VERSION 5.8 ;
BUSBITCHARS "[]" ;
DIVIDERCHAR "/" ;
UNITS
    DATABASE MICRONS 1000 ;
END UNITS

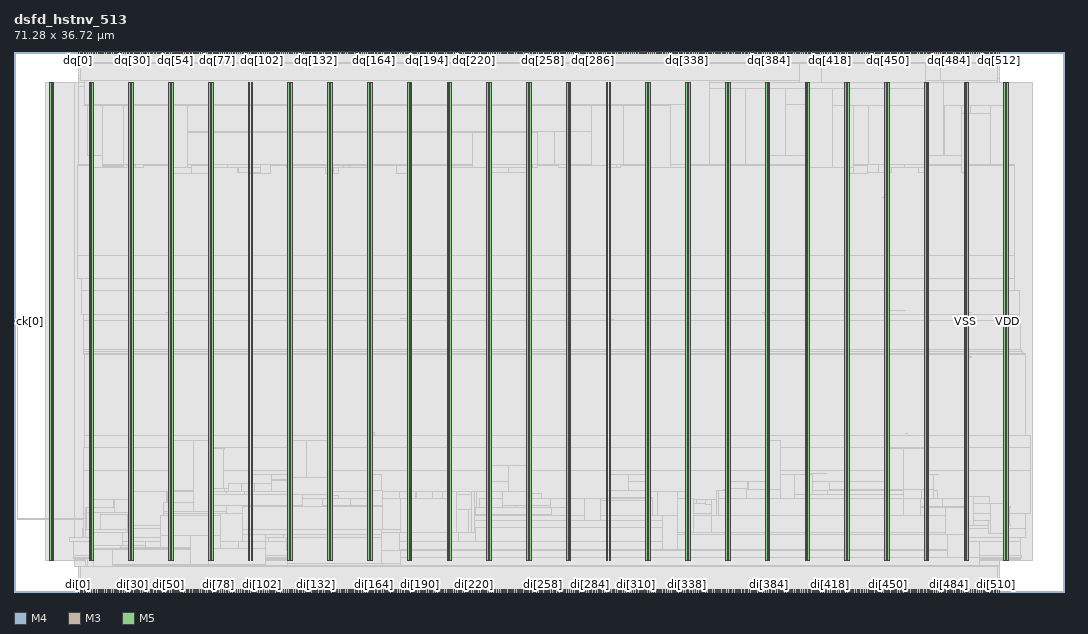
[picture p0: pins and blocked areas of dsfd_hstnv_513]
MACRO dsfd_hstnv_513
  FOREIGN dsfd_hstnv_513 0 0 ;
  CLASS BLOCK ;
  SIZE 71.28 BY 36.72 ;
  PIN ck[0]
    DIRECTION INPUT ;
    USE SIGNAL ;
    PORT
      LAYER M4 ;
        RECT  0 18.384 0.192 18.408 ;
    END
    PORT
      LAYER M4 ;
        RECT  0.156 18.384 0.275 18.408 ;
    END
  END ck[0]
  PIN di[0]
    DIRECTION INPUT ;
    USE SIGNAL ;
    PORT
      LAYER M3 ;
        RECT  4.356 0 4.374 0.144 ;
    END
  END di[0]
  PIN di[100]
    DIRECTION INPUT ;
    USE SIGNAL ;
    PORT
      LAYER M3 ;
        RECT  16.596 0 16.614 0.144 ;
    END
  END di[100]
  PIN di[101]
    DIRECTION INPUT ;
    USE SIGNAL ;
    PORT
      LAYER M5 ;
        RECT  16.704 0 16.728 0.192 ;
    END
  END di[101]
  PIN di[102]
    DIRECTION INPUT ;
    USE SIGNAL ;
    PORT
      LAYER M3 ;
        RECT  16.812 0 16.83 0.144 ;
    END
  END di[102]
  PIN di[103]
    DIRECTION INPUT ;
    USE SIGNAL ;
    PORT
      LAYER M5 ;
        RECT  16.944 0 16.968 0.192 ;
    END
  END di[103]
  PIN di[104]
    DIRECTION INPUT ;
    USE SIGNAL ;
    PORT
      LAYER M3 ;
        RECT  17.064 0 17.082 0.144 ;
    END
  END di[104]
  PIN di[105]
    DIRECTION INPUT ;
    USE SIGNAL ;
    PORT
      LAYER M5 ;
        RECT  17.184 0 17.208 0.192 ;
    END
  END di[105]
  PIN di[106]
    DIRECTION INPUT ;
    USE SIGNAL ;
    PORT
      LAYER M3 ;
        RECT  17.316 0 17.334 0.144 ;
    END
  END di[106]
  PIN di[107]
    DIRECTION INPUT ;
    USE SIGNAL ;
    PORT
      LAYER M5 ;
        RECT  17.424 0 17.448 0.192 ;
    END
  END di[107]
  PIN di[108]
    DIRECTION INPUT ;
    USE SIGNAL ;
    PORT
      LAYER M3 ;
        RECT  17.568 0 17.586 0.144 ;
    END
  END di[108]
  PIN di[109]
    DIRECTION INPUT ;
    USE SIGNAL ;
    PORT
      LAYER M5 ;
        RECT  17.664 0 17.688 0.192 ;
    END
  END di[109]
  PIN di[10]
    DIRECTION INPUT ;
    USE SIGNAL ;
    PORT
      LAYER M3 ;
        RECT  5.58 0 5.598 0.144 ;
    END
  END di[10]
  PIN di[110]
    DIRECTION INPUT ;
    USE SIGNAL ;
    PORT
      LAYER M3 ;
        RECT  17.82 0 17.838 0.144 ;
    END
  END di[110]
  PIN di[111]
    DIRECTION INPUT ;
    USE SIGNAL ;
    PORT
      LAYER M5 ;
        RECT  17.904 0 17.928 0.192 ;
    END
  END di[111]
  PIN di[112]
    DIRECTION INPUT ;
    USE SIGNAL ;
    PORT
      LAYER M3 ;
        RECT  18.036 0 18.054 0.144 ;
    END
  END di[112]
  PIN di[113]
    DIRECTION INPUT ;
    USE SIGNAL ;
    PORT
      LAYER M5 ;
        RECT  18.144 0 18.168 0.192 ;
    END
  END di[113]
  PIN di[114]
    DIRECTION INPUT ;
    USE SIGNAL ;
    PORT
      LAYER M3 ;
        RECT  18.288 0 18.306 0.144 ;
    END
  END di[114]
  PIN di[115]
    DIRECTION INPUT ;
    USE SIGNAL ;
    PORT
      LAYER M5 ;
        RECT  18.432 0 18.456 0.192 ;
    END
  END di[115]
  PIN di[116]
    DIRECTION INPUT ;
    USE SIGNAL ;
    PORT
      LAYER M3 ;
        RECT  18.54 0 18.558 0.144 ;
    END
  END di[116]
  PIN di[117]
    DIRECTION INPUT ;
    USE SIGNAL ;
    PORT
      LAYER M5 ;
        RECT  18.672 0 18.696 0.192 ;
    END
  END di[117]
  PIN di[118]
    DIRECTION INPUT ;
    USE SIGNAL ;
    PORT
      LAYER M3 ;
        RECT  18.792 0 18.81 0.144 ;
    END
  END di[118]
  PIN di[119]
    DIRECTION INPUT ;
    USE SIGNAL ;
    PORT
      LAYER M5 ;
        RECT  18.912 0 18.936 0.192 ;
    END
  END di[119]
  PIN di[11]
    DIRECTION INPUT ;
    USE SIGNAL ;
    PORT
      LAYER M5 ;
        RECT  5.712 0 5.736 0.192 ;
    END
  END di[11]
  PIN di[120]
    DIRECTION INPUT ;
    USE SIGNAL ;
    PORT
      LAYER M3 ;
        RECT  19.008 0 19.026 0.144 ;
    END
  END di[120]
  PIN di[121]
    DIRECTION INPUT ;
    USE SIGNAL ;
    PORT
      LAYER M5 ;
        RECT  19.152 0 19.176 0.192 ;
    END
  END di[121]
  PIN di[122]
    DIRECTION INPUT ;
    USE SIGNAL ;
    PORT
      LAYER M3 ;
        RECT  19.26 0 19.278 0.144 ;
    END
  END di[122]
  PIN di[123]
    DIRECTION INPUT ;
    USE SIGNAL ;
    PORT
      LAYER M5 ;
        RECT  19.392 0 19.416 0.192 ;
    END
  END di[123]
  PIN di[124]
    DIRECTION INPUT ;
    USE SIGNAL ;
    PORT
      LAYER M3 ;
        RECT  19.512 0 19.53 0.144 ;
    END
  END di[124]
  PIN di[125]
    DIRECTION INPUT ;
    USE SIGNAL ;
    PORT
      LAYER M5 ;
        RECT  19.632 0 19.656 0.192 ;
    END
  END di[125]
  PIN di[126]
    DIRECTION INPUT ;
    USE SIGNAL ;
    PORT
      LAYER M3 ;
        RECT  19.764 0 19.782 0.144 ;
    END
  END di[126]
  PIN di[127]
    DIRECTION INPUT ;
    USE SIGNAL ;
    PORT
      LAYER M5 ;
        RECT  19.872 0 19.896 0.192 ;
    END
  END di[127]
  PIN di[128]
    DIRECTION INPUT ;
    USE SIGNAL ;
    PORT
      LAYER M3 ;
        RECT  20.016 0 20.034 0.144 ;
    END
  END di[128]
  PIN di[129]
    DIRECTION INPUT ;
    USE SIGNAL ;
    PORT
      LAYER M5 ;
        RECT  20.112 0 20.136 0.192 ;
    END
  END di[129]
  PIN di[12]
    DIRECTION INPUT ;
    USE SIGNAL ;
    PORT
      LAYER M3 ;
        RECT  5.832 0 5.85 0.144 ;
    END
  END di[12]
  PIN di[130]
    DIRECTION INPUT ;
    USE SIGNAL ;
    PORT
      LAYER M3 ;
        RECT  20.232 0 20.25 0.144 ;
    END
  END di[130]
  PIN di[131]
    DIRECTION INPUT ;
    USE SIGNAL ;
    PORT
      LAYER M5 ;
        RECT  20.352 0 20.376 0.192 ;
    END
  END di[131]
  PIN di[132]
    DIRECTION INPUT ;
    USE SIGNAL ;
    PORT
      LAYER M3 ;
        RECT  20.484 0 20.502 0.144 ;
    END
  END di[132]
  PIN di[133]
    DIRECTION INPUT ;
    USE SIGNAL ;
    PORT
      LAYER M5 ;
        RECT  20.592 0 20.616 0.192 ;
    END
  END di[133]
  PIN di[134]
    DIRECTION INPUT ;
    USE SIGNAL ;
    PORT
      LAYER M3 ;
        RECT  20.736 0 20.754 0.144 ;
    END
  END di[134]
  PIN di[135]
    DIRECTION INPUT ;
    USE SIGNAL ;
    PORT
      LAYER M5 ;
        RECT  20.832 0 20.856 0.192 ;
    END
  END di[135]
  PIN di[136]
    DIRECTION INPUT ;
    USE SIGNAL ;
    PORT
      LAYER M3 ;
        RECT  20.988 0 21.006 0.144 ;
    END
  END di[136]
  PIN di[137]
    DIRECTION INPUT ;
    USE SIGNAL ;
    PORT
      LAYER M5 ;
        RECT  21.12 0 21.144 0.192 ;
    END
  END di[137]
  PIN di[138]
    DIRECTION INPUT ;
    USE SIGNAL ;
    PORT
      LAYER M3 ;
        RECT  21.24 0 21.258 0.144 ;
    END
  END di[138]
  PIN di[139]
    DIRECTION INPUT ;
    USE SIGNAL ;
    PORT
      LAYER M5 ;
        RECT  21.36 0 21.384 0.192 ;
    END
  END di[139]
  PIN di[13]
    DIRECTION INPUT ;
    USE SIGNAL ;
    PORT
      LAYER M5 ;
        RECT  5.952 0 5.976 0.192 ;
    END
  END di[13]
  PIN di[140]
    DIRECTION INPUT ;
    USE SIGNAL ;
    PORT
      LAYER M3 ;
        RECT  21.456 0 21.474 0.144 ;
    END
  END di[140]
  PIN di[141]
    DIRECTION INPUT ;
    USE SIGNAL ;
    PORT
      LAYER M5 ;
        RECT  21.6 0 21.624 0.192 ;
    END
  END di[141]
  PIN di[142]
    DIRECTION INPUT ;
    USE SIGNAL ;
    PORT
      LAYER M3 ;
        RECT  21.708 0 21.726 0.144 ;
    END
  END di[142]
  PIN di[143]
    DIRECTION INPUT ;
    USE SIGNAL ;
    PORT
      LAYER M5 ;
        RECT  21.84 0 21.864 0.192 ;
    END
  END di[143]
  PIN di[144]
    DIRECTION INPUT ;
    USE SIGNAL ;
    PORT
      LAYER M3 ;
        RECT  21.96 0 21.978 0.144 ;
    END
  END di[144]
  PIN di[145]
    DIRECTION INPUT ;
    USE SIGNAL ;
    PORT
      LAYER M5 ;
        RECT  22.08 0 22.104 0.192 ;
    END
  END di[145]
  PIN di[146]
    DIRECTION INPUT ;
    USE SIGNAL ;
    PORT
      LAYER M3 ;
        RECT  22.212 0 22.23 0.144 ;
    END
  END di[146]
  PIN di[147]
    DIRECTION INPUT ;
    USE SIGNAL ;
    PORT
      LAYER M5 ;
        RECT  22.32 0 22.344 0.192 ;
    END
  END di[147]
  PIN di[148]
    DIRECTION INPUT ;
    USE SIGNAL ;
    PORT
      LAYER M3 ;
        RECT  22.428 0 22.446 0.144 ;
    END
  END di[148]
  PIN di[149]
    DIRECTION INPUT ;
    USE SIGNAL ;
    PORT
      LAYER M5 ;
        RECT  22.56 0 22.584 0.192 ;
    END
  END di[149]
  PIN di[14]
    DIRECTION INPUT ;
    USE SIGNAL ;
    PORT
      LAYER M3 ;
        RECT  6.084 0 6.102 0.144 ;
    END
  END di[14]
  PIN di[150]
    DIRECTION INPUT ;
    USE SIGNAL ;
    PORT
      LAYER M3 ;
        RECT  22.68 0 22.698 0.144 ;
    END
  END di[150]
  PIN di[151]
    DIRECTION INPUT ;
    USE SIGNAL ;
    PORT
      LAYER M5 ;
        RECT  22.8 0 22.824 0.192 ;
    END
  END di[151]
  PIN di[152]
    DIRECTION INPUT ;
    USE SIGNAL ;
    PORT
      LAYER M3 ;
        RECT  22.932 0 22.95 0.144 ;
    END
  END di[152]
  PIN di[153]
    DIRECTION INPUT ;
    USE SIGNAL ;
    PORT
      LAYER M5 ;
        RECT  23.04 0 23.064 0.192 ;
    END
  END di[153]
  PIN di[154]
    DIRECTION INPUT ;
    USE SIGNAL ;
    PORT
      LAYER M3 ;
        RECT  23.184 0 23.202 0.144 ;
    END
  END di[154]
  PIN di[155]
    DIRECTION INPUT ;
    USE SIGNAL ;
    PORT
      LAYER M5 ;
        RECT  23.28 0 23.304 0.192 ;
    END
  END di[155]
  PIN di[156]
    DIRECTION INPUT ;
    USE SIGNAL ;
    PORT
      LAYER M3 ;
        RECT  23.436 0 23.454 0.144 ;
    END
  END di[156]
  PIN di[157]
    DIRECTION INPUT ;
    USE SIGNAL ;
    PORT
      LAYER M5 ;
        RECT  23.52 0 23.544 0.192 ;
    END
  END di[157]
  PIN di[158]
    DIRECTION INPUT ;
    USE SIGNAL ;
    PORT
      LAYER M3 ;
        RECT  23.652 0 23.67 0.144 ;
    END
  END di[158]
  PIN di[159]
    DIRECTION INPUT ;
    USE SIGNAL ;
    PORT
      LAYER M5 ;
        RECT  23.76 0 23.784 0.192 ;
    END
  END di[159]
  PIN di[15]
    DIRECTION INPUT ;
    USE SIGNAL ;
    PORT
      LAYER M5 ;
        RECT  6.192 0 6.216 0.192 ;
    END
  END di[15]
  PIN di[160]
    DIRECTION INPUT ;
    USE SIGNAL ;
    PORT
      LAYER M3 ;
        RECT  23.904 0 23.922 0.144 ;
    END
  END di[160]
  PIN di[161]
    DIRECTION INPUT ;
    USE SIGNAL ;
    PORT
      LAYER M5 ;
        RECT  24.048 0 24.072 0.192 ;
    END
  END di[161]
  PIN di[162]
    DIRECTION INPUT ;
    USE SIGNAL ;
    PORT
      LAYER M3 ;
        RECT  24.156 0 24.174 0.144 ;
    END
  END di[162]
  PIN di[163]
    DIRECTION INPUT ;
    USE SIGNAL ;
    PORT
      LAYER M5 ;
        RECT  24.288 0 24.312 0.192 ;
    END
  END di[163]
  PIN di[164]
    DIRECTION INPUT ;
    USE SIGNAL ;
    PORT
      LAYER M3 ;
        RECT  24.408 0 24.426 0.144 ;
    END
  END di[164]
  PIN di[165]
    DIRECTION INPUT ;
    USE SIGNAL ;
    PORT
      LAYER M5 ;
        RECT  24.528 0 24.552 0.192 ;
    END
  END di[165]
  PIN di[166]
    DIRECTION INPUT ;
    USE SIGNAL ;
    PORT
      LAYER M3 ;
        RECT  24.624 0 24.642 0.144 ;
    END
  END di[166]
  PIN di[167]
    DIRECTION INPUT ;
    USE SIGNAL ;
    PORT
      LAYER M5 ;
        RECT  24.768 0 24.792 0.192 ;
    END
  END di[167]
  PIN di[168]
    DIRECTION INPUT ;
    USE SIGNAL ;
    PORT
      LAYER M3 ;
        RECT  24.876 0 24.894 0.144 ;
    END
  END di[168]
  PIN di[169]
    DIRECTION INPUT ;
    USE SIGNAL ;
    PORT
      LAYER M5 ;
        RECT  25.008 0 25.032 0.192 ;
    END
  END di[169]
  PIN di[16]
    DIRECTION INPUT ;
    USE SIGNAL ;
    PORT
      LAYER M3 ;
        RECT  6.336 0 6.354 0.144 ;
    END
  END di[16]
  PIN di[170]
    DIRECTION INPUT ;
    USE SIGNAL ;
    PORT
      LAYER M3 ;
        RECT  25.128 0 25.146 0.144 ;
    END
  END di[170]
  PIN di[171]
    DIRECTION INPUT ;
    USE SIGNAL ;
    PORT
      LAYER M5 ;
        RECT  25.248 0 25.272 0.192 ;
    END
  END di[171]
  PIN di[172]
    DIRECTION INPUT ;
    USE SIGNAL ;
    PORT
      LAYER M3 ;
        RECT  25.38 0 25.398 0.144 ;
    END
  END di[172]
  PIN di[173]
    DIRECTION INPUT ;
    USE SIGNAL ;
    PORT
      LAYER M5 ;
        RECT  25.488 0 25.512 0.192 ;
    END
  END di[173]
  PIN di[174]
    DIRECTION INPUT ;
    USE SIGNAL ;
    PORT
      LAYER M3 ;
        RECT  25.632 0 25.65 0.144 ;
    END
  END di[174]
  PIN di[175]
    DIRECTION INPUT ;
    USE SIGNAL ;
    PORT
      LAYER M5 ;
        RECT  25.728 0 25.752 0.192 ;
    END
  END di[175]
  PIN di[176]
    DIRECTION INPUT ;
    USE SIGNAL ;
    PORT
      LAYER M3 ;
        RECT  25.848 0 25.866 0.144 ;
    END
  END di[176]
  PIN di[177]
    DIRECTION INPUT ;
    USE SIGNAL ;
    PORT
      LAYER M5 ;
        RECT  25.968 0 25.992 0.192 ;
    END
  END di[177]
  PIN di[178]
    DIRECTION INPUT ;
    USE SIGNAL ;
    PORT
      LAYER M3 ;
        RECT  26.1 0 26.118 0.144 ;
    END
  END di[178]
  PIN di[179]
    DIRECTION INPUT ;
    USE SIGNAL ;
    PORT
      LAYER M5 ;
        RECT  26.208 0 26.232 0.192 ;
    END
  END di[179]
  PIN di[17]
    DIRECTION INPUT ;
    USE SIGNAL ;
    PORT
      LAYER M5 ;
        RECT  6.432 0 6.456 0.192 ;
    END
  END di[17]
  PIN di[180]
    DIRECTION INPUT ;
    USE SIGNAL ;
    PORT
      LAYER M3 ;
        RECT  26.352 0 26.37 0.144 ;
    END
  END di[180]
  PIN di[181]
    DIRECTION INPUT ;
    USE SIGNAL ;
    PORT
      LAYER M5 ;
        RECT  26.448 0 26.472 0.192 ;
    END
  END di[181]
  PIN di[182]
    DIRECTION INPUT ;
    USE SIGNAL ;
    PORT
      LAYER M3 ;
        RECT  26.604 0 26.622 0.144 ;
    END
  END di[182]
  PIN di[183]
    DIRECTION INPUT ;
    USE SIGNAL ;
    PORT
      LAYER M5 ;
        RECT  26.736 0 26.76 0.192 ;
    END
  END di[183]
  PIN di[184]
    DIRECTION INPUT ;
    USE SIGNAL ;
    PORT
      LAYER M3 ;
        RECT  26.856 0 26.874 0.144 ;
    END
  END di[184]
  PIN di[185]
    DIRECTION INPUT ;
    USE SIGNAL ;
    PORT
      LAYER M5 ;
        RECT  26.976 0 27 0.192 ;
    END
  END di[185]
  PIN di[186]
    DIRECTION INPUT ;
    USE SIGNAL ;
    PORT
      LAYER M3 ;
        RECT  27.072 0 27.09 0.144 ;
    END
  END di[186]
  PIN di[187]
    DIRECTION INPUT ;
    USE SIGNAL ;
    PORT
      LAYER M5 ;
        RECT  27.216 0 27.24 0.192 ;
    END
  END di[187]
  PIN di[188]
    DIRECTION INPUT ;
    USE SIGNAL ;
    PORT
      LAYER M3 ;
        RECT  27.324 0 27.342 0.144 ;
    END
  END di[188]
  PIN di[189]
    DIRECTION INPUT ;
    USE SIGNAL ;
    PORT
      LAYER M5 ;
        RECT  27.456 0 27.48 0.192 ;
    END
  END di[189]
  PIN di[18]
    DIRECTION INPUT ;
    USE SIGNAL ;
    PORT
      LAYER M3 ;
        RECT  6.552 0 6.57 0.144 ;
    END
  END di[18]
  PIN di[190]
    DIRECTION INPUT ;
    USE SIGNAL ;
    PORT
      LAYER M3 ;
        RECT  27.576 0 27.594 0.144 ;
    END
  END di[190]
  PIN di[191]
    DIRECTION INPUT ;
    USE SIGNAL ;
    PORT
      LAYER M5 ;
        RECT  27.696 0 27.72 0.192 ;
    END
  END di[191]
  PIN di[192]
    DIRECTION INPUT ;
    USE SIGNAL ;
    PORT
      LAYER M3 ;
        RECT  27.828 0 27.846 0.144 ;
    END
  END di[192]
  PIN di[193]
    DIRECTION INPUT ;
    USE SIGNAL ;
    PORT
      LAYER M5 ;
        RECT  27.936 0 27.96 0.192 ;
    END
  END di[193]
  PIN di[194]
    DIRECTION INPUT ;
    USE SIGNAL ;
    PORT
      LAYER M3 ;
        RECT  28.044 0 28.062 0.144 ;
    END
  END di[194]
  PIN di[195]
    DIRECTION INPUT ;
    USE SIGNAL ;
    PORT
      LAYER M5 ;
        RECT  28.176 0 28.2 0.192 ;
    END
  END di[195]
  PIN di[196]
    DIRECTION INPUT ;
    USE SIGNAL ;
    PORT
      LAYER M3 ;
        RECT  28.296 0 28.314 0.144 ;
    END
  END di[196]
  PIN di[197]
    DIRECTION INPUT ;
    USE SIGNAL ;
    PORT
      LAYER M5 ;
        RECT  28.416 0 28.44 0.192 ;
    END
  END di[197]
  PIN di[198]
    DIRECTION INPUT ;
    USE SIGNAL ;
    PORT
      LAYER M3 ;
        RECT  28.548 0 28.566 0.144 ;
    END
  END di[198]
  PIN di[199]
    DIRECTION INPUT ;
    USE SIGNAL ;
    PORT
      LAYER M5 ;
        RECT  28.656 0 28.68 0.192 ;
    END
  END di[199]
  PIN di[19]
    DIRECTION INPUT ;
    USE SIGNAL ;
    PORT
      LAYER M5 ;
        RECT  6.672 0 6.696 0.192 ;
    END
  END di[19]
  PIN di[1]
    DIRECTION INPUT ;
    USE SIGNAL ;
    PORT
      LAYER M5 ;
        RECT  4.512 0 4.536 0.192 ;
    END
  END di[1]
  PIN di[200]
    DIRECTION INPUT ;
    USE SIGNAL ;
    PORT
      LAYER M3 ;
        RECT  28.8 0 28.818 0.144 ;
    END
  END di[200]
  PIN di[201]
    DIRECTION INPUT ;
    USE SIGNAL ;
    PORT
      LAYER M5 ;
        RECT  28.896 0 28.92 0.192 ;
    END
  END di[201]
  PIN di[202]
    DIRECTION INPUT ;
    USE SIGNAL ;
    PORT
      LAYER M3 ;
        RECT  29.052 0 29.07 0.144 ;
    END
  END di[202]
  PIN di[203]
    DIRECTION INPUT ;
    USE SIGNAL ;
    PORT
      LAYER M5 ;
        RECT  29.136 0 29.16 0.192 ;
    END
  END di[203]
  PIN di[204]
    DIRECTION INPUT ;
    USE SIGNAL ;
    PORT
      LAYER M3 ;
        RECT  29.268 0 29.286 0.144 ;
    END
  END di[204]
  PIN di[205]
    DIRECTION INPUT ;
    USE SIGNAL ;
    PORT
      LAYER M5 ;
        RECT  29.424 0 29.448 0.192 ;
    END
  END di[205]
  PIN di[206]
    DIRECTION INPUT ;
    USE SIGNAL ;
    PORT
      LAYER M3 ;
        RECT  29.52 0 29.538 0.144 ;
    END
  END di[206]
  PIN di[207]
    DIRECTION INPUT ;
    USE SIGNAL ;
    PORT
      LAYER M5 ;
        RECT  29.664 0 29.688 0.192 ;
    END
  END di[207]
  PIN di[208]
    DIRECTION INPUT ;
    USE SIGNAL ;
    PORT
      LAYER M3 ;
        RECT  29.772 0 29.79 0.144 ;
    END
  END di[208]
  PIN di[209]
    DIRECTION INPUT ;
    USE SIGNAL ;
    PORT
      LAYER M5 ;
        RECT  29.904 0 29.928 0.192 ;
    END
  END di[209]
  PIN di[20]
    DIRECTION INPUT ;
    USE SIGNAL ;
    PORT
      LAYER M3 ;
        RECT  6.804 0 6.822 0.144 ;
    END
  END di[20]
  PIN di[210]
    DIRECTION INPUT ;
    USE SIGNAL ;
    PORT
      LAYER M3 ;
        RECT  30.024 0 30.042 0.144 ;
    END
  END di[210]
  PIN di[211]
    DIRECTION INPUT ;
    USE SIGNAL ;
    PORT
      LAYER M5 ;
        RECT  30.144 0 30.168 0.192 ;
    END
  END di[211]
  PIN di[212]
    DIRECTION INPUT ;
    USE SIGNAL ;
    PORT
      LAYER M3 ;
        RECT  30.276 0 30.294 0.144 ;
    END
  END di[212]
  PIN di[213]
    DIRECTION INPUT ;
    USE SIGNAL ;
    PORT
      LAYER M5 ;
        RECT  30.384 0 30.408 0.192 ;
    END
  END di[213]
  PIN di[214]
    DIRECTION INPUT ;
    USE SIGNAL ;
    PORT
      LAYER M3 ;
        RECT  30.492 0 30.51 0.144 ;
    END
  END di[214]
  PIN di[215]
    DIRECTION INPUT ;
    USE SIGNAL ;
    PORT
      LAYER M5 ;
        RECT  30.624 0 30.648 0.192 ;
    END
  END di[215]
  PIN di[216]
    DIRECTION INPUT ;
    USE SIGNAL ;
    PORT
      LAYER M3 ;
        RECT  30.744 0 30.762 0.144 ;
    END
  END di[216]
  PIN di[217]
    DIRECTION INPUT ;
    USE SIGNAL ;
    PORT
      LAYER M5 ;
        RECT  30.864 0 30.888 0.192 ;
    END
  END di[217]
  PIN di[218]
    DIRECTION INPUT ;
    USE SIGNAL ;
    PORT
      LAYER M3 ;
        RECT  30.996 0 31.014 0.144 ;
    END
  END di[218]
  PIN di[219]
    DIRECTION INPUT ;
    USE SIGNAL ;
    PORT
      LAYER M5 ;
        RECT  31.104 0 31.128 0.192 ;
    END
  END di[219]
  PIN di[21]
    DIRECTION INPUT ;
    USE SIGNAL ;
    PORT
      LAYER M5 ;
        RECT  6.912 0 6.936 0.192 ;
    END
  END di[21]
  PIN di[220]
    DIRECTION INPUT ;
    USE SIGNAL ;
    PORT
      LAYER M3 ;
        RECT  31.248 0 31.266 0.144 ;
    END
  END di[220]
  PIN di[221]
    DIRECTION INPUT ;
    USE SIGNAL ;
    PORT
      LAYER M5 ;
        RECT  31.344 0 31.368 0.192 ;
    END
  END di[221]
  PIN di[222]
    DIRECTION INPUT ;
    USE SIGNAL ;
    PORT
      LAYER M3 ;
        RECT  31.464 0 31.482 0.144 ;
    END
  END di[222]
  PIN di[223]
    DIRECTION INPUT ;
    USE SIGNAL ;
    PORT
      LAYER M5 ;
        RECT  31.584 0 31.608 0.192 ;
    END
  END di[223]
  PIN di[224]
    DIRECTION INPUT ;
    USE SIGNAL ;
    PORT
      LAYER M3 ;
        RECT  31.716 0 31.734 0.144 ;
    END
  END di[224]
  PIN di[225]
    DIRECTION INPUT ;
    USE SIGNAL ;
    PORT
      LAYER M5 ;
        RECT  31.824 0 31.848 0.192 ;
    END
  END di[225]
  PIN di[226]
    DIRECTION INPUT ;
    USE SIGNAL ;
    PORT
      LAYER M3 ;
        RECT  31.968 0 31.986 0.144 ;
    END
  END di[226]
  PIN di[227]
    DIRECTION INPUT ;
    USE SIGNAL ;
    PORT
      LAYER M5 ;
        RECT  32.064 0 32.088 0.192 ;
    END
  END di[227]
  PIN di[228]
    DIRECTION INPUT ;
    USE SIGNAL ;
    PORT
      LAYER M3 ;
        RECT  32.22 0 32.238 0.144 ;
    END
  END di[228]
  PIN di[229]
    DIRECTION INPUT ;
    USE SIGNAL ;
    PORT
      LAYER M5 ;
        RECT  32.352 0 32.376 0.192 ;
    END
  END di[229]
  PIN di[22]
    DIRECTION INPUT ;
    USE SIGNAL ;
    PORT
      LAYER M3 ;
        RECT  7.056 0 7.074 0.144 ;
    END
  END di[22]
  PIN di[230]
    DIRECTION INPUT ;
    USE SIGNAL ;
    PORT
      LAYER M3 ;
        RECT  32.472 0 32.49 0.144 ;
    END
  END di[230]
  PIN di[231]
    DIRECTION INPUT ;
    USE SIGNAL ;
    PORT
      LAYER M5 ;
        RECT  32.592 0 32.616 0.192 ;
    END
  END di[231]
  PIN di[232]
    DIRECTION INPUT ;
    USE SIGNAL ;
    PORT
      LAYER M3 ;
        RECT  32.688 0 32.706 0.144 ;
    END
  END di[232]
  PIN di[233]
    DIRECTION INPUT ;
    USE SIGNAL ;
    PORT
      LAYER M5 ;
        RECT  32.832 0 32.856 0.192 ;
    END
  END di[233]
  PIN di[234]
    DIRECTION INPUT ;
    USE SIGNAL ;
    PORT
      LAYER M3 ;
        RECT  32.94 0 32.958 0.144 ;
    END
  END di[234]
  PIN di[235]
    DIRECTION INPUT ;
    USE SIGNAL ;
    PORT
      LAYER M5 ;
        RECT  33.072 0 33.096 0.192 ;
    END
  END di[235]
  PIN di[236]
    DIRECTION INPUT ;
    USE SIGNAL ;
    PORT
      LAYER M3 ;
        RECT  33.192 0 33.21 0.144 ;
    END
  END di[236]
  PIN di[237]
    DIRECTION INPUT ;
    USE SIGNAL ;
    PORT
      LAYER M5 ;
        RECT  33.312 0 33.336 0.192 ;
    END
  END di[237]
  PIN di[238]
    DIRECTION INPUT ;
    USE SIGNAL ;
    PORT
      LAYER M3 ;
        RECT  33.444 0 33.462 0.144 ;
    END
  END di[238]
  PIN di[239]
    DIRECTION INPUT ;
    USE SIGNAL ;
    PORT
      LAYER M5 ;
        RECT  33.552 0 33.576 0.192 ;
    END
  END di[239]
  PIN di[23]
    DIRECTION INPUT ;
    USE SIGNAL ;
    PORT
      LAYER M5 ;
        RECT  7.2 0 7.224 0.192 ;
    END
  END di[23]
  PIN di[240]
    DIRECTION INPUT ;
    USE SIGNAL ;
    PORT
      LAYER M3 ;
        RECT  33.66 0 33.678 0.144 ;
    END
  END di[240]
  PIN di[241]
    DIRECTION INPUT ;
    USE SIGNAL ;
    PORT
      LAYER M5 ;
        RECT  33.792 0 33.816 0.192 ;
    END
  END di[241]
  PIN di[242]
    DIRECTION INPUT ;
    USE SIGNAL ;
    PORT
      LAYER M3 ;
        RECT  33.912 0 33.93 0.144 ;
    END
  END di[242]
  PIN di[243]
    DIRECTION INPUT ;
    USE SIGNAL ;
    PORT
      LAYER M5 ;
        RECT  34.032 0 34.056 0.192 ;
    END
  END di[243]
  PIN di[244]
    DIRECTION INPUT ;
    USE SIGNAL ;
    PORT
      LAYER M3 ;
        RECT  34.164 0 34.182 0.144 ;
    END
  END di[244]
  PIN di[245]
    DIRECTION INPUT ;
    USE SIGNAL ;
    PORT
      LAYER M5 ;
        RECT  34.272 0 34.296 0.192 ;
    END
  END di[245]
  PIN di[246]
    DIRECTION INPUT ;
    USE SIGNAL ;
    PORT
      LAYER M3 ;
        RECT  34.416 0 34.434 0.144 ;
    END
  END di[246]
  PIN di[247]
    DIRECTION INPUT ;
    USE SIGNAL ;
    PORT
      LAYER M5 ;
        RECT  34.512 0 34.536 0.192 ;
    END
  END di[247]
  PIN di[248]
    DIRECTION INPUT ;
    USE SIGNAL ;
    PORT
      LAYER M3 ;
        RECT  34.668 0 34.686 0.144 ;
    END
  END di[248]
  PIN di[249]
    DIRECTION INPUT ;
    USE SIGNAL ;
    PORT
      LAYER M5 ;
        RECT  34.752 0 34.776 0.192 ;
    END
  END di[249]
  PIN di[24]
    DIRECTION INPUT ;
    USE SIGNAL ;
    PORT
      LAYER M3 ;
        RECT  7.308 0 7.326 0.144 ;
    END
  END di[24]
  PIN di[250]
    DIRECTION INPUT ;
    USE SIGNAL ;
    PORT
      LAYER M3 ;
        RECT  34.884 0 34.902 0.144 ;
    END
  END di[250]
  PIN di[251]
    DIRECTION INPUT ;
    USE SIGNAL ;
    PORT
      LAYER M5 ;
        RECT  35.04 0 35.064 0.192 ;
    END
  END di[251]
  PIN di[252]
    DIRECTION INPUT ;
    USE SIGNAL ;
    PORT
      LAYER M3 ;
        RECT  35.136 0 35.154 0.144 ;
    END
  END di[252]
  PIN di[253]
    DIRECTION INPUT ;
    USE SIGNAL ;
    PORT
      LAYER M5 ;
        RECT  35.28 0 35.304 0.192 ;
    END
  END di[253]
  PIN di[254]
    DIRECTION INPUT ;
    USE SIGNAL ;
    PORT
      LAYER M3 ;
        RECT  35.388 0 35.406 0.144 ;
    END
  END di[254]
  PIN di[255]
    DIRECTION INPUT ;
    USE SIGNAL ;
    PORT
      LAYER M5 ;
        RECT  35.52 0 35.544 0.192 ;
    END
  END di[255]
  PIN di[256]
    DIRECTION INPUT ;
    USE SIGNAL ;
    PORT
      LAYER M3 ;
        RECT  35.64 0 35.658 0.144 ;
    END
  END di[256]
  PIN di[257]
    DIRECTION INPUT ;
    USE SIGNAL ;
    PORT
      LAYER M5 ;
        RECT  35.76 0 35.784 0.192 ;
    END
  END di[257]
  PIN di[258]
    DIRECTION INPUT ;
    USE SIGNAL ;
    PORT
      LAYER M3 ;
        RECT  35.892 0 35.91 0.144 ;
    END
  END di[258]
  PIN di[259]
    DIRECTION INPUT ;
    USE SIGNAL ;
    PORT
      LAYER M5 ;
        RECT  36 0 36.024 0.192 ;
    END
  END di[259]
  PIN di[25]
    DIRECTION INPUT ;
    USE SIGNAL ;
    PORT
      LAYER M5 ;
        RECT  7.44 0 7.464 0.192 ;
    END
  END di[25]
  PIN di[260]
    DIRECTION INPUT ;
    USE SIGNAL ;
    PORT
      LAYER M3 ;
        RECT  36.108 0 36.126 0.144 ;
    END
  END di[260]
  PIN di[261]
    DIRECTION INPUT ;
    USE SIGNAL ;
    PORT
      LAYER M5 ;
        RECT  36.24 0 36.264 0.192 ;
    END
  END di[261]
  PIN di[262]
    DIRECTION INPUT ;
    USE SIGNAL ;
    PORT
      LAYER M3 ;
        RECT  36.36 0 36.378 0.144 ;
    END
  END di[262]
  PIN di[263]
    DIRECTION INPUT ;
    USE SIGNAL ;
    PORT
      LAYER M5 ;
        RECT  36.48 0 36.504 0.192 ;
    END
  END di[263]
  PIN di[264]
    DIRECTION INPUT ;
    USE SIGNAL ;
    PORT
      LAYER M3 ;
        RECT  36.612 0 36.63 0.144 ;
    END
  END di[264]
  PIN di[265]
    DIRECTION INPUT ;
    USE SIGNAL ;
    PORT
      LAYER M5 ;
        RECT  36.72 0 36.744 0.192 ;
    END
  END di[265]
  PIN di[266]
    DIRECTION INPUT ;
    USE SIGNAL ;
    PORT
      LAYER M3 ;
        RECT  36.864 0 36.882 0.144 ;
    END
  END di[266]
  PIN di[267]
    DIRECTION INPUT ;
    USE SIGNAL ;
    PORT
      LAYER M5 ;
        RECT  36.96 0 36.984 0.192 ;
    END
  END di[267]
  PIN di[268]
    DIRECTION INPUT ;
    USE SIGNAL ;
    PORT
      LAYER M3 ;
        RECT  37.08 0 37.098 0.144 ;
    END
  END di[268]
  PIN di[269]
    DIRECTION INPUT ;
    USE SIGNAL ;
    PORT
      LAYER M5 ;
        RECT  37.2 0 37.224 0.192 ;
    END
  END di[269]
  PIN di[26]
    DIRECTION INPUT ;
    USE SIGNAL ;
    PORT
      LAYER M3 ;
        RECT  7.56 0 7.578 0.144 ;
    END
  END di[26]
  PIN di[270]
    DIRECTION INPUT ;
    USE SIGNAL ;
    PORT
      LAYER M3 ;
        RECT  37.332 0 37.35 0.144 ;
    END
  END di[270]
  PIN di[271]
    DIRECTION INPUT ;
    USE SIGNAL ;
    PORT
      LAYER M5 ;
        RECT  37.44 0 37.464 0.192 ;
    END
  END di[271]
  PIN di[272]
    DIRECTION INPUT ;
    USE SIGNAL ;
    PORT
      LAYER M3 ;
        RECT  37.584 0 37.602 0.144 ;
    END
  END di[272]
  PIN di[273]
    DIRECTION INPUT ;
    USE SIGNAL ;
    PORT
      LAYER M5 ;
        RECT  37.68 0 37.704 0.192 ;
    END
  END di[273]
  PIN di[274]
    DIRECTION INPUT ;
    USE SIGNAL ;
    PORT
      LAYER M3 ;
        RECT  37.836 0 37.854 0.144 ;
    END
  END di[274]
  PIN di[275]
    DIRECTION INPUT ;
    USE SIGNAL ;
    PORT
      LAYER M5 ;
        RECT  37.968 0 37.992 0.192 ;
    END
  END di[275]
  PIN di[276]
    DIRECTION INPUT ;
    USE SIGNAL ;
    PORT
      LAYER M3 ;
        RECT  38.088 0 38.106 0.144 ;
    END
  END di[276]
  PIN di[277]
    DIRECTION INPUT ;
    USE SIGNAL ;
    PORT
      LAYER M5 ;
        RECT  38.208 0 38.232 0.192 ;
    END
  END di[277]
  PIN di[278]
    DIRECTION INPUT ;
    USE SIGNAL ;
    PORT
      LAYER M3 ;
        RECT  38.304 0 38.322 0.144 ;
    END
  END di[278]
  PIN di[279]
    DIRECTION INPUT ;
    USE SIGNAL ;
    PORT
      LAYER M5 ;
        RECT  38.448 0 38.472 0.192 ;
    END
  END di[279]
  PIN di[27]
    DIRECTION INPUT ;
    USE SIGNAL ;
    PORT
      LAYER M5 ;
        RECT  7.68 0 7.704 0.192 ;
    END
  END di[27]
  PIN di[280]
    DIRECTION INPUT ;
    USE SIGNAL ;
    PORT
      LAYER M3 ;
        RECT  38.556 0 38.574 0.144 ;
    END
  END di[280]
  PIN di[281]
    DIRECTION INPUT ;
    USE SIGNAL ;
    PORT
      LAYER M5 ;
        RECT  38.688 0 38.712 0.192 ;
    END
  END di[281]
  PIN di[282]
    DIRECTION INPUT ;
    USE SIGNAL ;
    PORT
      LAYER M3 ;
        RECT  38.808 0 38.826 0.144 ;
    END
  END di[282]
  PIN di[283]
    DIRECTION INPUT ;
    USE SIGNAL ;
    PORT
      LAYER M5 ;
        RECT  38.928 0 38.952 0.192 ;
    END
  END di[283]
  PIN di[284]
    DIRECTION INPUT ;
    USE SIGNAL ;
    PORT
      LAYER M3 ;
        RECT  39.06 0 39.078 0.144 ;
    END
  END di[284]
  PIN di[285]
    DIRECTION INPUT ;
    USE SIGNAL ;
    PORT
      LAYER M5 ;
        RECT  39.168 0 39.192 0.192 ;
    END
  END di[285]
  PIN di[286]
    DIRECTION INPUT ;
    USE SIGNAL ;
    PORT
      LAYER M3 ;
        RECT  39.312 0 39.33 0.144 ;
    END
  END di[286]
  PIN di[287]
    DIRECTION INPUT ;
    USE SIGNAL ;
    PORT
      LAYER M5 ;
        RECT  39.408 0 39.432 0.192 ;
    END
  END di[287]
  PIN di[288]
    DIRECTION INPUT ;
    USE SIGNAL ;
    PORT
      LAYER M3 ;
        RECT  39.528 0 39.546 0.144 ;
    END
  END di[288]
  PIN di[289]
    DIRECTION INPUT ;
    USE SIGNAL ;
    PORT
      LAYER M5 ;
        RECT  39.648 0 39.672 0.192 ;
    END
  END di[289]
  PIN di[28]
    DIRECTION INPUT ;
    USE SIGNAL ;
    PORT
      LAYER M3 ;
        RECT  7.776 0 7.794 0.144 ;
    END
  END di[28]
  PIN di[290]
    DIRECTION INPUT ;
    USE SIGNAL ;
    PORT
      LAYER M3 ;
        RECT  39.78 0 39.798 0.144 ;
    END
  END di[290]
  PIN di[291]
    DIRECTION INPUT ;
    USE SIGNAL ;
    PORT
      LAYER M5 ;
        RECT  39.888 0 39.912 0.192 ;
    END
  END di[291]
  PIN di[292]
    DIRECTION INPUT ;
    USE SIGNAL ;
    PORT
      LAYER M3 ;
        RECT  40.032 0 40.05 0.144 ;
    END
  END di[292]
  PIN di[293]
    DIRECTION INPUT ;
    USE SIGNAL ;
    PORT
      LAYER M5 ;
        RECT  40.128 0 40.152 0.192 ;
    END
  END di[293]
  PIN di[294]
    DIRECTION INPUT ;
    USE SIGNAL ;
    PORT
      LAYER M3 ;
        RECT  40.284 0 40.302 0.144 ;
    END
  END di[294]
  PIN di[295]
    DIRECTION INPUT ;
    USE SIGNAL ;
    PORT
      LAYER M5 ;
        RECT  40.368 0 40.392 0.192 ;
    END
  END di[295]
  PIN di[296]
    DIRECTION INPUT ;
    USE SIGNAL ;
    PORT
      LAYER M3 ;
        RECT  40.5 0 40.518 0.144 ;
    END
  END di[296]
  PIN di[297]
    DIRECTION INPUT ;
    USE SIGNAL ;
    PORT
      LAYER M5 ;
        RECT  40.656 0 40.68 0.192 ;
    END
  END di[297]
  PIN di[298]
    DIRECTION INPUT ;
    USE SIGNAL ;
    PORT
      LAYER M3 ;
        RECT  40.752 0 40.77 0.144 ;
    END
  END di[298]
  PIN di[299]
    DIRECTION INPUT ;
    USE SIGNAL ;
    PORT
      LAYER M5 ;
        RECT  40.896 0 40.92 0.192 ;
    END
  END di[299]
  PIN di[29]
    DIRECTION INPUT ;
    USE SIGNAL ;
    PORT
      LAYER M5 ;
        RECT  7.92 0 7.944 0.192 ;
    END
  END di[29]
  PIN di[2]
    DIRECTION INPUT ;
    USE SIGNAL ;
    PORT
      LAYER M3 ;
        RECT  4.608 0 4.626 0.144 ;
    END
  END di[2]
  PIN di[300]
    DIRECTION INPUT ;
    USE SIGNAL ;
    PORT
      LAYER M3 ;
        RECT  41.004 0 41.022 0.144 ;
    END
  END di[300]
  PIN di[301]
    DIRECTION INPUT ;
    USE SIGNAL ;
    PORT
      LAYER M5 ;
        RECT  41.136 0 41.16 0.192 ;
    END
  END di[301]
  PIN di[302]
    DIRECTION INPUT ;
    USE SIGNAL ;
    PORT
      LAYER M3 ;
        RECT  41.256 0 41.274 0.144 ;
    END
  END di[302]
  PIN di[303]
    DIRECTION INPUT ;
    USE SIGNAL ;
    PORT
      LAYER M5 ;
        RECT  41.376 0 41.4 0.192 ;
    END
  END di[303]
  PIN di[304]
    DIRECTION INPUT ;
    USE SIGNAL ;
    PORT
      LAYER M3 ;
        RECT  41.508 0 41.526 0.144 ;
    END
  END di[304]
  PIN di[305]
    DIRECTION INPUT ;
    USE SIGNAL ;
    PORT
      LAYER M5 ;
        RECT  41.616 0 41.64 0.192 ;
    END
  END di[305]
  PIN di[306]
    DIRECTION INPUT ;
    USE SIGNAL ;
    PORT
      LAYER M3 ;
        RECT  41.724 0 41.742 0.144 ;
    END
  END di[306]
  PIN di[307]
    DIRECTION INPUT ;
    USE SIGNAL ;
    PORT
      LAYER M5 ;
        RECT  41.856 0 41.88 0.192 ;
    END
  END di[307]
  PIN di[308]
    DIRECTION INPUT ;
    USE SIGNAL ;
    PORT
      LAYER M3 ;
        RECT  41.976 0 41.994 0.144 ;
    END
  END di[308]
  PIN di[309]
    DIRECTION INPUT ;
    USE SIGNAL ;
    PORT
      LAYER M5 ;
        RECT  42.096 0 42.12 0.192 ;
    END
  END di[309]
  PIN di[30]
    DIRECTION INPUT ;
    USE SIGNAL ;
    PORT
      LAYER M3 ;
        RECT  8.028 0 8.046 0.144 ;
    END
  END di[30]
  PIN di[310]
    DIRECTION INPUT ;
    USE SIGNAL ;
    PORT
      LAYER M3 ;
        RECT  42.228 0 42.246 0.144 ;
    END
  END di[310]
  PIN di[311]
    DIRECTION INPUT ;
    USE SIGNAL ;
    PORT
      LAYER M5 ;
        RECT  42.336 0 42.36 0.192 ;
    END
  END di[311]
  PIN di[312]
    DIRECTION INPUT ;
    USE SIGNAL ;
    PORT
      LAYER M3 ;
        RECT  42.48 0 42.498 0.144 ;
    END
  END di[312]
  PIN di[313]
    DIRECTION INPUT ;
    USE SIGNAL ;
    PORT
      LAYER M5 ;
        RECT  42.576 0 42.6 0.192 ;
    END
  END di[313]
  PIN di[314]
    DIRECTION INPUT ;
    USE SIGNAL ;
    PORT
      LAYER M3 ;
        RECT  42.696 0 42.714 0.144 ;
    END
  END di[314]
  PIN di[315]
    DIRECTION INPUT ;
    USE SIGNAL ;
    PORT
      LAYER M5 ;
        RECT  42.816 0 42.84 0.192 ;
    END
  END di[315]
  PIN di[316]
    DIRECTION INPUT ;
    USE SIGNAL ;
    PORT
      LAYER M3 ;
        RECT  42.948 0 42.966 0.144 ;
    END
  END di[316]
  PIN di[317]
    DIRECTION INPUT ;
    USE SIGNAL ;
    PORT
      LAYER M5 ;
        RECT  43.056 0 43.08 0.192 ;
    END
  END di[317]
  PIN di[318]
    DIRECTION INPUT ;
    USE SIGNAL ;
    PORT
      LAYER M3 ;
        RECT  43.2 0 43.218 0.144 ;
    END
  END di[318]
  PIN di[319]
    DIRECTION INPUT ;
    USE SIGNAL ;
    PORT
      LAYER M5 ;
        RECT  43.344 0 43.368 0.192 ;
    END
  END di[319]
  PIN di[31]
    DIRECTION INPUT ;
    USE SIGNAL ;
    PORT
      LAYER M5 ;
        RECT  8.16 0 8.184 0.192 ;
    END
  END di[31]
  PIN di[320]
    DIRECTION INPUT ;
    USE SIGNAL ;
    PORT
      LAYER M3 ;
        RECT  43.452 0 43.47 0.144 ;
    END
  END di[320]
  PIN di[321]
    DIRECTION INPUT ;
    USE SIGNAL ;
    PORT
      LAYER M5 ;
        RECT  43.584 0 43.608 0.192 ;
    END
  END di[321]
  PIN di[322]
    DIRECTION INPUT ;
    USE SIGNAL ;
    PORT
      LAYER M3 ;
        RECT  43.704 0 43.722 0.144 ;
    END
  END di[322]
  PIN di[323]
    DIRECTION INPUT ;
    USE SIGNAL ;
    PORT
      LAYER M5 ;
        RECT  43.824 0 43.848 0.192 ;
    END
  END di[323]
  PIN di[324]
    DIRECTION INPUT ;
    USE SIGNAL ;
    PORT
      LAYER M3 ;
        RECT  43.92 0 43.938 0.144 ;
    END
  END di[324]
  PIN di[325]
    DIRECTION INPUT ;
    USE SIGNAL ;
    PORT
      LAYER M5 ;
        RECT  44.064 0 44.088 0.192 ;
    END
  END di[325]
  PIN di[326]
    DIRECTION INPUT ;
    USE SIGNAL ;
    PORT
      LAYER M3 ;
        RECT  44.172 0 44.19 0.144 ;
    END
  END di[326]
  PIN di[327]
    DIRECTION INPUT ;
    USE SIGNAL ;
    PORT
      LAYER M5 ;
        RECT  44.304 0 44.328 0.192 ;
    END
  END di[327]
  PIN di[328]
    DIRECTION INPUT ;
    USE SIGNAL ;
    PORT
      LAYER M3 ;
        RECT  44.424 0 44.442 0.144 ;
    END
  END di[328]
  PIN di[329]
    DIRECTION INPUT ;
    USE SIGNAL ;
    PORT
      LAYER M5 ;
        RECT  44.544 0 44.568 0.192 ;
    END
  END di[329]
  PIN di[32]
    DIRECTION INPUT ;
    USE SIGNAL ;
    PORT
      LAYER M3 ;
        RECT  8.28 0 8.298 0.144 ;
    END
  END di[32]
  PIN di[330]
    DIRECTION INPUT ;
    USE SIGNAL ;
    PORT
      LAYER M3 ;
        RECT  44.676 0 44.694 0.144 ;
    END
  END di[330]
  PIN di[331]
    DIRECTION INPUT ;
    USE SIGNAL ;
    PORT
      LAYER M5 ;
        RECT  44.784 0 44.808 0.192 ;
    END
  END di[331]
  PIN di[332]
    DIRECTION INPUT ;
    USE SIGNAL ;
    PORT
      LAYER M3 ;
        RECT  44.928 0 44.946 0.144 ;
    END
  END di[332]
  PIN di[333]
    DIRECTION INPUT ;
    USE SIGNAL ;
    PORT
      LAYER M5 ;
        RECT  45.024 0 45.048 0.192 ;
    END
  END di[333]
  PIN di[334]
    DIRECTION INPUT ;
    USE SIGNAL ;
    PORT
      LAYER M3 ;
        RECT  45.144 0 45.162 0.144 ;
    END
  END di[334]
  PIN di[335]
    DIRECTION INPUT ;
    USE SIGNAL ;
    PORT
      LAYER M5 ;
        RECT  45.264 0 45.288 0.192 ;
    END
  END di[335]
  PIN di[336]
    DIRECTION INPUT ;
    USE SIGNAL ;
    PORT
      LAYER M3 ;
        RECT  45.396 0 45.414 0.144 ;
    END
  END di[336]
  PIN di[337]
    DIRECTION INPUT ;
    USE SIGNAL ;
    PORT
      LAYER M5 ;
        RECT  45.504 0 45.528 0.192 ;
    END
  END di[337]
  PIN di[338]
    DIRECTION INPUT ;
    USE SIGNAL ;
    PORT
      LAYER M3 ;
        RECT  45.648 0 45.666 0.144 ;
    END
  END di[338]
  PIN di[339]
    DIRECTION INPUT ;
    USE SIGNAL ;
    PORT
      LAYER M5 ;
        RECT  45.744 0 45.768 0.192 ;
    END
  END di[339]
  PIN di[33]
    DIRECTION INPUT ;
    USE SIGNAL ;
    PORT
      LAYER M5 ;
        RECT  8.4 0 8.424 0.192 ;
    END
  END di[33]
  PIN di[340]
    DIRECTION INPUT ;
    USE SIGNAL ;
    PORT
      LAYER M3 ;
        RECT  45.9 0 45.918 0.144 ;
    END
  END di[340]
  PIN di[341]
    DIRECTION INPUT ;
    USE SIGNAL ;
    PORT
      LAYER M5 ;
        RECT  45.984 0 46.008 0.192 ;
    END
  END di[341]
  PIN di[342]
    DIRECTION INPUT ;
    USE SIGNAL ;
    PORT
      LAYER M3 ;
        RECT  46.116 0 46.134 0.144 ;
    END
  END di[342]
  PIN di[343]
    DIRECTION INPUT ;
    USE SIGNAL ;
    PORT
      LAYER M5 ;
        RECT  46.272 0 46.296 0.192 ;
    END
  END di[343]
  PIN di[344]
    DIRECTION INPUT ;
    USE SIGNAL ;
    PORT
      LAYER M3 ;
        RECT  46.368 0 46.386 0.144 ;
    END
  END di[344]
  PIN di[345]
    DIRECTION INPUT ;
    USE SIGNAL ;
    PORT
      LAYER M5 ;
        RECT  46.512 0 46.536 0.192 ;
    END
  END di[345]
  PIN di[346]
    DIRECTION INPUT ;
    USE SIGNAL ;
    PORT
      LAYER M3 ;
        RECT  46.62 0 46.638 0.144 ;
    END
  END di[346]
  PIN di[347]
    DIRECTION INPUT ;
    USE SIGNAL ;
    PORT
      LAYER M5 ;
        RECT  46.752 0 46.776 0.192 ;
    END
  END di[347]
  PIN di[348]
    DIRECTION INPUT ;
    USE SIGNAL ;
    PORT
      LAYER M3 ;
        RECT  46.872 0 46.89 0.144 ;
    END
  END di[348]
  PIN di[349]
    DIRECTION INPUT ;
    USE SIGNAL ;
    PORT
      LAYER M5 ;
        RECT  46.992 0 47.016 0.192 ;
    END
  END di[349]
  PIN di[34]
    DIRECTION INPUT ;
    USE SIGNAL ;
    PORT
      LAYER M3 ;
        RECT  8.532 0 8.55 0.144 ;
    END
  END di[34]
  PIN di[350]
    DIRECTION INPUT ;
    USE SIGNAL ;
    PORT
      LAYER M3 ;
        RECT  47.124 0 47.142 0.144 ;
    END
  END di[350]
  PIN di[351]
    DIRECTION INPUT ;
    USE SIGNAL ;
    PORT
      LAYER M5 ;
        RECT  47.232 0 47.256 0.192 ;
    END
  END di[351]
  PIN di[352]
    DIRECTION INPUT ;
    USE SIGNAL ;
    PORT
      LAYER M3 ;
        RECT  47.34 0 47.358 0.144 ;
    END
  END di[352]
  PIN di[353]
    DIRECTION INPUT ;
    USE SIGNAL ;
    PORT
      LAYER M5 ;
        RECT  47.472 0 47.496 0.192 ;
    END
  END di[353]
  PIN di[354]
    DIRECTION INPUT ;
    USE SIGNAL ;
    PORT
      LAYER M3 ;
        RECT  47.592 0 47.61 0.144 ;
    END
  END di[354]
  PIN di[355]
    DIRECTION INPUT ;
    USE SIGNAL ;
    PORT
      LAYER M5 ;
        RECT  47.712 0 47.736 0.192 ;
    END
  END di[355]
  PIN di[356]
    DIRECTION INPUT ;
    USE SIGNAL ;
    PORT
      LAYER M3 ;
        RECT  47.844 0 47.862 0.144 ;
    END
  END di[356]
  PIN di[357]
    DIRECTION INPUT ;
    USE SIGNAL ;
    PORT
      LAYER M5 ;
        RECT  47.952 0 47.976 0.192 ;
    END
  END di[357]
  PIN di[358]
    DIRECTION INPUT ;
    USE SIGNAL ;
    PORT
      LAYER M3 ;
        RECT  48.096 0 48.114 0.144 ;
    END
  END di[358]
  PIN di[359]
    DIRECTION INPUT ;
    USE SIGNAL ;
    PORT
      LAYER M5 ;
        RECT  48.192 0 48.216 0.192 ;
    END
  END di[359]
  PIN di[35]
    DIRECTION INPUT ;
    USE SIGNAL ;
    PORT
      LAYER M5 ;
        RECT  8.64 0 8.664 0.192 ;
    END
  END di[35]
  PIN di[360]
    DIRECTION INPUT ;
    USE SIGNAL ;
    PORT
      LAYER M3 ;
        RECT  48.312 0 48.33 0.144 ;
    END
  END di[360]
  PIN di[361]
    DIRECTION INPUT ;
    USE SIGNAL ;
    PORT
      LAYER M5 ;
        RECT  48.432 0 48.456 0.192 ;
    END
  END di[361]
  PIN di[362]
    DIRECTION INPUT ;
    USE SIGNAL ;
    PORT
      LAYER M3 ;
        RECT  48.564 0 48.582 0.144 ;
    END
  END di[362]
  PIN di[363]
    DIRECTION INPUT ;
    USE SIGNAL ;
    PORT
      LAYER M5 ;
        RECT  48.672 0 48.696 0.192 ;
    END
  END di[363]
  PIN di[364]
    DIRECTION INPUT ;
    USE SIGNAL ;
    PORT
      LAYER M3 ;
        RECT  48.816 0 48.834 0.144 ;
    END
  END di[364]
  PIN di[365]
    DIRECTION INPUT ;
    USE SIGNAL ;
    PORT
      LAYER M5 ;
        RECT  48.96 0 48.984 0.192 ;
    END
  END di[365]
  PIN di[366]
    DIRECTION INPUT ;
    USE SIGNAL ;
    PORT
      LAYER M3 ;
        RECT  49.068 0 49.086 0.144 ;
    END
  END di[366]
  PIN di[367]
    DIRECTION INPUT ;
    USE SIGNAL ;
    PORT
      LAYER M5 ;
        RECT  49.2 0 49.224 0.192 ;
    END
  END di[367]
  PIN di[368]
    DIRECTION INPUT ;
    USE SIGNAL ;
    PORT
      LAYER M3 ;
        RECT  49.32 0 49.338 0.144 ;
    END
  END di[368]
  PIN di[369]
    DIRECTION INPUT ;
    USE SIGNAL ;
    PORT
      LAYER M5 ;
        RECT  49.44 0 49.464 0.192 ;
    END
  END di[369]
  PIN di[36]
    DIRECTION INPUT ;
    USE SIGNAL ;
    PORT
      LAYER M3 ;
        RECT  8.784 0 8.802 0.144 ;
    END
  END di[36]
  PIN di[370]
    DIRECTION INPUT ;
    USE SIGNAL ;
    PORT
      LAYER M3 ;
        RECT  49.536 0 49.554 0.144 ;
    END
  END di[370]
  PIN di[371]
    DIRECTION INPUT ;
    USE SIGNAL ;
    PORT
      LAYER M5 ;
        RECT  49.68 0 49.704 0.192 ;
    END
  END di[371]
  PIN di[372]
    DIRECTION INPUT ;
    USE SIGNAL ;
    PORT
      LAYER M3 ;
        RECT  49.788 0 49.806 0.144 ;
    END
  END di[372]
  PIN di[373]
    DIRECTION INPUT ;
    USE SIGNAL ;
    PORT
      LAYER M5 ;
        RECT  49.92 0 49.944 0.192 ;
    END
  END di[373]
  PIN di[374]
    DIRECTION INPUT ;
    USE SIGNAL ;
    PORT
      LAYER M3 ;
        RECT  50.04 0 50.058 0.144 ;
    END
  END di[374]
  PIN di[375]
    DIRECTION INPUT ;
    USE SIGNAL ;
    PORT
      LAYER M5 ;
        RECT  50.16 0 50.184 0.192 ;
    END
  END di[375]
  PIN di[376]
    DIRECTION INPUT ;
    USE SIGNAL ;
    PORT
      LAYER M3 ;
        RECT  50.292 0 50.31 0.144 ;
    END
  END di[376]
  PIN di[377]
    DIRECTION INPUT ;
    USE SIGNAL ;
    PORT
      LAYER M5 ;
        RECT  50.4 0 50.424 0.192 ;
    END
  END di[377]
  PIN di[378]
    DIRECTION INPUT ;
    USE SIGNAL ;
    PORT
      LAYER M3 ;
        RECT  50.544 0 50.562 0.144 ;
    END
  END di[378]
  PIN di[379]
    DIRECTION INPUT ;
    USE SIGNAL ;
    PORT
      LAYER M5 ;
        RECT  50.64 0 50.664 0.192 ;
    END
  END di[379]
  PIN di[37]
    DIRECTION INPUT ;
    USE SIGNAL ;
    PORT
      LAYER M5 ;
        RECT  8.88 0 8.904 0.192 ;
    END
  END di[37]
  PIN di[380]
    DIRECTION INPUT ;
    USE SIGNAL ;
    PORT
      LAYER M3 ;
        RECT  50.76 0 50.778 0.144 ;
    END
  END di[380]
  PIN di[381]
    DIRECTION INPUT ;
    USE SIGNAL ;
    PORT
      LAYER M5 ;
        RECT  50.88 0 50.904 0.192 ;
    END
  END di[381]
  PIN di[382]
    DIRECTION INPUT ;
    USE SIGNAL ;
    PORT
      LAYER M3 ;
        RECT  51.012 0 51.03 0.144 ;
    END
  END di[382]
  PIN di[383]
    DIRECTION INPUT ;
    USE SIGNAL ;
    PORT
      LAYER M5 ;
        RECT  51.12 0 51.144 0.192 ;
    END
  END di[383]
  PIN di[384]
    DIRECTION INPUT ;
    USE SIGNAL ;
    PORT
      LAYER M3 ;
        RECT  51.264 0 51.282 0.144 ;
    END
  END di[384]
  PIN di[385]
    DIRECTION INPUT ;
    USE SIGNAL ;
    PORT
      LAYER M5 ;
        RECT  51.36 0 51.384 0.192 ;
    END
  END di[385]
  PIN di[386]
    DIRECTION INPUT ;
    USE SIGNAL ;
    PORT
      LAYER M3 ;
        RECT  51.516 0 51.534 0.144 ;
    END
  END di[386]
  PIN di[387]
    DIRECTION INPUT ;
    USE SIGNAL ;
    PORT
      LAYER M5 ;
        RECT  51.6 0 51.624 0.192 ;
    END
  END di[387]
  PIN di[388]
    DIRECTION INPUT ;
    USE SIGNAL ;
    PORT
      LAYER M3 ;
        RECT  51.732 0 51.75 0.144 ;
    END
  END di[388]
  PIN di[389]
    DIRECTION INPUT ;
    USE SIGNAL ;
    PORT
      LAYER M5 ;
        RECT  51.888 0 51.912 0.192 ;
    END
  END di[389]
  PIN di[38]
    DIRECTION INPUT ;
    USE SIGNAL ;
    PORT
      LAYER M3 ;
        RECT  9 0 9.018 0.144 ;
    END
  END di[38]
  PIN di[390]
    DIRECTION INPUT ;
    USE SIGNAL ;
    PORT
      LAYER M3 ;
        RECT  51.984 0 52.002 0.144 ;
    END
  END di[390]
  PIN di[391]
    DIRECTION INPUT ;
    USE SIGNAL ;
    PORT
      LAYER M5 ;
        RECT  52.128 0 52.152 0.192 ;
    END
  END di[391]
  PIN di[392]
    DIRECTION INPUT ;
    USE SIGNAL ;
    PORT
      LAYER M3 ;
        RECT  52.236 0 52.254 0.144 ;
    END
  END di[392]
  PIN di[393]
    DIRECTION INPUT ;
    USE SIGNAL ;
    PORT
      LAYER M5 ;
        RECT  52.368 0 52.392 0.192 ;
    END
  END di[393]
  PIN di[394]
    DIRECTION INPUT ;
    USE SIGNAL ;
    PORT
      LAYER M3 ;
        RECT  52.488 0 52.506 0.144 ;
    END
  END di[394]
  PIN di[395]
    DIRECTION INPUT ;
    USE SIGNAL ;
    PORT
      LAYER M5 ;
        RECT  52.608 0 52.632 0.192 ;
    END
  END di[395]
  PIN di[396]
    DIRECTION INPUT ;
    USE SIGNAL ;
    PORT
      LAYER M3 ;
        RECT  52.74 0 52.758 0.144 ;
    END
  END di[396]
  PIN di[397]
    DIRECTION INPUT ;
    USE SIGNAL ;
    PORT
      LAYER M5 ;
        RECT  52.848 0 52.872 0.192 ;
    END
  END di[397]
  PIN di[398]
    DIRECTION INPUT ;
    USE SIGNAL ;
    PORT
      LAYER M3 ;
        RECT  52.956 0 52.974 0.144 ;
    END
  END di[398]
  PIN di[399]
    DIRECTION INPUT ;
    USE SIGNAL ;
    PORT
      LAYER M5 ;
        RECT  53.088 0 53.112 0.192 ;
    END
  END di[399]
  PIN di[39]
    DIRECTION INPUT ;
    USE SIGNAL ;
    PORT
      LAYER M5 ;
        RECT  9.12 0 9.144 0.192 ;
    END
  END di[39]
  PIN di[3]
    DIRECTION INPUT ;
    USE SIGNAL ;
    PORT
      LAYER M5 ;
        RECT  4.752 0 4.776 0.192 ;
    END
  END di[3]
  PIN di[400]
    DIRECTION INPUT ;
    USE SIGNAL ;
    PORT
      LAYER M3 ;
        RECT  53.208 0 53.226 0.144 ;
    END
  END di[400]
  PIN di[401]
    DIRECTION INPUT ;
    USE SIGNAL ;
    PORT
      LAYER M5 ;
        RECT  53.328 0 53.352 0.192 ;
    END
  END di[401]
  PIN di[402]
    DIRECTION INPUT ;
    USE SIGNAL ;
    PORT
      LAYER M3 ;
        RECT  53.46 0 53.478 0.144 ;
    END
  END di[402]
  PIN di[403]
    DIRECTION INPUT ;
    USE SIGNAL ;
    PORT
      LAYER M5 ;
        RECT  53.568 0 53.592 0.192 ;
    END
  END di[403]
  PIN di[404]
    DIRECTION INPUT ;
    USE SIGNAL ;
    PORT
      LAYER M3 ;
        RECT  53.712 0 53.73 0.144 ;
    END
  END di[404]
  PIN di[405]
    DIRECTION INPUT ;
    USE SIGNAL ;
    PORT
      LAYER M5 ;
        RECT  53.808 0 53.832 0.192 ;
    END
  END di[405]
  PIN di[406]
    DIRECTION INPUT ;
    USE SIGNAL ;
    PORT
      LAYER M3 ;
        RECT  53.964 0 53.982 0.144 ;
    END
  END di[406]
  PIN di[407]
    DIRECTION INPUT ;
    USE SIGNAL ;
    PORT
      LAYER M5 ;
        RECT  54.048 0 54.072 0.192 ;
    END
  END di[407]
  PIN di[408]
    DIRECTION INPUT ;
    USE SIGNAL ;
    PORT
      LAYER M3 ;
        RECT  54.18 0 54.198 0.144 ;
    END
  END di[408]
  PIN di[409]
    DIRECTION INPUT ;
    USE SIGNAL ;
    PORT
      LAYER M5 ;
        RECT  54.288 0 54.312 0.192 ;
    END
  END di[409]
  PIN di[40]
    DIRECTION INPUT ;
    USE SIGNAL ;
    PORT
      LAYER M3 ;
        RECT  9.252 0 9.27 0.144 ;
    END
  END di[40]
  PIN di[410]
    DIRECTION INPUT ;
    USE SIGNAL ;
    PORT
      LAYER M3 ;
        RECT  54.432 0 54.45 0.144 ;
    END
  END di[410]
  PIN di[411]
    DIRECTION INPUT ;
    USE SIGNAL ;
    PORT
      LAYER M5 ;
        RECT  54.576 0 54.6 0.192 ;
    END
  END di[411]
  PIN di[412]
    DIRECTION INPUT ;
    USE SIGNAL ;
    PORT
      LAYER M3 ;
        RECT  54.684 0 54.702 0.144 ;
    END
  END di[412]
  PIN di[413]
    DIRECTION INPUT ;
    USE SIGNAL ;
    PORT
      LAYER M5 ;
        RECT  54.816 0 54.84 0.192 ;
    END
  END di[413]
  PIN di[414]
    DIRECTION INPUT ;
    USE SIGNAL ;
    PORT
      LAYER M3 ;
        RECT  54.936 0 54.954 0.144 ;
    END
  END di[414]
  PIN di[415]
    DIRECTION INPUT ;
    USE SIGNAL ;
    PORT
      LAYER M5 ;
        RECT  55.056 0 55.08 0.192 ;
    END
  END di[415]
  PIN di[416]
    DIRECTION INPUT ;
    USE SIGNAL ;
    PORT
      LAYER M3 ;
        RECT  55.152 0 55.17 0.144 ;
    END
  END di[416]
  PIN di[417]
    DIRECTION INPUT ;
    USE SIGNAL ;
    PORT
      LAYER M5 ;
        RECT  55.296 0 55.32 0.192 ;
    END
  END di[417]
  PIN di[418]
    DIRECTION INPUT ;
    USE SIGNAL ;
    PORT
      LAYER M3 ;
        RECT  55.404 0 55.422 0.144 ;
    END
  END di[418]
  PIN di[419]
    DIRECTION INPUT ;
    USE SIGNAL ;
    PORT
      LAYER M5 ;
        RECT  55.536 0 55.56 0.192 ;
    END
  END di[419]
  PIN di[41]
    DIRECTION INPUT ;
    USE SIGNAL ;
    PORT
      LAYER M5 ;
        RECT  9.36 0 9.384 0.192 ;
    END
  END di[41]
  PIN di[420]
    DIRECTION INPUT ;
    USE SIGNAL ;
    PORT
      LAYER M3 ;
        RECT  55.656 0 55.674 0.144 ;
    END
  END di[420]
  PIN di[421]
    DIRECTION INPUT ;
    USE SIGNAL ;
    PORT
      LAYER M5 ;
        RECT  55.776 0 55.8 0.192 ;
    END
  END di[421]
  PIN di[422]
    DIRECTION INPUT ;
    USE SIGNAL ;
    PORT
      LAYER M3 ;
        RECT  55.908 0 55.926 0.144 ;
    END
  END di[422]
  PIN di[423]
    DIRECTION INPUT ;
    USE SIGNAL ;
    PORT
      LAYER M5 ;
        RECT  56.016 0 56.04 0.192 ;
    END
  END di[423]
  PIN di[424]
    DIRECTION INPUT ;
    USE SIGNAL ;
    PORT
      LAYER M3 ;
        RECT  56.16 0 56.178 0.144 ;
    END
  END di[424]
  PIN di[425]
    DIRECTION INPUT ;
    USE SIGNAL ;
    PORT
      LAYER M5 ;
        RECT  56.256 0 56.28 0.192 ;
    END
  END di[425]
  PIN di[426]
    DIRECTION INPUT ;
    USE SIGNAL ;
    PORT
      LAYER M3 ;
        RECT  56.376 0 56.394 0.144 ;
    END
  END di[426]
  PIN di[427]
    DIRECTION INPUT ;
    USE SIGNAL ;
    PORT
      LAYER M5 ;
        RECT  56.496 0 56.52 0.192 ;
    END
  END di[427]
  PIN di[428]
    DIRECTION INPUT ;
    USE SIGNAL ;
    PORT
      LAYER M3 ;
        RECT  56.628 0 56.646 0.144 ;
    END
  END di[428]
  PIN di[429]
    DIRECTION INPUT ;
    USE SIGNAL ;
    PORT
      LAYER M5 ;
        RECT  56.736 0 56.76 0.192 ;
    END
  END di[429]
  PIN di[42]
    DIRECTION INPUT ;
    USE SIGNAL ;
    PORT
      LAYER M3 ;
        RECT  9.504 0 9.522 0.144 ;
    END
  END di[42]
  PIN di[430]
    DIRECTION INPUT ;
    USE SIGNAL ;
    PORT
      LAYER M3 ;
        RECT  56.88 0 56.898 0.144 ;
    END
  END di[430]
  PIN di[431]
    DIRECTION INPUT ;
    USE SIGNAL ;
    PORT
      LAYER M5 ;
        RECT  56.976 0 57 0.192 ;
    END
  END di[431]
  PIN di[432]
    DIRECTION INPUT ;
    USE SIGNAL ;
    PORT
      LAYER M3 ;
        RECT  57.132 0 57.15 0.144 ;
    END
  END di[432]
  PIN di[433]
    DIRECTION INPUT ;
    USE SIGNAL ;
    PORT
      LAYER M5 ;
        RECT  57.264 0 57.288 0.192 ;
    END
  END di[433]
  PIN di[434]
    DIRECTION INPUT ;
    USE SIGNAL ;
    PORT
      LAYER M3 ;
        RECT  57.348 0 57.366 0.144 ;
    END
  END di[434]
  PIN di[435]
    DIRECTION INPUT ;
    USE SIGNAL ;
    PORT
      LAYER M5 ;
        RECT  57.504 0 57.528 0.192 ;
    END
  END di[435]
  PIN di[436]
    DIRECTION INPUT ;
    USE SIGNAL ;
    PORT
      LAYER M3 ;
        RECT  57.6 0 57.618 0.144 ;
    END
  END di[436]
  PIN di[437]
    DIRECTION INPUT ;
    USE SIGNAL ;
    PORT
      LAYER M5 ;
        RECT  57.744 0 57.768 0.192 ;
    END
  END di[437]
  PIN di[438]
    DIRECTION INPUT ;
    USE SIGNAL ;
    PORT
      LAYER M3 ;
        RECT  57.852 0 57.87 0.144 ;
    END
  END di[438]
  PIN di[439]
    DIRECTION INPUT ;
    USE SIGNAL ;
    PORT
      LAYER M5 ;
        RECT  57.984 0 58.008 0.192 ;
    END
  END di[439]
  PIN di[43]
    DIRECTION INPUT ;
    USE SIGNAL ;
    PORT
      LAYER M5 ;
        RECT  9.6 0 9.624 0.192 ;
    END
  END di[43]
  PIN di[440]
    DIRECTION INPUT ;
    USE SIGNAL ;
    PORT
      LAYER M3 ;
        RECT  58.104 0 58.122 0.144 ;
    END
  END di[440]
  PIN di[441]
    DIRECTION INPUT ;
    USE SIGNAL ;
    PORT
      LAYER M5 ;
        RECT  58.224 0 58.248 0.192 ;
    END
  END di[441]
  PIN di[442]
    DIRECTION INPUT ;
    USE SIGNAL ;
    PORT
      LAYER M3 ;
        RECT  58.356 0 58.374 0.144 ;
    END
  END di[442]
  PIN di[443]
    DIRECTION INPUT ;
    USE SIGNAL ;
    PORT
      LAYER M5 ;
        RECT  58.464 0 58.488 0.192 ;
    END
  END di[443]
  PIN di[444]
    DIRECTION INPUT ;
    USE SIGNAL ;
    PORT
      LAYER M3 ;
        RECT  58.572 0 58.59 0.144 ;
    END
  END di[444]
  PIN di[445]
    DIRECTION INPUT ;
    USE SIGNAL ;
    PORT
      LAYER M5 ;
        RECT  58.704 0 58.728 0.192 ;
    END
  END di[445]
  PIN di[446]
    DIRECTION INPUT ;
    USE SIGNAL ;
    PORT
      LAYER M3 ;
        RECT  58.824 0 58.842 0.144 ;
    END
  END di[446]
  PIN di[447]
    DIRECTION INPUT ;
    USE SIGNAL ;
    PORT
      LAYER M5 ;
        RECT  58.944 0 58.968 0.192 ;
    END
  END di[447]
  PIN di[448]
    DIRECTION INPUT ;
    USE SIGNAL ;
    PORT
      LAYER M3 ;
        RECT  59.076 0 59.094 0.144 ;
    END
  END di[448]
  PIN di[449]
    DIRECTION INPUT ;
    USE SIGNAL ;
    PORT
      LAYER M5 ;
        RECT  59.184 0 59.208 0.192 ;
    END
  END di[449]
  PIN di[44]
    DIRECTION INPUT ;
    USE SIGNAL ;
    PORT
      LAYER M3 ;
        RECT  9.756 0 9.774 0.144 ;
    END
  END di[44]
  PIN di[450]
    DIRECTION INPUT ;
    USE SIGNAL ;
    PORT
      LAYER M3 ;
        RECT  59.328 0 59.346 0.144 ;
    END
  END di[450]
  PIN di[451]
    DIRECTION INPUT ;
    USE SIGNAL ;
    PORT
      LAYER M5 ;
        RECT  59.424 0 59.448 0.192 ;
    END
  END di[451]
  PIN di[452]
    DIRECTION INPUT ;
    USE SIGNAL ;
    PORT
      LAYER M3 ;
        RECT  59.58 0 59.598 0.144 ;
    END
  END di[452]
  PIN di[453]
    DIRECTION INPUT ;
    USE SIGNAL ;
    PORT
      LAYER M5 ;
        RECT  59.664 0 59.688 0.192 ;
    END
  END di[453]
  PIN di[454]
    DIRECTION INPUT ;
    USE SIGNAL ;
    PORT
      LAYER M3 ;
        RECT  59.796 0 59.814 0.144 ;
    END
  END di[454]
  PIN di[455]
    DIRECTION INPUT ;
    USE SIGNAL ;
    PORT
      LAYER M5 ;
        RECT  59.904 0 59.928 0.192 ;
    END
  END di[455]
  PIN di[456]
    DIRECTION INPUT ;
    USE SIGNAL ;
    PORT
      LAYER M3 ;
        RECT  60.048 0 60.066 0.144 ;
    END
  END di[456]
  PIN di[457]
    DIRECTION INPUT ;
    USE SIGNAL ;
    PORT
      LAYER M5 ;
        RECT  60.192 0 60.216 0.192 ;
    END
  END di[457]
  PIN di[458]
    DIRECTION INPUT ;
    USE SIGNAL ;
    PORT
      LAYER M3 ;
        RECT  60.3 0 60.318 0.144 ;
    END
  END di[458]
  PIN di[459]
    DIRECTION INPUT ;
    USE SIGNAL ;
    PORT
      LAYER M5 ;
        RECT  60.432 0 60.456 0.192 ;
    END
  END di[459]
  PIN di[45]
    DIRECTION INPUT ;
    USE SIGNAL ;
    PORT
      LAYER M5 ;
        RECT  9.84 0 9.864 0.192 ;
    END
  END di[45]
  PIN di[460]
    DIRECTION INPUT ;
    USE SIGNAL ;
    PORT
      LAYER M3 ;
        RECT  60.552 0 60.57 0.144 ;
    END
  END di[460]
  PIN di[461]
    DIRECTION INPUT ;
    USE SIGNAL ;
    PORT
      LAYER M5 ;
        RECT  60.672 0 60.696 0.192 ;
    END
  END di[461]
  PIN di[462]
    DIRECTION INPUT ;
    USE SIGNAL ;
    PORT
      LAYER M3 ;
        RECT  60.768 0 60.786 0.144 ;
    END
  END di[462]
  PIN di[463]
    DIRECTION INPUT ;
    USE SIGNAL ;
    PORT
      LAYER M5 ;
        RECT  60.912 0 60.936 0.192 ;
    END
  END di[463]
  PIN di[464]
    DIRECTION INPUT ;
    USE SIGNAL ;
    PORT
      LAYER M3 ;
        RECT  61.02 0 61.038 0.144 ;
    END
  END di[464]
  PIN di[465]
    DIRECTION INPUT ;
    USE SIGNAL ;
    PORT
      LAYER M5 ;
        RECT  61.152 0 61.176 0.192 ;
    END
  END di[465]
  PIN di[466]
    DIRECTION INPUT ;
    USE SIGNAL ;
    PORT
      LAYER M3 ;
        RECT  61.272 0 61.29 0.144 ;
    END
  END di[466]
  PIN di[467]
    DIRECTION INPUT ;
    USE SIGNAL ;
    PORT
      LAYER M5 ;
        RECT  61.392 0 61.416 0.192 ;
    END
  END di[467]
  PIN di[468]
    DIRECTION INPUT ;
    USE SIGNAL ;
    PORT
      LAYER M3 ;
        RECT  61.524 0 61.542 0.144 ;
    END
  END di[468]
  PIN di[469]
    DIRECTION INPUT ;
    USE SIGNAL ;
    PORT
      LAYER M5 ;
        RECT  61.632 0 61.656 0.192 ;
    END
  END di[469]
  PIN di[46]
    DIRECTION INPUT ;
    USE SIGNAL ;
    PORT
      LAYER M3 ;
        RECT  9.972 0 9.99 0.144 ;
    END
  END di[46]
  PIN di[470]
    DIRECTION INPUT ;
    USE SIGNAL ;
    PORT
      LAYER M3 ;
        RECT  61.776 0 61.794 0.144 ;
    END
  END di[470]
  PIN di[471]
    DIRECTION INPUT ;
    USE SIGNAL ;
    PORT
      LAYER M5 ;
        RECT  61.872 0 61.896 0.192 ;
    END
  END di[471]
  PIN di[472]
    DIRECTION INPUT ;
    USE SIGNAL ;
    PORT
      LAYER M3 ;
        RECT  61.992 0 62.01 0.144 ;
    END
  END di[472]
  PIN di[473]
    DIRECTION INPUT ;
    USE SIGNAL ;
    PORT
      LAYER M5 ;
        RECT  62.112 0 62.136 0.192 ;
    END
  END di[473]
  PIN di[474]
    DIRECTION INPUT ;
    USE SIGNAL ;
    PORT
      LAYER M3 ;
        RECT  62.244 0 62.262 0.144 ;
    END
  END di[474]
  PIN di[475]
    DIRECTION INPUT ;
    USE SIGNAL ;
    PORT
      LAYER M5 ;
        RECT  62.352 0 62.376 0.192 ;
    END
  END di[475]
  PIN di[476]
    DIRECTION INPUT ;
    USE SIGNAL ;
    PORT
      LAYER M3 ;
        RECT  62.496 0 62.514 0.144 ;
    END
  END di[476]
  PIN di[477]
    DIRECTION INPUT ;
    USE SIGNAL ;
    PORT
      LAYER M5 ;
        RECT  62.592 0 62.616 0.192 ;
    END
  END di[477]
  PIN di[478]
    DIRECTION INPUT ;
    USE SIGNAL ;
    PORT
      LAYER M3 ;
        RECT  62.748 0 62.766 0.144 ;
    END
  END di[478]
  PIN di[479]
    DIRECTION INPUT ;
    USE SIGNAL ;
    PORT
      LAYER M5 ;
        RECT  62.88 0 62.904 0.192 ;
    END
  END di[479]
  PIN di[47]
    DIRECTION INPUT ;
    USE SIGNAL ;
    PORT
      LAYER M5 ;
        RECT  10.128 0 10.152 0.192 ;
    END
  END di[47]
  PIN di[480]
    DIRECTION INPUT ;
    USE SIGNAL ;
    PORT
      LAYER M3 ;
        RECT  63 0 63.018 0.144 ;
    END
  END di[480]
  PIN di[481]
    DIRECTION INPUT ;
    USE SIGNAL ;
    PORT
      LAYER M5 ;
        RECT  63.12 0 63.144 0.192 ;
    END
  END di[481]
  PIN di[482]
    DIRECTION INPUT ;
    USE SIGNAL ;
    PORT
      LAYER M3 ;
        RECT  63.216 0 63.234 0.144 ;
    END
  END di[482]
  PIN di[483]
    DIRECTION INPUT ;
    USE SIGNAL ;
    PORT
      LAYER M5 ;
        RECT  63.36 0 63.384 0.192 ;
    END
  END di[483]
  PIN di[484]
    DIRECTION INPUT ;
    USE SIGNAL ;
    PORT
      LAYER M3 ;
        RECT  63.468 0 63.486 0.144 ;
    END
  END di[484]
  PIN di[485]
    DIRECTION INPUT ;
    USE SIGNAL ;
    PORT
      LAYER M5 ;
        RECT  63.6 0 63.624 0.192 ;
    END
  END di[485]
  PIN di[486]
    DIRECTION INPUT ;
    USE SIGNAL ;
    PORT
      LAYER M3 ;
        RECT  63.72 0 63.738 0.144 ;
    END
  END di[486]
  PIN di[487]
    DIRECTION INPUT ;
    USE SIGNAL ;
    PORT
      LAYER M5 ;
        RECT  63.84 0 63.864 0.192 ;
    END
  END di[487]
  PIN di[488]
    DIRECTION INPUT ;
    USE SIGNAL ;
    PORT
      LAYER M3 ;
        RECT  63.972 0 63.99 0.144 ;
    END
  END di[488]
  PIN di[489]
    DIRECTION INPUT ;
    USE SIGNAL ;
    PORT
      LAYER M5 ;
        RECT  64.08 0 64.104 0.192 ;
    END
  END di[489]
  PIN di[48]
    DIRECTION INPUT ;
    USE SIGNAL ;
    PORT
      LAYER M3 ;
        RECT  10.224 0 10.242 0.144 ;
    END
  END di[48]
  PIN di[490]
    DIRECTION INPUT ;
    USE SIGNAL ;
    PORT
      LAYER M3 ;
        RECT  64.188 0 64.206 0.144 ;
    END
  END di[490]
  PIN di[491]
    DIRECTION INPUT ;
    USE SIGNAL ;
    PORT
      LAYER M5 ;
        RECT  64.32 0 64.344 0.192 ;
    END
  END di[491]
  PIN di[492]
    DIRECTION INPUT ;
    USE SIGNAL ;
    PORT
      LAYER M3 ;
        RECT  64.44 0 64.458 0.144 ;
    END
  END di[492]
  PIN di[493]
    DIRECTION INPUT ;
    USE SIGNAL ;
    PORT
      LAYER M5 ;
        RECT  64.56 0 64.584 0.192 ;
    END
  END di[493]
  PIN di[494]
    DIRECTION INPUT ;
    USE SIGNAL ;
    PORT
      LAYER M3 ;
        RECT  64.692 0 64.71 0.144 ;
    END
  END di[494]
  PIN di[495]
    DIRECTION INPUT ;
    USE SIGNAL ;
    PORT
      LAYER M5 ;
        RECT  64.8 0 64.824 0.192 ;
    END
  END di[495]
  PIN di[496]
    DIRECTION INPUT ;
    USE SIGNAL ;
    PORT
      LAYER M3 ;
        RECT  64.944 0 64.962 0.144 ;
    END
  END di[496]
  PIN di[497]
    DIRECTION INPUT ;
    USE SIGNAL ;
    PORT
      LAYER M5 ;
        RECT  65.04 0 65.064 0.192 ;
    END
  END di[497]
  PIN di[498]
    DIRECTION INPUT ;
    USE SIGNAL ;
    PORT
      LAYER M3 ;
        RECT  65.196 0 65.214 0.144 ;
    END
  END di[498]
  PIN di[499]
    DIRECTION INPUT ;
    USE SIGNAL ;
    PORT
      LAYER M5 ;
        RECT  65.28 0 65.304 0.192 ;
    END
  END di[499]
  PIN di[49]
    DIRECTION INPUT ;
    USE SIGNAL ;
    PORT
      LAYER M5 ;
        RECT  10.368 0 10.392 0.192 ;
    END
  END di[49]
  PIN di[4]
    DIRECTION INPUT ;
    USE SIGNAL ;
    PORT
      LAYER M3 ;
        RECT  4.86 0 4.878 0.144 ;
    END
  END di[4]
  PIN di[500]
    DIRECTION INPUT ;
    USE SIGNAL ;
    PORT
      LAYER M3 ;
        RECT  65.412 0 65.43 0.144 ;
    END
  END di[500]
  PIN di[501]
    DIRECTION INPUT ;
    USE SIGNAL ;
    PORT
      LAYER M5 ;
        RECT  65.52 0 65.544 0.192 ;
    END
  END di[501]
  PIN di[502]
    DIRECTION INPUT ;
    USE SIGNAL ;
    PORT
      LAYER M3 ;
        RECT  65.664 0 65.682 0.144 ;
    END
  END di[502]
  PIN di[503]
    DIRECTION INPUT ;
    USE SIGNAL ;
    PORT
      LAYER M5 ;
        RECT  65.808 0 65.832 0.192 ;
    END
  END di[503]
  PIN di[504]
    DIRECTION INPUT ;
    USE SIGNAL ;
    PORT
      LAYER M3 ;
        RECT  65.916 0 65.934 0.144 ;
    END
  END di[504]
  PIN di[505]
    DIRECTION INPUT ;
    USE SIGNAL ;
    PORT
      LAYER M5 ;
        RECT  66.048 0 66.072 0.192 ;
    END
  END di[505]
  PIN di[506]
    DIRECTION INPUT ;
    USE SIGNAL ;
    PORT
      LAYER M3 ;
        RECT  66.168 0 66.186 0.144 ;
    END
  END di[506]
  PIN di[507]
    DIRECTION INPUT ;
    USE SIGNAL ;
    PORT
      LAYER M5 ;
        RECT  66.288 0 66.312 0.192 ;
    END
  END di[507]
  PIN di[508]
    DIRECTION INPUT ;
    USE SIGNAL ;
    PORT
      LAYER M3 ;
        RECT  66.384 0 66.402 0.144 ;
    END
  END di[508]
  PIN di[509]
    DIRECTION INPUT ;
    USE SIGNAL ;
    PORT
      LAYER M5 ;
        RECT  66.528 0 66.552 0.192 ;
    END
  END di[509]
  PIN di[50]
    DIRECTION INPUT ;
    USE SIGNAL ;
    PORT
      LAYER M3 ;
        RECT  10.476 0 10.494 0.144 ;
    END
  END di[50]
  PIN di[510]
    DIRECTION INPUT ;
    USE SIGNAL ;
    PORT
      LAYER M3 ;
        RECT  66.636 0 66.654 0.144 ;
    END
  END di[510]
  PIN di[511]
    DIRECTION INPUT ;
    USE SIGNAL ;
    PORT
      LAYER M5 ;
        RECT  66.768 0 66.792 0.192 ;
    END
  END di[511]
  PIN di[512]
    DIRECTION INPUT ;
    USE SIGNAL ;
    PORT
      LAYER M3 ;
        RECT  66.888 0 66.906 0.144 ;
    END
  END di[512]
  PIN di[51]
    DIRECTION INPUT ;
    USE SIGNAL ;
    PORT
      LAYER M5 ;
        RECT  10.608 0 10.632 0.192 ;
    END
  END di[51]
  PIN di[52]
    DIRECTION INPUT ;
    USE SIGNAL ;
    PORT
      LAYER M3 ;
        RECT  10.728 0 10.746 0.144 ;
    END
  END di[52]
  PIN di[53]
    DIRECTION INPUT ;
    USE SIGNAL ;
    PORT
      LAYER M5 ;
        RECT  10.848 0 10.872 0.192 ;
    END
  END di[53]
  PIN di[54]
    DIRECTION INPUT ;
    USE SIGNAL ;
    PORT
      LAYER M3 ;
        RECT  10.98 0 10.998 0.144 ;
    END
  END di[54]
  PIN di[55]
    DIRECTION INPUT ;
    USE SIGNAL ;
    PORT
      LAYER M5 ;
        RECT  11.088 0 11.112 0.192 ;
    END
  END di[55]
  PIN di[56]
    DIRECTION INPUT ;
    USE SIGNAL ;
    PORT
      LAYER M3 ;
        RECT  11.196 0 11.214 0.144 ;
    END
  END di[56]
  PIN di[57]
    DIRECTION INPUT ;
    USE SIGNAL ;
    PORT
      LAYER M5 ;
        RECT  11.328 0 11.352 0.192 ;
    END
  END di[57]
  PIN di[58]
    DIRECTION INPUT ;
    USE SIGNAL ;
    PORT
      LAYER M3 ;
        RECT  11.448 0 11.466 0.144 ;
    END
  END di[58]
  PIN di[59]
    DIRECTION INPUT ;
    USE SIGNAL ;
    PORT
      LAYER M5 ;
        RECT  11.568 0 11.592 0.192 ;
    END
  END di[59]
  PIN di[5]
    DIRECTION INPUT ;
    USE SIGNAL ;
    PORT
      LAYER M5 ;
        RECT  4.992 0 5.016 0.192 ;
    END
  END di[5]
  PIN di[60]
    DIRECTION INPUT ;
    USE SIGNAL ;
    PORT
      LAYER M3 ;
        RECT  11.7 0 11.718 0.144 ;
    END
  END di[60]
  PIN di[61]
    DIRECTION INPUT ;
    USE SIGNAL ;
    PORT
      LAYER M5 ;
        RECT  11.808 0 11.832 0.192 ;
    END
  END di[61]
  PIN di[62]
    DIRECTION INPUT ;
    USE SIGNAL ;
    PORT
      LAYER M3 ;
        RECT  11.952 0 11.97 0.144 ;
    END
  END di[62]
  PIN di[63]
    DIRECTION INPUT ;
    USE SIGNAL ;
    PORT
      LAYER M5 ;
        RECT  12.048 0 12.072 0.192 ;
    END
  END di[63]
  PIN di[64]
    DIRECTION INPUT ;
    USE SIGNAL ;
    PORT
      LAYER M3 ;
        RECT  12.204 0 12.222 0.144 ;
    END
  END di[64]
  PIN di[65]
    DIRECTION INPUT ;
    USE SIGNAL ;
    PORT
      LAYER M5 ;
        RECT  12.288 0 12.312 0.192 ;
    END
  END di[65]
  PIN di[66]
    DIRECTION INPUT ;
    USE SIGNAL ;
    PORT
      LAYER M3 ;
        RECT  12.42 0 12.438 0.144 ;
    END
  END di[66]
  PIN di[67]
    DIRECTION INPUT ;
    USE SIGNAL ;
    PORT
      LAYER M5 ;
        RECT  12.528 0 12.552 0.192 ;
    END
  END di[67]
  PIN di[68]
    DIRECTION INPUT ;
    USE SIGNAL ;
    PORT
      LAYER M3 ;
        RECT  12.672 0 12.69 0.144 ;
    END
  END di[68]
  PIN di[69]
    DIRECTION INPUT ;
    USE SIGNAL ;
    PORT
      LAYER M5 ;
        RECT  12.816 0 12.84 0.192 ;
    END
  END di[69]
  PIN di[6]
    DIRECTION INPUT ;
    USE SIGNAL ;
    PORT
      LAYER M3 ;
        RECT  5.112 0 5.13 0.144 ;
    END
  END di[6]
  PIN di[70]
    DIRECTION INPUT ;
    USE SIGNAL ;
    PORT
      LAYER M3 ;
        RECT  12.924 0 12.942 0.144 ;
    END
  END di[70]
  PIN di[71]
    DIRECTION INPUT ;
    USE SIGNAL ;
    PORT
      LAYER M5 ;
        RECT  13.056 0 13.08 0.192 ;
    END
  END di[71]
  PIN di[72]
    DIRECTION INPUT ;
    USE SIGNAL ;
    PORT
      LAYER M3 ;
        RECT  13.176 0 13.194 0.144 ;
    END
  END di[72]
  PIN di[73]
    DIRECTION INPUT ;
    USE SIGNAL ;
    PORT
      LAYER M5 ;
        RECT  13.296 0 13.32 0.192 ;
    END
  END di[73]
  PIN di[74]
    DIRECTION INPUT ;
    USE SIGNAL ;
    PORT
      LAYER M3 ;
        RECT  13.392 0 13.41 0.144 ;
    END
  END di[74]
  PIN di[75]
    DIRECTION INPUT ;
    USE SIGNAL ;
    PORT
      LAYER M5 ;
        RECT  13.536 0 13.56 0.192 ;
    END
  END di[75]
  PIN di[76]
    DIRECTION INPUT ;
    USE SIGNAL ;
    PORT
      LAYER M3 ;
        RECT  13.644 0 13.662 0.144 ;
    END
  END di[76]
  PIN di[77]
    DIRECTION INPUT ;
    USE SIGNAL ;
    PORT
      LAYER M5 ;
        RECT  13.776 0 13.8 0.192 ;
    END
  END di[77]
  PIN di[78]
    DIRECTION INPUT ;
    USE SIGNAL ;
    PORT
      LAYER M3 ;
        RECT  13.896 0 13.914 0.144 ;
    END
  END di[78]
  PIN di[79]
    DIRECTION INPUT ;
    USE SIGNAL ;
    PORT
      LAYER M5 ;
        RECT  14.016 0 14.04 0.192 ;
    END
  END di[79]
  PIN di[7]
    DIRECTION INPUT ;
    USE SIGNAL ;
    PORT
      LAYER M5 ;
        RECT  5.232 0 5.256 0.192 ;
    END
  END di[7]
  PIN di[80]
    DIRECTION INPUT ;
    USE SIGNAL ;
    PORT
      LAYER M3 ;
        RECT  14.148 0 14.166 0.144 ;
    END
  END di[80]
  PIN di[81]
    DIRECTION INPUT ;
    USE SIGNAL ;
    PORT
      LAYER M5 ;
        RECT  14.256 0 14.28 0.192 ;
    END
  END di[81]
  PIN di[82]
    DIRECTION INPUT ;
    USE SIGNAL ;
    PORT
      LAYER M3 ;
        RECT  14.4 0 14.418 0.144 ;
    END
  END di[82]
  PIN di[83]
    DIRECTION INPUT ;
    USE SIGNAL ;
    PORT
      LAYER M5 ;
        RECT  14.496 0 14.52 0.192 ;
    END
  END di[83]
  PIN di[84]
    DIRECTION INPUT ;
    USE SIGNAL ;
    PORT
      LAYER M3 ;
        RECT  14.616 0 14.634 0.144 ;
    END
  END di[84]
  PIN di[85]
    DIRECTION INPUT ;
    USE SIGNAL ;
    PORT
      LAYER M5 ;
        RECT  14.736 0 14.76 0.192 ;
    END
  END di[85]
  PIN di[86]
    DIRECTION INPUT ;
    USE SIGNAL ;
    PORT
      LAYER M3 ;
        RECT  14.868 0 14.886 0.144 ;
    END
  END di[86]
  PIN di[87]
    DIRECTION INPUT ;
    USE SIGNAL ;
    PORT
      LAYER M5 ;
        RECT  14.976 0 15 0.192 ;
    END
  END di[87]
  PIN di[88]
    DIRECTION INPUT ;
    USE SIGNAL ;
    PORT
      LAYER M3 ;
        RECT  15.12 0 15.138 0.144 ;
    END
  END di[88]
  PIN di[89]
    DIRECTION INPUT ;
    USE SIGNAL ;
    PORT
      LAYER M5 ;
        RECT  15.216 0 15.24 0.192 ;
    END
  END di[89]
  PIN di[8]
    DIRECTION INPUT ;
    USE SIGNAL ;
    PORT
      LAYER M3 ;
        RECT  5.364 0 5.382 0.144 ;
    END
  END di[8]
  PIN di[90]
    DIRECTION INPUT ;
    USE SIGNAL ;
    PORT
      LAYER M3 ;
        RECT  15.372 0 15.39 0.144 ;
    END
  END di[90]
  PIN di[91]
    DIRECTION INPUT ;
    USE SIGNAL ;
    PORT
      LAYER M5 ;
        RECT  15.504 0 15.528 0.192 ;
    END
  END di[91]
  PIN di[92]
    DIRECTION INPUT ;
    USE SIGNAL ;
    PORT
      LAYER M3 ;
        RECT  15.588 0 15.606 0.144 ;
    END
  END di[92]
  PIN di[93]
    DIRECTION INPUT ;
    USE SIGNAL ;
    PORT
      LAYER M5 ;
        RECT  15.744 0 15.768 0.192 ;
    END
  END di[93]
  PIN di[94]
    DIRECTION INPUT ;
    USE SIGNAL ;
    PORT
      LAYER M3 ;
        RECT  15.84 0 15.858 0.144 ;
    END
  END di[94]
  PIN di[95]
    DIRECTION INPUT ;
    USE SIGNAL ;
    PORT
      LAYER M5 ;
        RECT  15.984 0 16.008 0.192 ;
    END
  END di[95]
  PIN di[96]
    DIRECTION INPUT ;
    USE SIGNAL ;
    PORT
      LAYER M3 ;
        RECT  16.092 0 16.11 0.144 ;
    END
  END di[96]
  PIN di[97]
    DIRECTION INPUT ;
    USE SIGNAL ;
    PORT
      LAYER M5 ;
        RECT  16.224 0 16.248 0.192 ;
    END
  END di[97]
  PIN di[98]
    DIRECTION INPUT ;
    USE SIGNAL ;
    PORT
      LAYER M3 ;
        RECT  16.344 0 16.362 0.144 ;
    END
  END di[98]
  PIN di[99]
    DIRECTION INPUT ;
    USE SIGNAL ;
    PORT
      LAYER M5 ;
        RECT  16.464 0 16.488 0.192 ;
    END
  END di[99]
  PIN di[9]
    DIRECTION INPUT ;
    USE SIGNAL ;
    PORT
      LAYER M5 ;
        RECT  5.472 0 5.496 0.192 ;
    END
  END di[9]
  PIN dq[0]
    DIRECTION OUTPUT ;
    USE SIGNAL ;
    PORT
      LAYER M3 ;
        RECT  4.356 36.576 4.374 36.72 ;
    END
  END dq[0]
  PIN dq[100]
    DIRECTION OUTPUT ;
    USE SIGNAL ;
    PORT
      LAYER M3 ;
        RECT  16.596 36.576 16.614 36.72 ;
    END
  END dq[100]
  PIN dq[101]
    DIRECTION OUTPUT ;
    USE SIGNAL ;
    PORT
      LAYER M5 ;
        RECT  16.704 36.528 16.728 36.72 ;
    END
  END dq[101]
  PIN dq[102]
    DIRECTION OUTPUT ;
    USE SIGNAL ;
    PORT
      LAYER M3 ;
        RECT  16.812 36.576 16.83 36.72 ;
    END
  END dq[102]
  PIN dq[103]
    DIRECTION OUTPUT ;
    USE SIGNAL ;
    PORT
      LAYER M5 ;
        RECT  16.944 36.528 16.968 36.72 ;
    END
  END dq[103]
  PIN dq[104]
    DIRECTION OUTPUT ;
    USE SIGNAL ;
    PORT
      LAYER M3 ;
        RECT  17.064 36.576 17.082 36.72 ;
    END
  END dq[104]
  PIN dq[105]
    DIRECTION OUTPUT ;
    USE SIGNAL ;
    PORT
      LAYER M5 ;
        RECT  17.184 36.528 17.208 36.72 ;
    END
  END dq[105]
  PIN dq[106]
    DIRECTION OUTPUT ;
    USE SIGNAL ;
    PORT
      LAYER M3 ;
        RECT  17.316 36.576 17.334 36.72 ;
    END
  END dq[106]
  PIN dq[107]
    DIRECTION OUTPUT ;
    USE SIGNAL ;
    PORT
      LAYER M5 ;
        RECT  17.424 36.528 17.448 36.72 ;
    END
  END dq[107]
  PIN dq[108]
    DIRECTION OUTPUT ;
    USE SIGNAL ;
    PORT
      LAYER M3 ;
        RECT  17.568 36.576 17.586 36.72 ;
    END
  END dq[108]
  PIN dq[109]
    DIRECTION OUTPUT ;
    USE SIGNAL ;
    PORT
      LAYER M5 ;
        RECT  17.664 36.528 17.688 36.72 ;
    END
  END dq[109]
  PIN dq[10]
    DIRECTION OUTPUT ;
    USE SIGNAL ;
    PORT
      LAYER M3 ;
        RECT  5.58 36.576 5.598 36.72 ;
    END
  END dq[10]
  PIN dq[110]
    DIRECTION OUTPUT ;
    USE SIGNAL ;
    PORT
      LAYER M3 ;
        RECT  17.82 36.576 17.838 36.72 ;
    END
  END dq[110]
  PIN dq[111]
    DIRECTION OUTPUT ;
    USE SIGNAL ;
    PORT
      LAYER M5 ;
        RECT  17.904 36.528 17.928 36.72 ;
    END
  END dq[111]
  PIN dq[112]
    DIRECTION OUTPUT ;
    USE SIGNAL ;
    PORT
      LAYER M3 ;
        RECT  18.036 36.576 18.054 36.72 ;
    END
  END dq[112]
  PIN dq[113]
    DIRECTION OUTPUT ;
    USE SIGNAL ;
    PORT
      LAYER M5 ;
        RECT  18.144 36.528 18.168 36.72 ;
    END
  END dq[113]
  PIN dq[114]
    DIRECTION OUTPUT ;
    USE SIGNAL ;
    PORT
      LAYER M3 ;
        RECT  18.288 36.576 18.306 36.72 ;
    END
  END dq[114]
  PIN dq[115]
    DIRECTION OUTPUT ;
    USE SIGNAL ;
    PORT
      LAYER M5 ;
        RECT  18.432 36.528 18.456 36.72 ;
    END
  END dq[115]
  PIN dq[116]
    DIRECTION OUTPUT ;
    USE SIGNAL ;
    PORT
      LAYER M3 ;
        RECT  18.54 36.576 18.558 36.72 ;
    END
  END dq[116]
  PIN dq[117]
    DIRECTION OUTPUT ;
    USE SIGNAL ;
    PORT
      LAYER M5 ;
        RECT  18.672 36.528 18.696 36.72 ;
    END
  END dq[117]
  PIN dq[118]
    DIRECTION OUTPUT ;
    USE SIGNAL ;
    PORT
      LAYER M3 ;
        RECT  18.792 36.576 18.81 36.72 ;
    END
  END dq[118]
  PIN dq[119]
    DIRECTION OUTPUT ;
    USE SIGNAL ;
    PORT
      LAYER M5 ;
        RECT  18.912 36.528 18.936 36.72 ;
    END
  END dq[119]
  PIN dq[11]
    DIRECTION OUTPUT ;
    USE SIGNAL ;
    PORT
      LAYER M5 ;
        RECT  5.712 36.528 5.736 36.72 ;
    END
  END dq[11]
  PIN dq[120]
    DIRECTION OUTPUT ;
    USE SIGNAL ;
    PORT
      LAYER M3 ;
        RECT  19.008 36.576 19.026 36.72 ;
    END
  END dq[120]
  PIN dq[121]
    DIRECTION OUTPUT ;
    USE SIGNAL ;
    PORT
      LAYER M5 ;
        RECT  19.152 36.528 19.176 36.72 ;
    END
  END dq[121]
  PIN dq[122]
    DIRECTION OUTPUT ;
    USE SIGNAL ;
    PORT
      LAYER M3 ;
        RECT  19.26 36.576 19.278 36.72 ;
    END
  END dq[122]
  PIN dq[123]
    DIRECTION OUTPUT ;
    USE SIGNAL ;
    PORT
      LAYER M5 ;
        RECT  19.392 36.528 19.416 36.72 ;
    END
  END dq[123]
  PIN dq[124]
    DIRECTION OUTPUT ;
    USE SIGNAL ;
    PORT
      LAYER M3 ;
        RECT  19.512 36.576 19.53 36.72 ;
    END
  END dq[124]
  PIN dq[125]
    DIRECTION OUTPUT ;
    USE SIGNAL ;
    PORT
      LAYER M5 ;
        RECT  19.632 36.528 19.656 36.72 ;
    END
  END dq[125]
  PIN dq[126]
    DIRECTION OUTPUT ;
    USE SIGNAL ;
    PORT
      LAYER M3 ;
        RECT  19.764 36.576 19.782 36.72 ;
    END
  END dq[126]
  PIN dq[127]
    DIRECTION OUTPUT ;
    USE SIGNAL ;
    PORT
      LAYER M5 ;
        RECT  19.872 36.528 19.896 36.72 ;
    END
  END dq[127]
  PIN dq[128]
    DIRECTION OUTPUT ;
    USE SIGNAL ;
    PORT
      LAYER M3 ;
        RECT  20.016 36.576 20.034 36.72 ;
    END
  END dq[128]
  PIN dq[129]
    DIRECTION OUTPUT ;
    USE SIGNAL ;
    PORT
      LAYER M5 ;
        RECT  20.112 36.528 20.136 36.72 ;
    END
  END dq[129]
  PIN dq[12]
    DIRECTION OUTPUT ;
    USE SIGNAL ;
    PORT
      LAYER M3 ;
        RECT  5.832 36.576 5.85 36.72 ;
    END
  END dq[12]
  PIN dq[130]
    DIRECTION OUTPUT ;
    USE SIGNAL ;
    PORT
      LAYER M3 ;
        RECT  20.232 36.576 20.25 36.72 ;
    END
  END dq[130]
  PIN dq[131]
    DIRECTION OUTPUT ;
    USE SIGNAL ;
    PORT
      LAYER M5 ;
        RECT  20.352 36.528 20.376 36.72 ;
    END
  END dq[131]
  PIN dq[132]
    DIRECTION OUTPUT ;
    USE SIGNAL ;
    PORT
      LAYER M3 ;
        RECT  20.484 36.576 20.502 36.72 ;
    END
  END dq[132]
  PIN dq[133]
    DIRECTION OUTPUT ;
    USE SIGNAL ;
    PORT
      LAYER M5 ;
        RECT  20.592 36.528 20.616 36.72 ;
    END
  END dq[133]
  PIN dq[134]
    DIRECTION OUTPUT ;
    USE SIGNAL ;
    PORT
      LAYER M3 ;
        RECT  20.736 36.576 20.754 36.72 ;
    END
  END dq[134]
  PIN dq[135]
    DIRECTION OUTPUT ;
    USE SIGNAL ;
    PORT
      LAYER M5 ;
        RECT  20.832 36.528 20.856 36.72 ;
    END
  END dq[135]
  PIN dq[136]
    DIRECTION OUTPUT ;
    USE SIGNAL ;
    PORT
      LAYER M3 ;
        RECT  20.988 36.576 21.006 36.72 ;
    END
  END dq[136]
  PIN dq[137]
    DIRECTION OUTPUT ;
    USE SIGNAL ;
    PORT
      LAYER M5 ;
        RECT  21.12 36.528 21.144 36.72 ;
    END
  END dq[137]
  PIN dq[138]
    DIRECTION OUTPUT ;
    USE SIGNAL ;
    PORT
      LAYER M3 ;
        RECT  21.24 36.576 21.258 36.72 ;
    END
  END dq[138]
  PIN dq[139]
    DIRECTION OUTPUT ;
    USE SIGNAL ;
    PORT
      LAYER M5 ;
        RECT  21.36 36.528 21.384 36.72 ;
    END
  END dq[139]
  PIN dq[13]
    DIRECTION OUTPUT ;
    USE SIGNAL ;
    PORT
      LAYER M5 ;
        RECT  5.952 36.528 5.976 36.72 ;
    END
  END dq[13]
  PIN dq[140]
    DIRECTION OUTPUT ;
    USE SIGNAL ;
    PORT
      LAYER M3 ;
        RECT  21.456 36.576 21.474 36.72 ;
    END
  END dq[140]
  PIN dq[141]
    DIRECTION OUTPUT ;
    USE SIGNAL ;
    PORT
      LAYER M5 ;
        RECT  21.6 36.528 21.624 36.72 ;
    END
  END dq[141]
  PIN dq[142]
    DIRECTION OUTPUT ;
    USE SIGNAL ;
    PORT
      LAYER M3 ;
        RECT  21.708 36.576 21.726 36.72 ;
    END
  END dq[142]
  PIN dq[143]
    DIRECTION OUTPUT ;
    USE SIGNAL ;
    PORT
      LAYER M5 ;
        RECT  21.84 36.528 21.864 36.72 ;
    END
  END dq[143]
  PIN dq[144]
    DIRECTION OUTPUT ;
    USE SIGNAL ;
    PORT
      LAYER M3 ;
        RECT  21.96 36.576 21.978 36.72 ;
    END
  END dq[144]
  PIN dq[145]
    DIRECTION OUTPUT ;
    USE SIGNAL ;
    PORT
      LAYER M5 ;
        RECT  22.08 36.528 22.104 36.72 ;
    END
  END dq[145]
  PIN dq[146]
    DIRECTION OUTPUT ;
    USE SIGNAL ;
    PORT
      LAYER M3 ;
        RECT  22.212 36.576 22.23 36.72 ;
    END
  END dq[146]
  PIN dq[147]
    DIRECTION OUTPUT ;
    USE SIGNAL ;
    PORT
      LAYER M5 ;
        RECT  22.32 36.528 22.344 36.72 ;
    END
  END dq[147]
  PIN dq[148]
    DIRECTION OUTPUT ;
    USE SIGNAL ;
    PORT
      LAYER M3 ;
        RECT  22.428 36.576 22.446 36.72 ;
    END
  END dq[148]
  PIN dq[149]
    DIRECTION OUTPUT ;
    USE SIGNAL ;
    PORT
      LAYER M5 ;
        RECT  22.56 36.528 22.584 36.72 ;
    END
  END dq[149]
  PIN dq[14]
    DIRECTION OUTPUT ;
    USE SIGNAL ;
    PORT
      LAYER M3 ;
        RECT  6.084 36.576 6.102 36.72 ;
    END
  END dq[14]
  PIN dq[150]
    DIRECTION OUTPUT ;
    USE SIGNAL ;
    PORT
      LAYER M3 ;
        RECT  22.68 36.576 22.698 36.72 ;
    END
  END dq[150]
  PIN dq[151]
    DIRECTION OUTPUT ;
    USE SIGNAL ;
    PORT
      LAYER M5 ;
        RECT  22.8 36.528 22.824 36.72 ;
    END
  END dq[151]
  PIN dq[152]
    DIRECTION OUTPUT ;
    USE SIGNAL ;
    PORT
      LAYER M3 ;
        RECT  22.932 36.576 22.95 36.72 ;
    END
  END dq[152]
  PIN dq[153]
    DIRECTION OUTPUT ;
    USE SIGNAL ;
    PORT
      LAYER M5 ;
        RECT  23.04 36.528 23.064 36.72 ;
    END
  END dq[153]
  PIN dq[154]
    DIRECTION OUTPUT ;
    USE SIGNAL ;
    PORT
      LAYER M3 ;
        RECT  23.184 36.576 23.202 36.72 ;
    END
  END dq[154]
  PIN dq[155]
    DIRECTION OUTPUT ;
    USE SIGNAL ;
    PORT
      LAYER M5 ;
        RECT  23.28 36.528 23.304 36.72 ;
    END
  END dq[155]
  PIN dq[156]
    DIRECTION OUTPUT ;
    USE SIGNAL ;
    PORT
      LAYER M3 ;
        RECT  23.436 36.576 23.454 36.72 ;
    END
  END dq[156]
  PIN dq[157]
    DIRECTION OUTPUT ;
    USE SIGNAL ;
    PORT
      LAYER M5 ;
        RECT  23.52 36.528 23.544 36.72 ;
    END
  END dq[157]
  PIN dq[158]
    DIRECTION OUTPUT ;
    USE SIGNAL ;
    PORT
      LAYER M3 ;
        RECT  23.652 36.576 23.67 36.72 ;
    END
  END dq[158]
  PIN dq[159]
    DIRECTION OUTPUT ;
    USE SIGNAL ;
    PORT
      LAYER M5 ;
        RECT  23.76 36.528 23.784 36.72 ;
    END
  END dq[159]
  PIN dq[15]
    DIRECTION OUTPUT ;
    USE SIGNAL ;
    PORT
      LAYER M5 ;
        RECT  6.192 36.528 6.216 36.72 ;
    END
  END dq[15]
  PIN dq[160]
    DIRECTION OUTPUT ;
    USE SIGNAL ;
    PORT
      LAYER M3 ;
        RECT  23.904 36.576 23.922 36.72 ;
    END
  END dq[160]
  PIN dq[161]
    DIRECTION OUTPUT ;
    USE SIGNAL ;
    PORT
      LAYER M5 ;
        RECT  24.048 36.528 24.072 36.72 ;
    END
  END dq[161]
  PIN dq[162]
    DIRECTION OUTPUT ;
    USE SIGNAL ;
    PORT
      LAYER M3 ;
        RECT  24.156 36.576 24.174 36.72 ;
    END
  END dq[162]
  PIN dq[163]
    DIRECTION OUTPUT ;
    USE SIGNAL ;
    PORT
      LAYER M5 ;
        RECT  24.288 36.528 24.312 36.72 ;
    END
  END dq[163]
  PIN dq[164]
    DIRECTION OUTPUT ;
    USE SIGNAL ;
    PORT
      LAYER M3 ;
        RECT  24.408 36.576 24.426 36.72 ;
    END
  END dq[164]
  PIN dq[165]
    DIRECTION OUTPUT ;
    USE SIGNAL ;
    PORT
      LAYER M5 ;
        RECT  24.528 36.528 24.552 36.72 ;
    END
  END dq[165]
  PIN dq[166]
    DIRECTION OUTPUT ;
    USE SIGNAL ;
    PORT
      LAYER M3 ;
        RECT  24.624 36.576 24.642 36.72 ;
    END
  END dq[166]
  PIN dq[167]
    DIRECTION OUTPUT ;
    USE SIGNAL ;
    PORT
      LAYER M5 ;
        RECT  24.768 36.528 24.792 36.72 ;
    END
  END dq[167]
  PIN dq[168]
    DIRECTION OUTPUT ;
    USE SIGNAL ;
    PORT
      LAYER M3 ;
        RECT  24.876 36.576 24.894 36.72 ;
    END
  END dq[168]
  PIN dq[169]
    DIRECTION OUTPUT ;
    USE SIGNAL ;
    PORT
      LAYER M5 ;
        RECT  25.008 36.528 25.032 36.72 ;
    END
  END dq[169]
  PIN dq[16]
    DIRECTION OUTPUT ;
    USE SIGNAL ;
    PORT
      LAYER M3 ;
        RECT  6.336 36.576 6.354 36.72 ;
    END
  END dq[16]
  PIN dq[170]
    DIRECTION OUTPUT ;
    USE SIGNAL ;
    PORT
      LAYER M3 ;
        RECT  25.128 36.576 25.146 36.72 ;
    END
  END dq[170]
  PIN dq[171]
    DIRECTION OUTPUT ;
    USE SIGNAL ;
    PORT
      LAYER M5 ;
        RECT  25.248 36.528 25.272 36.72 ;
    END
  END dq[171]
  PIN dq[172]
    DIRECTION OUTPUT ;
    USE SIGNAL ;
    PORT
      LAYER M3 ;
        RECT  25.38 36.576 25.398 36.72 ;
    END
  END dq[172]
  PIN dq[173]
    DIRECTION OUTPUT ;
    USE SIGNAL ;
    PORT
      LAYER M5 ;
        RECT  25.488 36.528 25.512 36.72 ;
    END
  END dq[173]
  PIN dq[174]
    DIRECTION OUTPUT ;
    USE SIGNAL ;
    PORT
      LAYER M3 ;
        RECT  25.632 36.576 25.65 36.72 ;
    END
  END dq[174]
  PIN dq[175]
    DIRECTION OUTPUT ;
    USE SIGNAL ;
    PORT
      LAYER M5 ;
        RECT  25.728 36.528 25.752 36.72 ;
    END
  END dq[175]
  PIN dq[176]
    DIRECTION OUTPUT ;
    USE SIGNAL ;
    PORT
      LAYER M3 ;
        RECT  25.848 36.576 25.866 36.72 ;
    END
  END dq[176]
  PIN dq[177]
    DIRECTION OUTPUT ;
    USE SIGNAL ;
    PORT
      LAYER M5 ;
        RECT  25.968 36.528 25.992 36.72 ;
    END
  END dq[177]
  PIN dq[178]
    DIRECTION OUTPUT ;
    USE SIGNAL ;
    PORT
      LAYER M3 ;
        RECT  26.1 36.576 26.118 36.72 ;
    END
  END dq[178]
  PIN dq[179]
    DIRECTION OUTPUT ;
    USE SIGNAL ;
    PORT
      LAYER M5 ;
        RECT  26.208 36.528 26.232 36.72 ;
    END
  END dq[179]
  PIN dq[17]
    DIRECTION OUTPUT ;
    USE SIGNAL ;
    PORT
      LAYER M5 ;
        RECT  6.432 36.528 6.456 36.72 ;
    END
  END dq[17]
  PIN dq[180]
    DIRECTION OUTPUT ;
    USE SIGNAL ;
    PORT
      LAYER M3 ;
        RECT  26.352 36.576 26.37 36.72 ;
    END
  END dq[180]
  PIN dq[181]
    DIRECTION OUTPUT ;
    USE SIGNAL ;
    PORT
      LAYER M5 ;
        RECT  26.448 36.528 26.472 36.72 ;
    END
  END dq[181]
  PIN dq[182]
    DIRECTION OUTPUT ;
    USE SIGNAL ;
    PORT
      LAYER M3 ;
        RECT  26.604 36.576 26.622 36.72 ;
    END
  END dq[182]
  PIN dq[183]
    DIRECTION OUTPUT ;
    USE SIGNAL ;
    PORT
      LAYER M5 ;
        RECT  26.736 36.528 26.76 36.72 ;
    END
  END dq[183]
  PIN dq[184]
    DIRECTION OUTPUT ;
    USE SIGNAL ;
    PORT
      LAYER M3 ;
        RECT  26.856 36.576 26.874 36.72 ;
    END
  END dq[184]
  PIN dq[185]
    DIRECTION OUTPUT ;
    USE SIGNAL ;
    PORT
      LAYER M5 ;
        RECT  26.976 36.528 27 36.72 ;
    END
  END dq[185]
  PIN dq[186]
    DIRECTION OUTPUT ;
    USE SIGNAL ;
    PORT
      LAYER M3 ;
        RECT  27.072 36.576 27.09 36.72 ;
    END
  END dq[186]
  PIN dq[187]
    DIRECTION OUTPUT ;
    USE SIGNAL ;
    PORT
      LAYER M5 ;
        RECT  27.216 36.528 27.24 36.72 ;
    END
  END dq[187]
  PIN dq[188]
    DIRECTION OUTPUT ;
    USE SIGNAL ;
    PORT
      LAYER M3 ;
        RECT  27.324 36.576 27.342 36.72 ;
    END
  END dq[188]
  PIN dq[189]
    DIRECTION OUTPUT ;
    USE SIGNAL ;
    PORT
      LAYER M5 ;
        RECT  27.456 36.528 27.48 36.72 ;
    END
  END dq[189]
  PIN dq[18]
    DIRECTION OUTPUT ;
    USE SIGNAL ;
    PORT
      LAYER M3 ;
        RECT  6.552 36.576 6.57 36.72 ;
    END
  END dq[18]
  PIN dq[190]
    DIRECTION OUTPUT ;
    USE SIGNAL ;
    PORT
      LAYER M3 ;
        RECT  27.576 36.576 27.594 36.72 ;
    END
  END dq[190]
  PIN dq[191]
    DIRECTION OUTPUT ;
    USE SIGNAL ;
    PORT
      LAYER M5 ;
        RECT  27.696 36.528 27.72 36.72 ;
    END
  END dq[191]
  PIN dq[192]
    DIRECTION OUTPUT ;
    USE SIGNAL ;
    PORT
      LAYER M3 ;
        RECT  27.828 36.576 27.846 36.72 ;
    END
    PORT
      LAYER M3 ;
        RECT  27.756 36.588 27.882 36.653 ;
    END
  END dq[192]
  PIN dq[193]
    DIRECTION OUTPUT ;
    USE SIGNAL ;
    PORT
      LAYER M5 ;
        RECT  27.936 36.528 27.96 36.72 ;
    END
  END dq[193]
  PIN dq[194]
    DIRECTION OUTPUT ;
    USE SIGNAL ;
    PORT
      LAYER M3 ;
        RECT  28.044 36.576 28.062 36.72 ;
    END
  END dq[194]
  PIN dq[195]
    DIRECTION OUTPUT ;
    USE SIGNAL ;
    PORT
      LAYER M5 ;
        RECT  28.176 36.528 28.2 36.72 ;
    END
  END dq[195]
  PIN dq[196]
    DIRECTION OUTPUT ;
    USE SIGNAL ;
    PORT
      LAYER M3 ;
        RECT  28.296 36.576 28.314 36.72 ;
    END
  END dq[196]
  PIN dq[197]
    DIRECTION OUTPUT ;
    USE SIGNAL ;
    PORT
      LAYER M5 ;
        RECT  28.416 36.528 28.44 36.72 ;
    END
  END dq[197]
  PIN dq[198]
    DIRECTION OUTPUT ;
    USE SIGNAL ;
    PORT
      LAYER M3 ;
        RECT  28.548 36.576 28.566 36.72 ;
    END
  END dq[198]
  PIN dq[199]
    DIRECTION OUTPUT ;
    USE SIGNAL ;
    PORT
      LAYER M5 ;
        RECT  28.656 36.528 28.68 36.72 ;
    END
  END dq[199]
  PIN dq[19]
    DIRECTION OUTPUT ;
    USE SIGNAL ;
    PORT
      LAYER M5 ;
        RECT  6.672 36.528 6.696 36.72 ;
    END
  END dq[19]
  PIN dq[1]
    DIRECTION OUTPUT ;
    USE SIGNAL ;
    PORT
      LAYER M5 ;
        RECT  4.512 36.528 4.536 36.72 ;
    END
  END dq[1]
  PIN dq[200]
    DIRECTION OUTPUT ;
    USE SIGNAL ;
    PORT
      LAYER M3 ;
        RECT  28.8 36.576 28.818 36.72 ;
    END
  END dq[200]
  PIN dq[201]
    DIRECTION OUTPUT ;
    USE SIGNAL ;
    PORT
      LAYER M5 ;
        RECT  28.896 36.528 28.92 36.72 ;
    END
  END dq[201]
  PIN dq[202]
    DIRECTION OUTPUT ;
    USE SIGNAL ;
    PORT
      LAYER M3 ;
        RECT  29.052 36.576 29.07 36.72 ;
    END
  END dq[202]
  PIN dq[203]
    DIRECTION OUTPUT ;
    USE SIGNAL ;
    PORT
      LAYER M5 ;
        RECT  29.136 36.528 29.16 36.72 ;
    END
  END dq[203]
  PIN dq[204]
    DIRECTION OUTPUT ;
    USE SIGNAL ;
    PORT
      LAYER M3 ;
        RECT  29.268 36.576 29.286 36.72 ;
    END
  END dq[204]
  PIN dq[205]
    DIRECTION OUTPUT ;
    USE SIGNAL ;
    PORT
      LAYER M5 ;
        RECT  29.424 36.528 29.448 36.72 ;
    END
  END dq[205]
  PIN dq[206]
    DIRECTION OUTPUT ;
    USE SIGNAL ;
    PORT
      LAYER M3 ;
        RECT  29.52 36.576 29.538 36.72 ;
    END
  END dq[206]
  PIN dq[207]
    DIRECTION OUTPUT ;
    USE SIGNAL ;
    PORT
      LAYER M5 ;
        RECT  29.664 36.528 29.688 36.72 ;
    END
  END dq[207]
  PIN dq[208]
    DIRECTION OUTPUT ;
    USE SIGNAL ;
    PORT
      LAYER M3 ;
        RECT  29.772 36.576 29.79 36.72 ;
    END
  END dq[208]
  PIN dq[209]
    DIRECTION OUTPUT ;
    USE SIGNAL ;
    PORT
      LAYER M5 ;
        RECT  29.904 36.528 29.928 36.72 ;
    END
  END dq[209]
  PIN dq[20]
    DIRECTION OUTPUT ;
    USE SIGNAL ;
    PORT
      LAYER M3 ;
        RECT  6.804 36.576 6.822 36.72 ;
    END
  END dq[20]
  PIN dq[210]
    DIRECTION OUTPUT ;
    USE SIGNAL ;
    PORT
      LAYER M3 ;
        RECT  30.024 36.576 30.042 36.72 ;
    END
  END dq[210]
  PIN dq[211]
    DIRECTION OUTPUT ;
    USE SIGNAL ;
    PORT
      LAYER M5 ;
        RECT  30.144 36.528 30.168 36.72 ;
    END
  END dq[211]
  PIN dq[212]
    DIRECTION OUTPUT ;
    USE SIGNAL ;
    PORT
      LAYER M3 ;
        RECT  30.276 36.576 30.294 36.72 ;
    END
  END dq[212]
  PIN dq[213]
    DIRECTION OUTPUT ;
    USE SIGNAL ;
    PORT
      LAYER M5 ;
        RECT  30.384 36.528 30.408 36.72 ;
    END
  END dq[213]
  PIN dq[214]
    DIRECTION OUTPUT ;
    USE SIGNAL ;
    PORT
      LAYER M3 ;
        RECT  30.492 36.576 30.51 36.72 ;
    END
  END dq[214]
  PIN dq[215]
    DIRECTION OUTPUT ;
    USE SIGNAL ;
    PORT
      LAYER M5 ;
        RECT  30.624 36.528 30.648 36.72 ;
    END
  END dq[215]
  PIN dq[216]
    DIRECTION OUTPUT ;
    USE SIGNAL ;
    PORT
      LAYER M3 ;
        RECT  30.744 36.576 30.762 36.72 ;
    END
  END dq[216]
  PIN dq[217]
    DIRECTION OUTPUT ;
    USE SIGNAL ;
    PORT
      LAYER M5 ;
        RECT  30.864 36.528 30.888 36.72 ;
    END
  END dq[217]
  PIN dq[218]
    DIRECTION OUTPUT ;
    USE SIGNAL ;
    PORT
      LAYER M3 ;
        RECT  30.996 36.576 31.014 36.72 ;
    END
  END dq[218]
  PIN dq[219]
    DIRECTION OUTPUT ;
    USE SIGNAL ;
    PORT
      LAYER M5 ;
        RECT  31.104 36.528 31.128 36.72 ;
    END
  END dq[219]
  PIN dq[21]
    DIRECTION OUTPUT ;
    USE SIGNAL ;
    PORT
      LAYER M5 ;
        RECT  6.912 36.528 6.936 36.72 ;
    END
  END dq[21]
  PIN dq[220]
    DIRECTION OUTPUT ;
    USE SIGNAL ;
    PORT
      LAYER M3 ;
        RECT  31.248 36.576 31.266 36.72 ;
    END
  END dq[220]
  PIN dq[221]
    DIRECTION OUTPUT ;
    USE SIGNAL ;
    PORT
      LAYER M5 ;
        RECT  31.344 36.528 31.368 36.72 ;
    END
  END dq[221]
  PIN dq[222]
    DIRECTION OUTPUT ;
    USE SIGNAL ;
    PORT
      LAYER M3 ;
        RECT  31.464 36.576 31.482 36.72 ;
    END
  END dq[222]
  PIN dq[223]
    DIRECTION OUTPUT ;
    USE SIGNAL ;
    PORT
      LAYER M5 ;
        RECT  31.584 36.528 31.608 36.72 ;
    END
  END dq[223]
  PIN dq[224]
    DIRECTION OUTPUT ;
    USE SIGNAL ;
    PORT
      LAYER M3 ;
        RECT  31.716 36.576 31.734 36.72 ;
    END
  END dq[224]
  PIN dq[225]
    DIRECTION OUTPUT ;
    USE SIGNAL ;
    PORT
      LAYER M5 ;
        RECT  31.824 36.528 31.848 36.72 ;
    END
  END dq[225]
  PIN dq[226]
    DIRECTION OUTPUT ;
    USE SIGNAL ;
    PORT
      LAYER M3 ;
        RECT  31.968 36.576 31.986 36.72 ;
    END
  END dq[226]
  PIN dq[227]
    DIRECTION OUTPUT ;
    USE SIGNAL ;
    PORT
      LAYER M5 ;
        RECT  32.064 36.528 32.088 36.72 ;
    END
  END dq[227]
  PIN dq[228]
    DIRECTION OUTPUT ;
    USE SIGNAL ;
    PORT
      LAYER M3 ;
        RECT  32.22 36.576 32.238 36.72 ;
    END
  END dq[228]
  PIN dq[229]
    DIRECTION OUTPUT ;
    USE SIGNAL ;
    PORT
      LAYER M5 ;
        RECT  32.352 36.528 32.376 36.72 ;
    END
  END dq[229]
  PIN dq[22]
    DIRECTION OUTPUT ;
    USE SIGNAL ;
    PORT
      LAYER M3 ;
        RECT  7.056 36.576 7.074 36.72 ;
    END
  END dq[22]
  PIN dq[230]
    DIRECTION OUTPUT ;
    USE SIGNAL ;
    PORT
      LAYER M3 ;
        RECT  32.472 36.576 32.49 36.72 ;
    END
  END dq[230]
  PIN dq[231]
    DIRECTION OUTPUT ;
    USE SIGNAL ;
    PORT
      LAYER M5 ;
        RECT  32.592 36.528 32.616 36.72 ;
    END
  END dq[231]
  PIN dq[232]
    DIRECTION OUTPUT ;
    USE SIGNAL ;
    PORT
      LAYER M3 ;
        RECT  32.688 36.576 32.706 36.72 ;
    END
  END dq[232]
  PIN dq[233]
    DIRECTION OUTPUT ;
    USE SIGNAL ;
    PORT
      LAYER M5 ;
        RECT  32.832 36.528 32.856 36.72 ;
    END
  END dq[233]
  PIN dq[234]
    DIRECTION OUTPUT ;
    USE SIGNAL ;
    PORT
      LAYER M3 ;
        RECT  32.94 36.576 32.958 36.72 ;
    END
  END dq[234]
  PIN dq[235]
    DIRECTION OUTPUT ;
    USE SIGNAL ;
    PORT
      LAYER M5 ;
        RECT  33.072 36.528 33.096 36.72 ;
    END
  END dq[235]
  PIN dq[236]
    DIRECTION OUTPUT ;
    USE SIGNAL ;
    PORT
      LAYER M3 ;
        RECT  33.192 36.576 33.21 36.72 ;
    END
  END dq[236]
  PIN dq[237]
    DIRECTION OUTPUT ;
    USE SIGNAL ;
    PORT
      LAYER M5 ;
        RECT  33.312 36.528 33.336 36.72 ;
    END
  END dq[237]
  PIN dq[238]
    DIRECTION OUTPUT ;
    USE SIGNAL ;
    PORT
      LAYER M3 ;
        RECT  33.444 36.576 33.462 36.72 ;
    END
  END dq[238]
  PIN dq[239]
    DIRECTION OUTPUT ;
    USE SIGNAL ;
    PORT
      LAYER M5 ;
        RECT  33.552 36.528 33.576 36.72 ;
    END
  END dq[239]
  PIN dq[23]
    DIRECTION OUTPUT ;
    USE SIGNAL ;
    PORT
      LAYER M5 ;
        RECT  7.2 36.528 7.224 36.72 ;
    END
  END dq[23]
  PIN dq[240]
    DIRECTION OUTPUT ;
    USE SIGNAL ;
    PORT
      LAYER M3 ;
        RECT  33.66 36.576 33.678 36.72 ;
    END
  END dq[240]
  PIN dq[241]
    DIRECTION OUTPUT ;
    USE SIGNAL ;
    PORT
      LAYER M5 ;
        RECT  33.792 36.528 33.816 36.72 ;
    END
  END dq[241]
  PIN dq[242]
    DIRECTION OUTPUT ;
    USE SIGNAL ;
    PORT
      LAYER M3 ;
        RECT  33.912 36.576 33.93 36.72 ;
    END
  END dq[242]
  PIN dq[243]
    DIRECTION OUTPUT ;
    USE SIGNAL ;
    PORT
      LAYER M5 ;
        RECT  34.032 36.528 34.056 36.72 ;
    END
  END dq[243]
  PIN dq[244]
    DIRECTION OUTPUT ;
    USE SIGNAL ;
    PORT
      LAYER M3 ;
        RECT  34.164 36.576 34.182 36.72 ;
    END
  END dq[244]
  PIN dq[245]
    DIRECTION OUTPUT ;
    USE SIGNAL ;
    PORT
      LAYER M5 ;
        RECT  34.272 36.528 34.296 36.72 ;
    END
  END dq[245]
  PIN dq[246]
    DIRECTION OUTPUT ;
    USE SIGNAL ;
    PORT
      LAYER M3 ;
        RECT  34.416 36.576 34.434 36.72 ;
    END
  END dq[246]
  PIN dq[247]
    DIRECTION OUTPUT ;
    USE SIGNAL ;
    PORT
      LAYER M5 ;
        RECT  34.512 36.528 34.536 36.72 ;
    END
  END dq[247]
  PIN dq[248]
    DIRECTION OUTPUT ;
    USE SIGNAL ;
    PORT
      LAYER M3 ;
        RECT  34.668 36.576 34.686 36.72 ;
    END
  END dq[248]
  PIN dq[249]
    DIRECTION OUTPUT ;
    USE SIGNAL ;
    PORT
      LAYER M5 ;
        RECT  34.752 36.528 34.776 36.72 ;
    END
  END dq[249]
  PIN dq[24]
    DIRECTION OUTPUT ;
    USE SIGNAL ;
    PORT
      LAYER M3 ;
        RECT  7.308 36.576 7.326 36.72 ;
    END
  END dq[24]
  PIN dq[250]
    DIRECTION OUTPUT ;
    USE SIGNAL ;
    PORT
      LAYER M3 ;
        RECT  34.884 36.576 34.902 36.72 ;
    END
  END dq[250]
  PIN dq[251]
    DIRECTION OUTPUT ;
    USE SIGNAL ;
    PORT
      LAYER M5 ;
        RECT  35.04 36.528 35.064 36.72 ;
    END
  END dq[251]
  PIN dq[252]
    DIRECTION OUTPUT ;
    USE SIGNAL ;
    PORT
      LAYER M3 ;
        RECT  35.136 36.576 35.154 36.72 ;
    END
  END dq[252]
  PIN dq[253]
    DIRECTION OUTPUT ;
    USE SIGNAL ;
    PORT
      LAYER M5 ;
        RECT  35.28 36.528 35.304 36.72 ;
    END
  END dq[253]
  PIN dq[254]
    DIRECTION OUTPUT ;
    USE SIGNAL ;
    PORT
      LAYER M3 ;
        RECT  35.388 36.576 35.406 36.72 ;
    END
  END dq[254]
  PIN dq[255]
    DIRECTION OUTPUT ;
    USE SIGNAL ;
    PORT
      LAYER M5 ;
        RECT  35.52 36.528 35.544 36.72 ;
    END
  END dq[255]
  PIN dq[256]
    DIRECTION OUTPUT ;
    USE SIGNAL ;
    PORT
      LAYER M3 ;
        RECT  35.64 36.576 35.658 36.72 ;
    END
  END dq[256]
  PIN dq[257]
    DIRECTION OUTPUT ;
    USE SIGNAL ;
    PORT
      LAYER M5 ;
        RECT  35.76 36.528 35.784 36.72 ;
    END
  END dq[257]
  PIN dq[258]
    DIRECTION OUTPUT ;
    USE SIGNAL ;
    PORT
      LAYER M3 ;
        RECT  35.892 36.576 35.91 36.72 ;
    END
  END dq[258]
  PIN dq[259]
    DIRECTION OUTPUT ;
    USE SIGNAL ;
    PORT
      LAYER M5 ;
        RECT  36 36.528 36.024 36.72 ;
    END
  END dq[259]
  PIN dq[25]
    DIRECTION OUTPUT ;
    USE SIGNAL ;
    PORT
      LAYER M5 ;
        RECT  7.44 36.528 7.464 36.72 ;
    END
  END dq[25]
  PIN dq[260]
    DIRECTION OUTPUT ;
    USE SIGNAL ;
    PORT
      LAYER M3 ;
        RECT  36.108 36.576 36.126 36.72 ;
    END
  END dq[260]
  PIN dq[261]
    DIRECTION OUTPUT ;
    USE SIGNAL ;
    PORT
      LAYER M5 ;
        RECT  36.24 36.528 36.264 36.72 ;
    END
  END dq[261]
  PIN dq[262]
    DIRECTION OUTPUT ;
    USE SIGNAL ;
    PORT
      LAYER M3 ;
        RECT  36.36 36.576 36.378 36.72 ;
    END
  END dq[262]
  PIN dq[263]
    DIRECTION OUTPUT ;
    USE SIGNAL ;
    PORT
      LAYER M5 ;
        RECT  36.48 36.528 36.504 36.72 ;
    END
  END dq[263]
  PIN dq[264]
    DIRECTION OUTPUT ;
    USE SIGNAL ;
    PORT
      LAYER M3 ;
        RECT  36.612 36.576 36.63 36.72 ;
    END
  END dq[264]
  PIN dq[265]
    DIRECTION OUTPUT ;
    USE SIGNAL ;
    PORT
      LAYER M5 ;
        RECT  36.72 36.528 36.744 36.72 ;
    END
  END dq[265]
  PIN dq[266]
    DIRECTION OUTPUT ;
    USE SIGNAL ;
    PORT
      LAYER M3 ;
        RECT  36.864 36.576 36.882 36.72 ;
    END
  END dq[266]
  PIN dq[267]
    DIRECTION OUTPUT ;
    USE SIGNAL ;
    PORT
      LAYER M5 ;
        RECT  36.96 36.528 36.984 36.72 ;
    END
  END dq[267]
  PIN dq[268]
    DIRECTION OUTPUT ;
    USE SIGNAL ;
    PORT
      LAYER M3 ;
        RECT  37.08 36.576 37.098 36.72 ;
    END
  END dq[268]
  PIN dq[269]
    DIRECTION OUTPUT ;
    USE SIGNAL ;
    PORT
      LAYER M5 ;
        RECT  37.2 36.528 37.224 36.72 ;
    END
  END dq[269]
  PIN dq[26]
    DIRECTION OUTPUT ;
    USE SIGNAL ;
    PORT
      LAYER M3 ;
        RECT  7.56 36.576 7.578 36.72 ;
    END
  END dq[26]
  PIN dq[270]
    DIRECTION OUTPUT ;
    USE SIGNAL ;
    PORT
      LAYER M3 ;
        RECT  37.332 36.576 37.35 36.72 ;
    END
  END dq[270]
  PIN dq[271]
    DIRECTION OUTPUT ;
    USE SIGNAL ;
    PORT
      LAYER M5 ;
        RECT  37.44 36.528 37.464 36.72 ;
    END
  END dq[271]
  PIN dq[272]
    DIRECTION OUTPUT ;
    USE SIGNAL ;
    PORT
      LAYER M3 ;
        RECT  37.584 36.576 37.602 36.72 ;
    END
  END dq[272]
  PIN dq[273]
    DIRECTION OUTPUT ;
    USE SIGNAL ;
    PORT
      LAYER M5 ;
        RECT  37.68 36.528 37.704 36.72 ;
    END
  END dq[273]
  PIN dq[274]
    DIRECTION OUTPUT ;
    USE SIGNAL ;
    PORT
      LAYER M3 ;
        RECT  37.836 36.576 37.854 36.72 ;
    END
  END dq[274]
  PIN dq[275]
    DIRECTION OUTPUT ;
    USE SIGNAL ;
    PORT
      LAYER M5 ;
        RECT  37.968 36.528 37.992 36.72 ;
    END
  END dq[275]
  PIN dq[276]
    DIRECTION OUTPUT ;
    USE SIGNAL ;
    PORT
      LAYER M3 ;
        RECT  38.088 36.576 38.106 36.72 ;
    END
  END dq[276]
  PIN dq[277]
    DIRECTION OUTPUT ;
    USE SIGNAL ;
    PORT
      LAYER M5 ;
        RECT  38.208 36.528 38.232 36.72 ;
    END
  END dq[277]
  PIN dq[278]
    DIRECTION OUTPUT ;
    USE SIGNAL ;
    PORT
      LAYER M3 ;
        RECT  38.304 36.576 38.322 36.72 ;
    END
  END dq[278]
  PIN dq[279]
    DIRECTION OUTPUT ;
    USE SIGNAL ;
    PORT
      LAYER M5 ;
        RECT  38.448 36.528 38.472 36.72 ;
    END
  END dq[279]
  PIN dq[27]
    DIRECTION OUTPUT ;
    USE SIGNAL ;
    PORT
      LAYER M5 ;
        RECT  7.68 36.528 7.704 36.72 ;
    END
  END dq[27]
  PIN dq[280]
    DIRECTION OUTPUT ;
    USE SIGNAL ;
    PORT
      LAYER M3 ;
        RECT  38.556 36.576 38.574 36.72 ;
    END
  END dq[280]
  PIN dq[281]
    DIRECTION OUTPUT ;
    USE SIGNAL ;
    PORT
      LAYER M5 ;
        RECT  38.688 36.528 38.712 36.72 ;
    END
  END dq[281]
  PIN dq[282]
    DIRECTION OUTPUT ;
    USE SIGNAL ;
    PORT
      LAYER M3 ;
        RECT  38.808 36.576 38.826 36.72 ;
    END
  END dq[282]
  PIN dq[283]
    DIRECTION OUTPUT ;
    USE SIGNAL ;
    PORT
      LAYER M5 ;
        RECT  38.928 36.528 38.952 36.72 ;
    END
  END dq[283]
  PIN dq[284]
    DIRECTION OUTPUT ;
    USE SIGNAL ;
    PORT
      LAYER M3 ;
        RECT  39.06 36.576 39.078 36.72 ;
    END
  END dq[284]
  PIN dq[285]
    DIRECTION OUTPUT ;
    USE SIGNAL ;
    PORT
      LAYER M5 ;
        RECT  39.168 36.528 39.192 36.72 ;
    END
  END dq[285]
  PIN dq[286]
    DIRECTION OUTPUT ;
    USE SIGNAL ;
    PORT
      LAYER M3 ;
        RECT  39.312 36.576 39.33 36.72 ;
    END
  END dq[286]
  PIN dq[287]
    DIRECTION OUTPUT ;
    USE SIGNAL ;
    PORT
      LAYER M5 ;
        RECT  39.408 36.528 39.432 36.72 ;
    END
  END dq[287]
  PIN dq[288]
    DIRECTION OUTPUT ;
    USE SIGNAL ;
    PORT
      LAYER M3 ;
        RECT  39.528 36.576 39.546 36.72 ;
    END
  END dq[288]
  PIN dq[289]
    DIRECTION OUTPUT ;
    USE SIGNAL ;
    PORT
      LAYER M5 ;
        RECT  39.648 36.528 39.672 36.72 ;
    END
  END dq[289]
  PIN dq[28]
    DIRECTION OUTPUT ;
    USE SIGNAL ;
    PORT
      LAYER M3 ;
        RECT  7.776 36.576 7.794 36.72 ;
    END
  END dq[28]
  PIN dq[290]
    DIRECTION OUTPUT ;
    USE SIGNAL ;
    PORT
      LAYER M3 ;
        RECT  39.78 36.576 39.798 36.72 ;
    END
  END dq[290]
  PIN dq[291]
    DIRECTION OUTPUT ;
    USE SIGNAL ;
    PORT
      LAYER M5 ;
        RECT  39.888 36.528 39.912 36.72 ;
    END
  END dq[291]
  PIN dq[292]
    DIRECTION OUTPUT ;
    USE SIGNAL ;
    PORT
      LAYER M3 ;
        RECT  40.032 36.576 40.05 36.72 ;
    END
  END dq[292]
  PIN dq[293]
    DIRECTION OUTPUT ;
    USE SIGNAL ;
    PORT
      LAYER M5 ;
        RECT  40.128 36.528 40.152 36.72 ;
    END
  END dq[293]
  PIN dq[294]
    DIRECTION OUTPUT ;
    USE SIGNAL ;
    PORT
      LAYER M3 ;
        RECT  40.284 36.576 40.302 36.72 ;
    END
  END dq[294]
  PIN dq[295]
    DIRECTION OUTPUT ;
    USE SIGNAL ;
    PORT
      LAYER M5 ;
        RECT  40.368 36.528 40.392 36.72 ;
    END
  END dq[295]
  PIN dq[296]
    DIRECTION OUTPUT ;
    USE SIGNAL ;
    PORT
      LAYER M3 ;
        RECT  40.5 36.576 40.518 36.72 ;
    END
  END dq[296]
  PIN dq[297]
    DIRECTION OUTPUT ;
    USE SIGNAL ;
    PORT
      LAYER M5 ;
        RECT  40.656 36.528 40.68 36.72 ;
    END
  END dq[297]
  PIN dq[298]
    DIRECTION OUTPUT ;
    USE SIGNAL ;
    PORT
      LAYER M3 ;
        RECT  40.752 36.576 40.77 36.72 ;
    END
  END dq[298]
  PIN dq[299]
    DIRECTION OUTPUT ;
    USE SIGNAL ;
    PORT
      LAYER M5 ;
        RECT  40.896 36.528 40.92 36.72 ;
    END
  END dq[299]
  PIN dq[29]
    DIRECTION OUTPUT ;
    USE SIGNAL ;
    PORT
      LAYER M5 ;
        RECT  7.92 36.528 7.944 36.72 ;
    END
  END dq[29]
  PIN dq[2]
    DIRECTION OUTPUT ;
    USE SIGNAL ;
    PORT
      LAYER M3 ;
        RECT  4.608 36.576 4.626 36.72 ;
    END
  END dq[2]
  PIN dq[300]
    DIRECTION OUTPUT ;
    USE SIGNAL ;
    PORT
      LAYER M3 ;
        RECT  41.004 36.576 41.022 36.72 ;
    END
  END dq[300]
  PIN dq[301]
    DIRECTION OUTPUT ;
    USE SIGNAL ;
    PORT
      LAYER M5 ;
        RECT  41.136 36.528 41.16 36.72 ;
    END
  END dq[301]
  PIN dq[302]
    DIRECTION OUTPUT ;
    USE SIGNAL ;
    PORT
      LAYER M3 ;
        RECT  41.256 36.576 41.274 36.72 ;
    END
  END dq[302]
  PIN dq[303]
    DIRECTION OUTPUT ;
    USE SIGNAL ;
    PORT
      LAYER M5 ;
        RECT  41.376 36.528 41.4 36.72 ;
    END
  END dq[303]
  PIN dq[304]
    DIRECTION OUTPUT ;
    USE SIGNAL ;
    PORT
      LAYER M3 ;
        RECT  41.508 36.576 41.526 36.72 ;
    END
  END dq[304]
  PIN dq[305]
    DIRECTION OUTPUT ;
    USE SIGNAL ;
    PORT
      LAYER M5 ;
        RECT  41.616 36.528 41.64 36.72 ;
    END
  END dq[305]
  PIN dq[306]
    DIRECTION OUTPUT ;
    USE SIGNAL ;
    PORT
      LAYER M3 ;
        RECT  41.724 36.576 41.742 36.72 ;
    END
  END dq[306]
  PIN dq[307]
    DIRECTION OUTPUT ;
    USE SIGNAL ;
    PORT
      LAYER M5 ;
        RECT  41.856 36.528 41.88 36.72 ;
    END
  END dq[307]
  PIN dq[308]
    DIRECTION OUTPUT ;
    USE SIGNAL ;
    PORT
      LAYER M3 ;
        RECT  41.976 36.576 41.994 36.72 ;
    END
  END dq[308]
  PIN dq[309]
    DIRECTION OUTPUT ;
    USE SIGNAL ;
    PORT
      LAYER M5 ;
        RECT  42.096 36.528 42.12 36.72 ;
    END
  END dq[309]
  PIN dq[30]
    DIRECTION OUTPUT ;
    USE SIGNAL ;
    PORT
      LAYER M3 ;
        RECT  8.028 36.576 8.046 36.72 ;
    END
  END dq[30]
  PIN dq[310]
    DIRECTION OUTPUT ;
    USE SIGNAL ;
    PORT
      LAYER M3 ;
        RECT  42.228 36.576 42.246 36.72 ;
    END
  END dq[310]
  PIN dq[311]
    DIRECTION OUTPUT ;
    USE SIGNAL ;
    PORT
      LAYER M5 ;
        RECT  42.336 36.528 42.36 36.72 ;
    END
  END dq[311]
  PIN dq[312]
    DIRECTION OUTPUT ;
    USE SIGNAL ;
    PORT
      LAYER M3 ;
        RECT  42.48 36.576 42.498 36.72 ;
    END
  END dq[312]
  PIN dq[313]
    DIRECTION OUTPUT ;
    USE SIGNAL ;
    PORT
      LAYER M5 ;
        RECT  42.576 36.528 42.6 36.72 ;
    END
  END dq[313]
  PIN dq[314]
    DIRECTION OUTPUT ;
    USE SIGNAL ;
    PORT
      LAYER M3 ;
        RECT  42.696 36.576 42.714 36.72 ;
    END
  END dq[314]
  PIN dq[315]
    DIRECTION OUTPUT ;
    USE SIGNAL ;
    PORT
      LAYER M5 ;
        RECT  42.816 36.528 42.84 36.72 ;
    END
  END dq[315]
  PIN dq[316]
    DIRECTION OUTPUT ;
    USE SIGNAL ;
    PORT
      LAYER M3 ;
        RECT  42.948 36.576 42.966 36.72 ;
    END
  END dq[316]
  PIN dq[317]
    DIRECTION OUTPUT ;
    USE SIGNAL ;
    PORT
      LAYER M5 ;
        RECT  43.056 36.528 43.08 36.72 ;
    END
  END dq[317]
  PIN dq[318]
    DIRECTION OUTPUT ;
    USE SIGNAL ;
    PORT
      LAYER M3 ;
        RECT  43.2 36.576 43.218 36.72 ;
    END
  END dq[318]
  PIN dq[319]
    DIRECTION OUTPUT ;
    USE SIGNAL ;
    PORT
      LAYER M5 ;
        RECT  43.344 36.528 43.368 36.72 ;
    END
  END dq[319]
  PIN dq[31]
    DIRECTION OUTPUT ;
    USE SIGNAL ;
    PORT
      LAYER M5 ;
        RECT  8.16 36.528 8.184 36.72 ;
    END
  END dq[31]
  PIN dq[320]
    DIRECTION OUTPUT ;
    USE SIGNAL ;
    PORT
      LAYER M3 ;
        RECT  43.452 36.576 43.47 36.72 ;
    END
  END dq[320]
  PIN dq[321]
    DIRECTION OUTPUT ;
    USE SIGNAL ;
    PORT
      LAYER M5 ;
        RECT  43.584 36.528 43.608 36.72 ;
    END
  END dq[321]
  PIN dq[322]
    DIRECTION OUTPUT ;
    USE SIGNAL ;
    PORT
      LAYER M3 ;
        RECT  43.704 36.576 43.722 36.72 ;
    END
  END dq[322]
  PIN dq[323]
    DIRECTION OUTPUT ;
    USE SIGNAL ;
    PORT
      LAYER M5 ;
        RECT  43.824 36.528 43.848 36.72 ;
    END
  END dq[323]
  PIN dq[324]
    DIRECTION OUTPUT ;
    USE SIGNAL ;
    PORT
      LAYER M3 ;
        RECT  43.92 36.576 43.938 36.72 ;
    END
  END dq[324]
  PIN dq[325]
    DIRECTION OUTPUT ;
    USE SIGNAL ;
    PORT
      LAYER M5 ;
        RECT  44.064 36.528 44.088 36.72 ;
    END
  END dq[325]
  PIN dq[326]
    DIRECTION OUTPUT ;
    USE SIGNAL ;
    PORT
      LAYER M3 ;
        RECT  44.172 36.576 44.19 36.72 ;
    END
  END dq[326]
  PIN dq[327]
    DIRECTION OUTPUT ;
    USE SIGNAL ;
    PORT
      LAYER M5 ;
        RECT  44.304 36.528 44.328 36.72 ;
    END
  END dq[327]
  PIN dq[328]
    DIRECTION OUTPUT ;
    USE SIGNAL ;
    PORT
      LAYER M3 ;
        RECT  44.424 36.576 44.442 36.72 ;
    END
  END dq[328]
  PIN dq[329]
    DIRECTION OUTPUT ;
    USE SIGNAL ;
    PORT
      LAYER M5 ;
        RECT  44.544 36.528 44.568 36.72 ;
    END
  END dq[329]
  PIN dq[32]
    DIRECTION OUTPUT ;
    USE SIGNAL ;
    PORT
      LAYER M3 ;
        RECT  8.28 36.576 8.298 36.72 ;
    END
  END dq[32]
  PIN dq[330]
    DIRECTION OUTPUT ;
    USE SIGNAL ;
    PORT
      LAYER M3 ;
        RECT  44.676 36.576 44.694 36.72 ;
    END
  END dq[330]
  PIN dq[331]
    DIRECTION OUTPUT ;
    USE SIGNAL ;
    PORT
      LAYER M5 ;
        RECT  44.784 36.528 44.808 36.72 ;
    END
  END dq[331]
  PIN dq[332]
    DIRECTION OUTPUT ;
    USE SIGNAL ;
    PORT
      LAYER M3 ;
        RECT  44.928 36.576 44.946 36.72 ;
    END
  END dq[332]
  PIN dq[333]
    DIRECTION OUTPUT ;
    USE SIGNAL ;
    PORT
      LAYER M5 ;
        RECT  45.024 36.528 45.048 36.72 ;
    END
  END dq[333]
  PIN dq[334]
    DIRECTION OUTPUT ;
    USE SIGNAL ;
    PORT
      LAYER M3 ;
        RECT  45.144 36.576 45.162 36.72 ;
    END
  END dq[334]
  PIN dq[335]
    DIRECTION OUTPUT ;
    USE SIGNAL ;
    PORT
      LAYER M5 ;
        RECT  45.264 36.528 45.288 36.72 ;
    END
  END dq[335]
  PIN dq[336]
    DIRECTION OUTPUT ;
    USE SIGNAL ;
    PORT
      LAYER M3 ;
        RECT  45.396 36.576 45.414 36.72 ;
    END
  END dq[336]
  PIN dq[337]
    DIRECTION OUTPUT ;
    USE SIGNAL ;
    PORT
      LAYER M5 ;
        RECT  45.504 36.528 45.528 36.72 ;
    END
  END dq[337]
  PIN dq[338]
    DIRECTION OUTPUT ;
    USE SIGNAL ;
    PORT
      LAYER M3 ;
        RECT  45.648 36.576 45.666 36.72 ;
    END
  END dq[338]
  PIN dq[339]
    DIRECTION OUTPUT ;
    USE SIGNAL ;
    PORT
      LAYER M5 ;
        RECT  45.744 36.528 45.768 36.72 ;
    END
  END dq[339]
  PIN dq[33]
    DIRECTION OUTPUT ;
    USE SIGNAL ;
    PORT
      LAYER M5 ;
        RECT  8.4 36.528 8.424 36.72 ;
    END
  END dq[33]
  PIN dq[340]
    DIRECTION OUTPUT ;
    USE SIGNAL ;
    PORT
      LAYER M3 ;
        RECT  45.9 36.576 45.918 36.72 ;
    END
  END dq[340]
  PIN dq[341]
    DIRECTION OUTPUT ;
    USE SIGNAL ;
    PORT
      LAYER M5 ;
        RECT  45.984 36.528 46.008 36.72 ;
    END
  END dq[341]
  PIN dq[342]
    DIRECTION OUTPUT ;
    USE SIGNAL ;
    PORT
      LAYER M3 ;
        RECT  46.116 36.576 46.134 36.72 ;
    END
  END dq[342]
  PIN dq[343]
    DIRECTION OUTPUT ;
    USE SIGNAL ;
    PORT
      LAYER M5 ;
        RECT  46.272 36.528 46.296 36.72 ;
    END
  END dq[343]
  PIN dq[344]
    DIRECTION OUTPUT ;
    USE SIGNAL ;
    PORT
      LAYER M3 ;
        RECT  46.368 36.576 46.386 36.72 ;
    END
  END dq[344]
  PIN dq[345]
    DIRECTION OUTPUT ;
    USE SIGNAL ;
    PORT
      LAYER M5 ;
        RECT  46.512 36.528 46.536 36.72 ;
    END
  END dq[345]
  PIN dq[346]
    DIRECTION OUTPUT ;
    USE SIGNAL ;
    PORT
      LAYER M3 ;
        RECT  46.62 36.576 46.638 36.72 ;
    END
  END dq[346]
  PIN dq[347]
    DIRECTION OUTPUT ;
    USE SIGNAL ;
    PORT
      LAYER M5 ;
        RECT  46.752 36.528 46.776 36.72 ;
    END
  END dq[347]
  PIN dq[348]
    DIRECTION OUTPUT ;
    USE SIGNAL ;
    PORT
      LAYER M3 ;
        RECT  46.872 36.576 46.89 36.72 ;
    END
  END dq[348]
  PIN dq[349]
    DIRECTION OUTPUT ;
    USE SIGNAL ;
    PORT
      LAYER M5 ;
        RECT  46.992 36.528 47.016 36.72 ;
    END
  END dq[349]
  PIN dq[34]
    DIRECTION OUTPUT ;
    USE SIGNAL ;
    PORT
      LAYER M3 ;
        RECT  8.532 36.576 8.55 36.72 ;
    END
  END dq[34]
  PIN dq[350]
    DIRECTION OUTPUT ;
    USE SIGNAL ;
    PORT
      LAYER M3 ;
        RECT  47.124 36.576 47.142 36.72 ;
    END
  END dq[350]
  PIN dq[351]
    DIRECTION OUTPUT ;
    USE SIGNAL ;
    PORT
      LAYER M5 ;
        RECT  47.232 36.528 47.256 36.72 ;
    END
  END dq[351]
  PIN dq[352]
    DIRECTION OUTPUT ;
    USE SIGNAL ;
    PORT
      LAYER M3 ;
        RECT  47.34 36.576 47.358 36.72 ;
    END
  END dq[352]
  PIN dq[353]
    DIRECTION OUTPUT ;
    USE SIGNAL ;
    PORT
      LAYER M5 ;
        RECT  47.472 36.528 47.496 36.72 ;
    END
  END dq[353]
  PIN dq[354]
    DIRECTION OUTPUT ;
    USE SIGNAL ;
    PORT
      LAYER M3 ;
        RECT  47.592 36.576 47.61 36.72 ;
    END
  END dq[354]
  PIN dq[355]
    DIRECTION OUTPUT ;
    USE SIGNAL ;
    PORT
      LAYER M5 ;
        RECT  47.712 36.528 47.736 36.72 ;
    END
  END dq[355]
  PIN dq[356]
    DIRECTION OUTPUT ;
    USE SIGNAL ;
    PORT
      LAYER M3 ;
        RECT  47.844 36.576 47.862 36.72 ;
    END
  END dq[356]
  PIN dq[357]
    DIRECTION OUTPUT ;
    USE SIGNAL ;
    PORT
      LAYER M5 ;
        RECT  47.952 36.528 47.976 36.72 ;
    END
  END dq[357]
  PIN dq[358]
    DIRECTION OUTPUT ;
    USE SIGNAL ;
    PORT
      LAYER M3 ;
        RECT  48.096 36.576 48.114 36.72 ;
    END
  END dq[358]
  PIN dq[359]
    DIRECTION OUTPUT ;
    USE SIGNAL ;
    PORT
      LAYER M5 ;
        RECT  48.192 36.528 48.216 36.72 ;
    END
  END dq[359]
  PIN dq[35]
    DIRECTION OUTPUT ;
    USE SIGNAL ;
    PORT
      LAYER M5 ;
        RECT  8.64 36.528 8.664 36.72 ;
    END
  END dq[35]
  PIN dq[360]
    DIRECTION OUTPUT ;
    USE SIGNAL ;
    PORT
      LAYER M3 ;
        RECT  48.312 36.576 48.33 36.72 ;
    END
  END dq[360]
  PIN dq[361]
    DIRECTION OUTPUT ;
    USE SIGNAL ;
    PORT
      LAYER M5 ;
        RECT  48.432 36.528 48.456 36.72 ;
    END
  END dq[361]
  PIN dq[362]
    DIRECTION OUTPUT ;
    USE SIGNAL ;
    PORT
      LAYER M3 ;
        RECT  48.564 36.576 48.582 36.72 ;
    END
  END dq[362]
  PIN dq[363]
    DIRECTION OUTPUT ;
    USE SIGNAL ;
    PORT
      LAYER M5 ;
        RECT  48.672 36.528 48.696 36.72 ;
    END
  END dq[363]
  PIN dq[364]
    DIRECTION OUTPUT ;
    USE SIGNAL ;
    PORT
      LAYER M3 ;
        RECT  48.816 36.576 48.834 36.72 ;
    END
  END dq[364]
  PIN dq[365]
    DIRECTION OUTPUT ;
    USE SIGNAL ;
    PORT
      LAYER M5 ;
        RECT  48.96 36.528 48.984 36.72 ;
    END
  END dq[365]
  PIN dq[366]
    DIRECTION OUTPUT ;
    USE SIGNAL ;
    PORT
      LAYER M3 ;
        RECT  49.068 36.576 49.086 36.72 ;
    END
  END dq[366]
  PIN dq[367]
    DIRECTION OUTPUT ;
    USE SIGNAL ;
    PORT
      LAYER M5 ;
        RECT  49.2 36.528 49.224 36.72 ;
    END
  END dq[367]
  PIN dq[368]
    DIRECTION OUTPUT ;
    USE SIGNAL ;
    PORT
      LAYER M3 ;
        RECT  49.32 36.576 49.338 36.72 ;
    END
  END dq[368]
  PIN dq[369]
    DIRECTION OUTPUT ;
    USE SIGNAL ;
    PORT
      LAYER M5 ;
        RECT  49.44 36.528 49.464 36.72 ;
    END
  END dq[369]
  PIN dq[36]
    DIRECTION OUTPUT ;
    USE SIGNAL ;
    PORT
      LAYER M3 ;
        RECT  8.784 36.576 8.802 36.72 ;
    END
  END dq[36]
  PIN dq[370]
    DIRECTION OUTPUT ;
    USE SIGNAL ;
    PORT
      LAYER M3 ;
        RECT  49.536 36.576 49.554 36.72 ;
    END
  END dq[370]
  PIN dq[371]
    DIRECTION OUTPUT ;
    USE SIGNAL ;
    PORT
      LAYER M5 ;
        RECT  49.68 36.528 49.704 36.72 ;
    END
  END dq[371]
  PIN dq[372]
    DIRECTION OUTPUT ;
    USE SIGNAL ;
    PORT
      LAYER M3 ;
        RECT  49.788 36.576 49.806 36.72 ;
    END
  END dq[372]
  PIN dq[373]
    DIRECTION OUTPUT ;
    USE SIGNAL ;
    PORT
      LAYER M5 ;
        RECT  49.92 36.528 49.944 36.72 ;
    END
  END dq[373]
  PIN dq[374]
    DIRECTION OUTPUT ;
    USE SIGNAL ;
    PORT
      LAYER M3 ;
        RECT  50.04 36.576 50.058 36.72 ;
    END
  END dq[374]
  PIN dq[375]
    DIRECTION OUTPUT ;
    USE SIGNAL ;
    PORT
      LAYER M5 ;
        RECT  50.16 36.528 50.184 36.72 ;
    END
  END dq[375]
  PIN dq[376]
    DIRECTION OUTPUT ;
    USE SIGNAL ;
    PORT
      LAYER M3 ;
        RECT  50.292 36.576 50.31 36.72 ;
    END
  END dq[376]
  PIN dq[377]
    DIRECTION OUTPUT ;
    USE SIGNAL ;
    PORT
      LAYER M5 ;
        RECT  50.4 36.528 50.424 36.72 ;
    END
  END dq[377]
  PIN dq[378]
    DIRECTION OUTPUT ;
    USE SIGNAL ;
    PORT
      LAYER M3 ;
        RECT  50.544 36.576 50.562 36.72 ;
    END
  END dq[378]
  PIN dq[379]
    DIRECTION OUTPUT ;
    USE SIGNAL ;
    PORT
      LAYER M5 ;
        RECT  50.64 36.528 50.664 36.72 ;
    END
  END dq[379]
  PIN dq[37]
    DIRECTION OUTPUT ;
    USE SIGNAL ;
    PORT
      LAYER M5 ;
        RECT  8.88 36.528 8.904 36.72 ;
    END
  END dq[37]
  PIN dq[380]
    DIRECTION OUTPUT ;
    USE SIGNAL ;
    PORT
      LAYER M3 ;
        RECT  50.76 36.576 50.778 36.72 ;
    END
  END dq[380]
  PIN dq[381]
    DIRECTION OUTPUT ;
    USE SIGNAL ;
    PORT
      LAYER M5 ;
        RECT  50.88 36.528 50.904 36.72 ;
    END
  END dq[381]
  PIN dq[382]
    DIRECTION OUTPUT ;
    USE SIGNAL ;
    PORT
      LAYER M3 ;
        RECT  51.012 36.576 51.03 36.72 ;
    END
  END dq[382]
  PIN dq[383]
    DIRECTION OUTPUT ;
    USE SIGNAL ;
    PORT
      LAYER M5 ;
        RECT  51.12 36.528 51.144 36.72 ;
    END
  END dq[383]
  PIN dq[384]
    DIRECTION OUTPUT ;
    USE SIGNAL ;
    PORT
      LAYER M3 ;
        RECT  51.264 36.576 51.282 36.72 ;
    END
  END dq[384]
  PIN dq[385]
    DIRECTION OUTPUT ;
    USE SIGNAL ;
    PORT
      LAYER M5 ;
        RECT  51.36 36.528 51.384 36.72 ;
    END
  END dq[385]
  PIN dq[386]
    DIRECTION OUTPUT ;
    USE SIGNAL ;
    PORT
      LAYER M3 ;
        RECT  51.516 36.576 51.534 36.72 ;
    END
  END dq[386]
  PIN dq[387]
    DIRECTION OUTPUT ;
    USE SIGNAL ;
    PORT
      LAYER M5 ;
        RECT  51.6 36.528 51.624 36.72 ;
    END
  END dq[387]
  PIN dq[388]
    DIRECTION OUTPUT ;
    USE SIGNAL ;
    PORT
      LAYER M3 ;
        RECT  51.732 36.576 51.75 36.72 ;
    END
  END dq[388]
  PIN dq[389]
    DIRECTION OUTPUT ;
    USE SIGNAL ;
    PORT
      LAYER M5 ;
        RECT  51.888 36.528 51.912 36.72 ;
    END
  END dq[389]
  PIN dq[38]
    DIRECTION OUTPUT ;
    USE SIGNAL ;
    PORT
      LAYER M3 ;
        RECT  9 36.576 9.018 36.72 ;
    END
  END dq[38]
  PIN dq[390]
    DIRECTION OUTPUT ;
    USE SIGNAL ;
    PORT
      LAYER M3 ;
        RECT  51.984 36.576 52.002 36.72 ;
    END
  END dq[390]
  PIN dq[391]
    DIRECTION OUTPUT ;
    USE SIGNAL ;
    PORT
      LAYER M5 ;
        RECT  52.128 36.528 52.152 36.72 ;
    END
  END dq[391]
  PIN dq[392]
    DIRECTION OUTPUT ;
    USE SIGNAL ;
    PORT
      LAYER M3 ;
        RECT  52.236 36.576 52.254 36.72 ;
    END
  END dq[392]
  PIN dq[393]
    DIRECTION OUTPUT ;
    USE SIGNAL ;
    PORT
      LAYER M5 ;
        RECT  52.368 36.528 52.392 36.72 ;
    END
  END dq[393]
  PIN dq[394]
    DIRECTION OUTPUT ;
    USE SIGNAL ;
    PORT
      LAYER M3 ;
        RECT  52.488 36.576 52.506 36.72 ;
    END
  END dq[394]
  PIN dq[395]
    DIRECTION OUTPUT ;
    USE SIGNAL ;
    PORT
      LAYER M5 ;
        RECT  52.608 36.528 52.632 36.72 ;
    END
  END dq[395]
  PIN dq[396]
    DIRECTION OUTPUT ;
    USE SIGNAL ;
    PORT
      LAYER M3 ;
        RECT  52.74 36.576 52.758 36.72 ;
    END
  END dq[396]
  PIN dq[397]
    DIRECTION OUTPUT ;
    USE SIGNAL ;
    PORT
      LAYER M5 ;
        RECT  52.848 36.528 52.872 36.72 ;
    END
  END dq[397]
  PIN dq[398]
    DIRECTION OUTPUT ;
    USE SIGNAL ;
    PORT
      LAYER M3 ;
        RECT  52.956 36.576 52.974 36.72 ;
    END
  END dq[398]
  PIN dq[399]
    DIRECTION OUTPUT ;
    USE SIGNAL ;
    PORT
      LAYER M5 ;
        RECT  53.088 36.528 53.112 36.72 ;
    END
  END dq[399]
  PIN dq[39]
    DIRECTION OUTPUT ;
    USE SIGNAL ;
    PORT
      LAYER M5 ;
        RECT  9.12 36.528 9.144 36.72 ;
    END
  END dq[39]
  PIN dq[3]
    DIRECTION OUTPUT ;
    USE SIGNAL ;
    PORT
      LAYER M5 ;
        RECT  4.752 36.528 4.776 36.72 ;
    END
  END dq[3]
  PIN dq[400]
    DIRECTION OUTPUT ;
    USE SIGNAL ;
    PORT
      LAYER M3 ;
        RECT  53.208 36.576 53.226 36.72 ;
    END
  END dq[400]
  PIN dq[401]
    DIRECTION OUTPUT ;
    USE SIGNAL ;
    PORT
      LAYER M5 ;
        RECT  53.328 36.528 53.352 36.72 ;
    END
  END dq[401]
  PIN dq[402]
    DIRECTION OUTPUT ;
    USE SIGNAL ;
    PORT
      LAYER M3 ;
        RECT  53.46 36.576 53.478 36.72 ;
    END
  END dq[402]
  PIN dq[403]
    DIRECTION OUTPUT ;
    USE SIGNAL ;
    PORT
      LAYER M5 ;
        RECT  53.568 36.528 53.592 36.72 ;
    END
  END dq[403]
  PIN dq[404]
    DIRECTION OUTPUT ;
    USE SIGNAL ;
    PORT
      LAYER M3 ;
        RECT  53.712 36.576 53.73 36.72 ;
    END
  END dq[404]
  PIN dq[405]
    DIRECTION OUTPUT ;
    USE SIGNAL ;
    PORT
      LAYER M5 ;
        RECT  53.808 36.528 53.832 36.72 ;
    END
  END dq[405]
  PIN dq[406]
    DIRECTION OUTPUT ;
    USE SIGNAL ;
    PORT
      LAYER M3 ;
        RECT  53.964 36.576 53.982 36.72 ;
    END
  END dq[406]
  PIN dq[407]
    DIRECTION OUTPUT ;
    USE SIGNAL ;
    PORT
      LAYER M5 ;
        RECT  54.048 36.528 54.072 36.72 ;
    END
  END dq[407]
  PIN dq[408]
    DIRECTION OUTPUT ;
    USE SIGNAL ;
    PORT
      LAYER M3 ;
        RECT  54.18 36.576 54.198 36.72 ;
    END
  END dq[408]
  PIN dq[409]
    DIRECTION OUTPUT ;
    USE SIGNAL ;
    PORT
      LAYER M5 ;
        RECT  54.288 36.528 54.312 36.72 ;
    END
  END dq[409]
  PIN dq[40]
    DIRECTION OUTPUT ;
    USE SIGNAL ;
    PORT
      LAYER M3 ;
        RECT  9.252 36.576 9.27 36.72 ;
    END
  END dq[40]
  PIN dq[410]
    DIRECTION OUTPUT ;
    USE SIGNAL ;
    PORT
      LAYER M3 ;
        RECT  54.432 36.576 54.45 36.72 ;
    END
  END dq[410]
  PIN dq[411]
    DIRECTION OUTPUT ;
    USE SIGNAL ;
    PORT
      LAYER M5 ;
        RECT  54.576 36.528 54.6 36.72 ;
    END
  END dq[411]
  PIN dq[412]
    DIRECTION OUTPUT ;
    USE SIGNAL ;
    PORT
      LAYER M3 ;
        RECT  54.684 36.576 54.702 36.72 ;
    END
  END dq[412]
  PIN dq[413]
    DIRECTION OUTPUT ;
    USE SIGNAL ;
    PORT
      LAYER M5 ;
        RECT  54.816 36.528 54.84 36.72 ;
    END
  END dq[413]
  PIN dq[414]
    DIRECTION OUTPUT ;
    USE SIGNAL ;
    PORT
      LAYER M3 ;
        RECT  54.936 36.576 54.954 36.72 ;
    END
  END dq[414]
  PIN dq[415]
    DIRECTION OUTPUT ;
    USE SIGNAL ;
    PORT
      LAYER M5 ;
        RECT  55.056 36.528 55.08 36.72 ;
    END
  END dq[415]
  PIN dq[416]
    DIRECTION OUTPUT ;
    USE SIGNAL ;
    PORT
      LAYER M3 ;
        RECT  55.152 36.576 55.17 36.72 ;
    END
  END dq[416]
  PIN dq[417]
    DIRECTION OUTPUT ;
    USE SIGNAL ;
    PORT
      LAYER M5 ;
        RECT  55.296 36.528 55.32 36.72 ;
    END
  END dq[417]
  PIN dq[418]
    DIRECTION OUTPUT ;
    USE SIGNAL ;
    PORT
      LAYER M3 ;
        RECT  55.404 36.576 55.422 36.72 ;
    END
  END dq[418]
  PIN dq[419]
    DIRECTION OUTPUT ;
    USE SIGNAL ;
    PORT
      LAYER M5 ;
        RECT  55.536 36.528 55.56 36.72 ;
    END
  END dq[419]
  PIN dq[41]
    DIRECTION OUTPUT ;
    USE SIGNAL ;
    PORT
      LAYER M5 ;
        RECT  9.36 36.528 9.384 36.72 ;
    END
  END dq[41]
  PIN dq[420]
    DIRECTION OUTPUT ;
    USE SIGNAL ;
    PORT
      LAYER M3 ;
        RECT  55.656 36.576 55.674 36.72 ;
    END
  END dq[420]
  PIN dq[421]
    DIRECTION OUTPUT ;
    USE SIGNAL ;
    PORT
      LAYER M5 ;
        RECT  55.776 36.528 55.8 36.72 ;
    END
  END dq[421]
  PIN dq[422]
    DIRECTION OUTPUT ;
    USE SIGNAL ;
    PORT
      LAYER M3 ;
        RECT  55.908 36.576 55.926 36.72 ;
    END
  END dq[422]
  PIN dq[423]
    DIRECTION OUTPUT ;
    USE SIGNAL ;
    PORT
      LAYER M5 ;
        RECT  56.016 36.528 56.04 36.72 ;
    END
  END dq[423]
  PIN dq[424]
    DIRECTION OUTPUT ;
    USE SIGNAL ;
    PORT
      LAYER M3 ;
        RECT  56.16 36.576 56.178 36.72 ;
    END
  END dq[424]
  PIN dq[425]
    DIRECTION OUTPUT ;
    USE SIGNAL ;
    PORT
      LAYER M5 ;
        RECT  56.256 36.528 56.28 36.72 ;
    END
  END dq[425]
  PIN dq[426]
    DIRECTION OUTPUT ;
    USE SIGNAL ;
    PORT
      LAYER M3 ;
        RECT  56.376 36.576 56.394 36.72 ;
    END
  END dq[426]
  PIN dq[427]
    DIRECTION OUTPUT ;
    USE SIGNAL ;
    PORT
      LAYER M5 ;
        RECT  56.496 36.528 56.52 36.72 ;
    END
  END dq[427]
  PIN dq[428]
    DIRECTION OUTPUT ;
    USE SIGNAL ;
    PORT
      LAYER M3 ;
        RECT  56.628 36.576 56.646 36.72 ;
    END
  END dq[428]
  PIN dq[429]
    DIRECTION OUTPUT ;
    USE SIGNAL ;
    PORT
      LAYER M5 ;
        RECT  56.736 36.528 56.76 36.72 ;
    END
  END dq[429]
  PIN dq[42]
    DIRECTION OUTPUT ;
    USE SIGNAL ;
    PORT
      LAYER M3 ;
        RECT  9.504 36.576 9.522 36.72 ;
    END
  END dq[42]
  PIN dq[430]
    DIRECTION OUTPUT ;
    USE SIGNAL ;
    PORT
      LAYER M3 ;
        RECT  56.88 36.576 56.898 36.72 ;
    END
  END dq[430]
  PIN dq[431]
    DIRECTION OUTPUT ;
    USE SIGNAL ;
    PORT
      LAYER M5 ;
        RECT  56.976 36.528 57 36.72 ;
    END
  END dq[431]
  PIN dq[432]
    DIRECTION OUTPUT ;
    USE SIGNAL ;
    PORT
      LAYER M3 ;
        RECT  57.132 36.576 57.15 36.72 ;
    END
  END dq[432]
  PIN dq[433]
    DIRECTION OUTPUT ;
    USE SIGNAL ;
    PORT
      LAYER M5 ;
        RECT  57.264 36.528 57.288 36.72 ;
    END
  END dq[433]
  PIN dq[434]
    DIRECTION OUTPUT ;
    USE SIGNAL ;
    PORT
      LAYER M3 ;
        RECT  57.348 36.576 57.366 36.72 ;
    END
  END dq[434]
  PIN dq[435]
    DIRECTION OUTPUT ;
    USE SIGNAL ;
    PORT
      LAYER M5 ;
        RECT  57.504 36.528 57.528 36.72 ;
    END
  END dq[435]
  PIN dq[436]
    DIRECTION OUTPUT ;
    USE SIGNAL ;
    PORT
      LAYER M3 ;
        RECT  57.6 36.576 57.618 36.72 ;
    END
  END dq[436]
  PIN dq[437]
    DIRECTION OUTPUT ;
    USE SIGNAL ;
    PORT
      LAYER M5 ;
        RECT  57.744 36.528 57.768 36.72 ;
    END
  END dq[437]
  PIN dq[438]
    DIRECTION OUTPUT ;
    USE SIGNAL ;
    PORT
      LAYER M3 ;
        RECT  57.852 36.576 57.87 36.72 ;
    END
  END dq[438]
  PIN dq[439]
    DIRECTION OUTPUT ;
    USE SIGNAL ;
    PORT
      LAYER M5 ;
        RECT  57.984 36.528 58.008 36.72 ;
    END
  END dq[439]
  PIN dq[43]
    DIRECTION OUTPUT ;
    USE SIGNAL ;
    PORT
      LAYER M5 ;
        RECT  9.6 36.528 9.624 36.72 ;
    END
  END dq[43]
  PIN dq[440]
    DIRECTION OUTPUT ;
    USE SIGNAL ;
    PORT
      LAYER M3 ;
        RECT  58.104 36.576 58.122 36.72 ;
    END
  END dq[440]
  PIN dq[441]
    DIRECTION OUTPUT ;
    USE SIGNAL ;
    PORT
      LAYER M5 ;
        RECT  58.224 36.528 58.248 36.72 ;
    END
  END dq[441]
  PIN dq[442]
    DIRECTION OUTPUT ;
    USE SIGNAL ;
    PORT
      LAYER M3 ;
        RECT  58.356 36.576 58.374 36.72 ;
    END
  END dq[442]
  PIN dq[443]
    DIRECTION OUTPUT ;
    USE SIGNAL ;
    PORT
      LAYER M5 ;
        RECT  58.464 36.528 58.488 36.72 ;
    END
  END dq[443]
  PIN dq[444]
    DIRECTION OUTPUT ;
    USE SIGNAL ;
    PORT
      LAYER M3 ;
        RECT  58.572 36.576 58.59 36.72 ;
    END
  END dq[444]
  PIN dq[445]
    DIRECTION OUTPUT ;
    USE SIGNAL ;
    PORT
      LAYER M5 ;
        RECT  58.704 36.528 58.728 36.72 ;
    END
  END dq[445]
  PIN dq[446]
    DIRECTION OUTPUT ;
    USE SIGNAL ;
    PORT
      LAYER M3 ;
        RECT  58.824 36.576 58.842 36.72 ;
    END
  END dq[446]
  PIN dq[447]
    DIRECTION OUTPUT ;
    USE SIGNAL ;
    PORT
      LAYER M5 ;
        RECT  58.944 36.528 58.968 36.72 ;
    END
  END dq[447]
  PIN dq[448]
    DIRECTION OUTPUT ;
    USE SIGNAL ;
    PORT
      LAYER M3 ;
        RECT  59.076 36.576 59.094 36.72 ;
    END
  END dq[448]
  PIN dq[449]
    DIRECTION OUTPUT ;
    USE SIGNAL ;
    PORT
      LAYER M5 ;
        RECT  59.184 36.528 59.208 36.72 ;
    END
  END dq[449]
  PIN dq[44]
    DIRECTION OUTPUT ;
    USE SIGNAL ;
    PORT
      LAYER M3 ;
        RECT  9.756 36.576 9.774 36.72 ;
    END
  END dq[44]
  PIN dq[450]
    DIRECTION OUTPUT ;
    USE SIGNAL ;
    PORT
      LAYER M3 ;
        RECT  59.328 36.576 59.346 36.72 ;
    END
  END dq[450]
  PIN dq[451]
    DIRECTION OUTPUT ;
    USE SIGNAL ;
    PORT
      LAYER M5 ;
        RECT  59.424 36.528 59.448 36.72 ;
    END
  END dq[451]
  PIN dq[452]
    DIRECTION OUTPUT ;
    USE SIGNAL ;
    PORT
      LAYER M3 ;
        RECT  59.58 36.576 59.598 36.72 ;
    END
  END dq[452]
  PIN dq[453]
    DIRECTION OUTPUT ;
    USE SIGNAL ;
    PORT
      LAYER M5 ;
        RECT  59.664 36.528 59.688 36.72 ;
    END
  END dq[453]
  PIN dq[454]
    DIRECTION OUTPUT ;
    USE SIGNAL ;
    PORT
      LAYER M3 ;
        RECT  59.796 36.576 59.814 36.72 ;
    END
  END dq[454]
  PIN dq[455]
    DIRECTION OUTPUT ;
    USE SIGNAL ;
    PORT
      LAYER M5 ;
        RECT  59.904 36.528 59.928 36.72 ;
    END
  END dq[455]
  PIN dq[456]
    DIRECTION OUTPUT ;
    USE SIGNAL ;
    PORT
      LAYER M3 ;
        RECT  60.048 36.576 60.066 36.72 ;
    END
  END dq[456]
  PIN dq[457]
    DIRECTION OUTPUT ;
    USE SIGNAL ;
    PORT
      LAYER M5 ;
        RECT  60.192 36.528 60.216 36.72 ;
    END
  END dq[457]
  PIN dq[458]
    DIRECTION OUTPUT ;
    USE SIGNAL ;
    PORT
      LAYER M3 ;
        RECT  60.3 36.576 60.318 36.72 ;
    END
  END dq[458]
  PIN dq[459]
    DIRECTION OUTPUT ;
    USE SIGNAL ;
    PORT
      LAYER M5 ;
        RECT  60.432 36.528 60.456 36.72 ;
    END
  END dq[459]
  PIN dq[45]
    DIRECTION OUTPUT ;
    USE SIGNAL ;
    PORT
      LAYER M5 ;
        RECT  9.84 36.528 9.864 36.72 ;
    END
  END dq[45]
  PIN dq[460]
    DIRECTION OUTPUT ;
    USE SIGNAL ;
    PORT
      LAYER M3 ;
        RECT  60.552 36.576 60.57 36.72 ;
    END
  END dq[460]
  PIN dq[461]
    DIRECTION OUTPUT ;
    USE SIGNAL ;
    PORT
      LAYER M5 ;
        RECT  60.672 36.528 60.696 36.72 ;
    END
  END dq[461]
  PIN dq[462]
    DIRECTION OUTPUT ;
    USE SIGNAL ;
    PORT
      LAYER M3 ;
        RECT  60.768 36.576 60.786 36.72 ;
    END
  END dq[462]
  PIN dq[463]
    DIRECTION OUTPUT ;
    USE SIGNAL ;
    PORT
      LAYER M5 ;
        RECT  60.912 36.528 60.936 36.72 ;
    END
  END dq[463]
  PIN dq[464]
    DIRECTION OUTPUT ;
    USE SIGNAL ;
    PORT
      LAYER M3 ;
        RECT  61.02 36.576 61.038 36.72 ;
    END
  END dq[464]
  PIN dq[465]
    DIRECTION OUTPUT ;
    USE SIGNAL ;
    PORT
      LAYER M5 ;
        RECT  61.152 36.528 61.176 36.72 ;
    END
  END dq[465]
  PIN dq[466]
    DIRECTION OUTPUT ;
    USE SIGNAL ;
    PORT
      LAYER M3 ;
        RECT  61.272 36.576 61.29 36.72 ;
    END
  END dq[466]
  PIN dq[467]
    DIRECTION OUTPUT ;
    USE SIGNAL ;
    PORT
      LAYER M5 ;
        RECT  61.392 36.528 61.416 36.72 ;
    END
  END dq[467]
  PIN dq[468]
    DIRECTION OUTPUT ;
    USE SIGNAL ;
    PORT
      LAYER M3 ;
        RECT  61.524 36.576 61.542 36.72 ;
    END
  END dq[468]
  PIN dq[469]
    DIRECTION OUTPUT ;
    USE SIGNAL ;
    PORT
      LAYER M5 ;
        RECT  61.632 36.528 61.656 36.72 ;
    END
  END dq[469]
  PIN dq[46]
    DIRECTION OUTPUT ;
    USE SIGNAL ;
    PORT
      LAYER M3 ;
        RECT  9.972 36.576 9.99 36.72 ;
    END
  END dq[46]
  PIN dq[470]
    DIRECTION OUTPUT ;
    USE SIGNAL ;
    PORT
      LAYER M3 ;
        RECT  61.776 36.576 61.794 36.72 ;
    END
  END dq[470]
  PIN dq[471]
    DIRECTION OUTPUT ;
    USE SIGNAL ;
    PORT
      LAYER M5 ;
        RECT  61.872 36.528 61.896 36.72 ;
    END
  END dq[471]
  PIN dq[472]
    DIRECTION OUTPUT ;
    USE SIGNAL ;
    PORT
      LAYER M3 ;
        RECT  61.992 36.576 62.01 36.72 ;
    END
  END dq[472]
  PIN dq[473]
    DIRECTION OUTPUT ;
    USE SIGNAL ;
    PORT
      LAYER M5 ;
        RECT  62.112 36.528 62.136 36.72 ;
    END
  END dq[473]
  PIN dq[474]
    DIRECTION OUTPUT ;
    USE SIGNAL ;
    PORT
      LAYER M3 ;
        RECT  62.244 36.576 62.262 36.72 ;
    END
  END dq[474]
  PIN dq[475]
    DIRECTION OUTPUT ;
    USE SIGNAL ;
    PORT
      LAYER M5 ;
        RECT  62.352 36.528 62.376 36.72 ;
    END
  END dq[475]
  PIN dq[476]
    DIRECTION OUTPUT ;
    USE SIGNAL ;
    PORT
      LAYER M3 ;
        RECT  62.496 36.576 62.514 36.72 ;
    END
  END dq[476]
  PIN dq[477]
    DIRECTION OUTPUT ;
    USE SIGNAL ;
    PORT
      LAYER M5 ;
        RECT  62.592 36.528 62.616 36.72 ;
    END
  END dq[477]
  PIN dq[478]
    DIRECTION OUTPUT ;
    USE SIGNAL ;
    PORT
      LAYER M3 ;
        RECT  62.748 36.576 62.766 36.72 ;
    END
  END dq[478]
  PIN dq[479]
    DIRECTION OUTPUT ;
    USE SIGNAL ;
    PORT
      LAYER M5 ;
        RECT  62.88 36.528 62.904 36.72 ;
    END
  END dq[479]
  PIN dq[47]
    DIRECTION OUTPUT ;
    USE SIGNAL ;
    PORT
      LAYER M5 ;
        RECT  10.128 36.528 10.152 36.72 ;
    END
  END dq[47]
  PIN dq[480]
    DIRECTION OUTPUT ;
    USE SIGNAL ;
    PORT
      LAYER M3 ;
        RECT  63 36.576 63.018 36.72 ;
    END
  END dq[480]
  PIN dq[481]
    DIRECTION OUTPUT ;
    USE SIGNAL ;
    PORT
      LAYER M5 ;
        RECT  63.12 36.528 63.144 36.72 ;
    END
  END dq[481]
  PIN dq[482]
    DIRECTION OUTPUT ;
    USE SIGNAL ;
    PORT
      LAYER M3 ;
        RECT  63.216 36.576 63.234 36.72 ;
    END
  END dq[482]
  PIN dq[483]
    DIRECTION OUTPUT ;
    USE SIGNAL ;
    PORT
      LAYER M5 ;
        RECT  63.36 36.528 63.384 36.72 ;
    END
  END dq[483]
  PIN dq[484]
    DIRECTION OUTPUT ;
    USE SIGNAL ;
    PORT
      LAYER M3 ;
        RECT  63.468 36.576 63.486 36.72 ;
    END
  END dq[484]
  PIN dq[485]
    DIRECTION OUTPUT ;
    USE SIGNAL ;
    PORT
      LAYER M5 ;
        RECT  63.6 36.528 63.624 36.72 ;
    END
  END dq[485]
  PIN dq[486]
    DIRECTION OUTPUT ;
    USE SIGNAL ;
    PORT
      LAYER M3 ;
        RECT  63.72 36.576 63.738 36.72 ;
    END
  END dq[486]
  PIN dq[487]
    DIRECTION OUTPUT ;
    USE SIGNAL ;
    PORT
      LAYER M5 ;
        RECT  63.84 36.528 63.864 36.72 ;
    END
  END dq[487]
  PIN dq[488]
    DIRECTION OUTPUT ;
    USE SIGNAL ;
    PORT
      LAYER M3 ;
        RECT  63.972 36.576 63.99 36.72 ;
    END
  END dq[488]
  PIN dq[489]
    DIRECTION OUTPUT ;
    USE SIGNAL ;
    PORT
      LAYER M5 ;
        RECT  64.08 36.528 64.104 36.72 ;
    END
  END dq[489]
  PIN dq[48]
    DIRECTION OUTPUT ;
    USE SIGNAL ;
    PORT
      LAYER M3 ;
        RECT  10.224 36.576 10.242 36.72 ;
    END
  END dq[48]
  PIN dq[490]
    DIRECTION OUTPUT ;
    USE SIGNAL ;
    PORT
      LAYER M3 ;
        RECT  64.188 36.576 64.206 36.72 ;
    END
  END dq[490]
  PIN dq[491]
    DIRECTION OUTPUT ;
    USE SIGNAL ;
    PORT
      LAYER M5 ;
        RECT  64.32 36.528 64.344 36.72 ;
    END
  END dq[491]
  PIN dq[492]
    DIRECTION OUTPUT ;
    USE SIGNAL ;
    PORT
      LAYER M3 ;
        RECT  64.44 36.576 64.458 36.72 ;
    END
  END dq[492]
  PIN dq[493]
    DIRECTION OUTPUT ;
    USE SIGNAL ;
    PORT
      LAYER M5 ;
        RECT  64.56 36.528 64.584 36.72 ;
    END
  END dq[493]
  PIN dq[494]
    DIRECTION OUTPUT ;
    USE SIGNAL ;
    PORT
      LAYER M3 ;
        RECT  64.692 36.576 64.71 36.72 ;
    END
  END dq[494]
  PIN dq[495]
    DIRECTION OUTPUT ;
    USE SIGNAL ;
    PORT
      LAYER M5 ;
        RECT  64.8 36.528 64.824 36.72 ;
    END
  END dq[495]
  PIN dq[496]
    DIRECTION OUTPUT ;
    USE SIGNAL ;
    PORT
      LAYER M3 ;
        RECT  64.944 36.576 64.962 36.72 ;
    END
  END dq[496]
  PIN dq[497]
    DIRECTION OUTPUT ;
    USE SIGNAL ;
    PORT
      LAYER M5 ;
        RECT  65.04 36.528 65.064 36.72 ;
    END
  END dq[497]
  PIN dq[498]
    DIRECTION OUTPUT ;
    USE SIGNAL ;
    PORT
      LAYER M3 ;
        RECT  65.196 36.576 65.214 36.72 ;
    END
  END dq[498]
  PIN dq[499]
    DIRECTION OUTPUT ;
    USE SIGNAL ;
    PORT
      LAYER M5 ;
        RECT  65.28 36.528 65.304 36.72 ;
    END
  END dq[499]
  PIN dq[49]
    DIRECTION OUTPUT ;
    USE SIGNAL ;
    PORT
      LAYER M5 ;
        RECT  10.368 36.528 10.392 36.72 ;
    END
  END dq[49]
  PIN dq[4]
    DIRECTION OUTPUT ;
    USE SIGNAL ;
    PORT
      LAYER M3 ;
        RECT  4.86 36.576 4.878 36.72 ;
    END
  END dq[4]
  PIN dq[500]
    DIRECTION OUTPUT ;
    USE SIGNAL ;
    PORT
      LAYER M3 ;
        RECT  65.412 36.576 65.43 36.72 ;
    END
  END dq[500]
  PIN dq[501]
    DIRECTION OUTPUT ;
    USE SIGNAL ;
    PORT
      LAYER M5 ;
        RECT  65.52 36.528 65.544 36.72 ;
    END
  END dq[501]
  PIN dq[502]
    DIRECTION OUTPUT ;
    USE SIGNAL ;
    PORT
      LAYER M3 ;
        RECT  65.664 36.576 65.682 36.72 ;
    END
  END dq[502]
  PIN dq[503]
    DIRECTION OUTPUT ;
    USE SIGNAL ;
    PORT
      LAYER M5 ;
        RECT  65.808 36.528 65.832 36.72 ;
    END
  END dq[503]
  PIN dq[504]
    DIRECTION OUTPUT ;
    USE SIGNAL ;
    PORT
      LAYER M3 ;
        RECT  65.916 36.576 65.934 36.72 ;
    END
  END dq[504]
  PIN dq[505]
    DIRECTION OUTPUT ;
    USE SIGNAL ;
    PORT
      LAYER M5 ;
        RECT  66.048 36.528 66.072 36.72 ;
    END
  END dq[505]
  PIN dq[506]
    DIRECTION OUTPUT ;
    USE SIGNAL ;
    PORT
      LAYER M3 ;
        RECT  66.168 36.576 66.186 36.72 ;
    END
  END dq[506]
  PIN dq[507]
    DIRECTION OUTPUT ;
    USE SIGNAL ;
    PORT
      LAYER M5 ;
        RECT  66.288 36.528 66.312 36.72 ;
    END
  END dq[507]
  PIN dq[508]
    DIRECTION OUTPUT ;
    USE SIGNAL ;
    PORT
      LAYER M3 ;
        RECT  66.384 36.576 66.402 36.72 ;
    END
  END dq[508]
  PIN dq[509]
    DIRECTION OUTPUT ;
    USE SIGNAL ;
    PORT
      LAYER M5 ;
        RECT  66.528 36.528 66.552 36.72 ;
    END
  END dq[509]
  PIN dq[50]
    DIRECTION OUTPUT ;
    USE SIGNAL ;
    PORT
      LAYER M3 ;
        RECT  10.476 36.576 10.494 36.72 ;
    END
  END dq[50]
  PIN dq[510]
    DIRECTION OUTPUT ;
    USE SIGNAL ;
    PORT
      LAYER M3 ;
        RECT  66.636 36.576 66.654 36.72 ;
    END
  END dq[510]
  PIN dq[511]
    DIRECTION OUTPUT ;
    USE SIGNAL ;
    PORT
      LAYER M5 ;
        RECT  66.768 36.528 66.792 36.72 ;
    END
  END dq[511]
  PIN dq[512]
    DIRECTION OUTPUT ;
    USE SIGNAL ;
    PORT
      LAYER M3 ;
        RECT  66.888 36.576 66.906 36.72 ;
    END
  END dq[512]
  PIN dq[51]
    DIRECTION OUTPUT ;
    USE SIGNAL ;
    PORT
      LAYER M5 ;
        RECT  10.608 36.528 10.632 36.72 ;
    END
  END dq[51]
  PIN dq[52]
    DIRECTION OUTPUT ;
    USE SIGNAL ;
    PORT
      LAYER M3 ;
        RECT  10.728 36.576 10.746 36.72 ;
    END
  END dq[52]
  PIN dq[53]
    DIRECTION OUTPUT ;
    USE SIGNAL ;
    PORT
      LAYER M5 ;
        RECT  10.848 36.528 10.872 36.72 ;
    END
  END dq[53]
  PIN dq[54]
    DIRECTION OUTPUT ;
    USE SIGNAL ;
    PORT
      LAYER M3 ;
        RECT  10.98 36.576 10.998 36.72 ;
    END
  END dq[54]
  PIN dq[55]
    DIRECTION OUTPUT ;
    USE SIGNAL ;
    PORT
      LAYER M5 ;
        RECT  11.088 36.528 11.112 36.72 ;
    END
  END dq[55]
  PIN dq[56]
    DIRECTION OUTPUT ;
    USE SIGNAL ;
    PORT
      LAYER M3 ;
        RECT  11.196 36.576 11.214 36.72 ;
    END
  END dq[56]
  PIN dq[57]
    DIRECTION OUTPUT ;
    USE SIGNAL ;
    PORT
      LAYER M5 ;
        RECT  11.328 36.528 11.352 36.72 ;
    END
  END dq[57]
  PIN dq[58]
    DIRECTION OUTPUT ;
    USE SIGNAL ;
    PORT
      LAYER M3 ;
        RECT  11.448 36.576 11.466 36.72 ;
    END
  END dq[58]
  PIN dq[59]
    DIRECTION OUTPUT ;
    USE SIGNAL ;
    PORT
      LAYER M5 ;
        RECT  11.568 36.528 11.592 36.72 ;
    END
  END dq[59]
  PIN dq[5]
    DIRECTION OUTPUT ;
    USE SIGNAL ;
    PORT
      LAYER M5 ;
        RECT  4.992 36.528 5.016 36.72 ;
    END
  END dq[5]
  PIN dq[60]
    DIRECTION OUTPUT ;
    USE SIGNAL ;
    PORT
      LAYER M3 ;
        RECT  11.7 36.576 11.718 36.72 ;
    END
  END dq[60]
  PIN dq[61]
    DIRECTION OUTPUT ;
    USE SIGNAL ;
    PORT
      LAYER M5 ;
        RECT  11.808 36.528 11.832 36.72 ;
    END
  END dq[61]
  PIN dq[62]
    DIRECTION OUTPUT ;
    USE SIGNAL ;
    PORT
      LAYER M3 ;
        RECT  11.952 36.576 11.97 36.72 ;
    END
  END dq[62]
  PIN dq[63]
    DIRECTION OUTPUT ;
    USE SIGNAL ;
    PORT
      LAYER M5 ;
        RECT  12.048 36.528 12.072 36.72 ;
    END
  END dq[63]
  PIN dq[64]
    DIRECTION OUTPUT ;
    USE SIGNAL ;
    PORT
      LAYER M3 ;
        RECT  12.204 36.576 12.222 36.72 ;
    END
  END dq[64]
  PIN dq[65]
    DIRECTION OUTPUT ;
    USE SIGNAL ;
    PORT
      LAYER M5 ;
        RECT  12.288 36.528 12.312 36.72 ;
    END
  END dq[65]
  PIN dq[66]
    DIRECTION OUTPUT ;
    USE SIGNAL ;
    PORT
      LAYER M3 ;
        RECT  12.42 36.576 12.438 36.72 ;
    END
  END dq[66]
  PIN dq[67]
    DIRECTION OUTPUT ;
    USE SIGNAL ;
    PORT
      LAYER M5 ;
        RECT  12.528 36.528 12.552 36.72 ;
    END
  END dq[67]
  PIN dq[68]
    DIRECTION OUTPUT ;
    USE SIGNAL ;
    PORT
      LAYER M3 ;
        RECT  12.672 36.576 12.69 36.72 ;
    END
  END dq[68]
  PIN dq[69]
    DIRECTION OUTPUT ;
    USE SIGNAL ;
    PORT
      LAYER M5 ;
        RECT  12.816 36.528 12.84 36.72 ;
    END
  END dq[69]
  PIN dq[6]
    DIRECTION OUTPUT ;
    USE SIGNAL ;
    PORT
      LAYER M3 ;
        RECT  5.112 36.576 5.13 36.72 ;
    END
  END dq[6]
  PIN dq[70]
    DIRECTION OUTPUT ;
    USE SIGNAL ;
    PORT
      LAYER M3 ;
        RECT  12.924 36.576 12.942 36.72 ;
    END
  END dq[70]
  PIN dq[71]
    DIRECTION OUTPUT ;
    USE SIGNAL ;
    PORT
      LAYER M5 ;
        RECT  13.056 36.528 13.08 36.72 ;
    END
  END dq[71]
  PIN dq[72]
    DIRECTION OUTPUT ;
    USE SIGNAL ;
    PORT
      LAYER M3 ;
        RECT  13.176 36.576 13.194 36.72 ;
    END
  END dq[72]
  PIN dq[73]
    DIRECTION OUTPUT ;
    USE SIGNAL ;
    PORT
      LAYER M5 ;
        RECT  13.296 36.528 13.32 36.72 ;
    END
  END dq[73]
  PIN dq[74]
    DIRECTION OUTPUT ;
    USE SIGNAL ;
    PORT
      LAYER M3 ;
        RECT  13.392 36.576 13.41 36.72 ;
    END
  END dq[74]
  PIN dq[75]
    DIRECTION OUTPUT ;
    USE SIGNAL ;
    PORT
      LAYER M5 ;
        RECT  13.536 36.528 13.56 36.72 ;
    END
  END dq[75]
  PIN dq[76]
    DIRECTION OUTPUT ;
    USE SIGNAL ;
    PORT
      LAYER M3 ;
        RECT  13.644 36.576 13.662 36.72 ;
    END
  END dq[76]
  PIN dq[77]
    DIRECTION OUTPUT ;
    USE SIGNAL ;
    PORT
      LAYER M5 ;
        RECT  13.776 36.528 13.8 36.72 ;
    END
  END dq[77]
  PIN dq[78]
    DIRECTION OUTPUT ;
    USE SIGNAL ;
    PORT
      LAYER M3 ;
        RECT  13.896 36.576 13.914 36.72 ;
    END
  END dq[78]
  PIN dq[79]
    DIRECTION OUTPUT ;
    USE SIGNAL ;
    PORT
      LAYER M5 ;
        RECT  14.016 36.528 14.04 36.72 ;
    END
  END dq[79]
  PIN dq[7]
    DIRECTION OUTPUT ;
    USE SIGNAL ;
    PORT
      LAYER M5 ;
        RECT  5.232 36.528 5.256 36.72 ;
    END
  END dq[7]
  PIN dq[80]
    DIRECTION OUTPUT ;
    USE SIGNAL ;
    PORT
      LAYER M3 ;
        RECT  14.148 36.576 14.166 36.72 ;
    END
  END dq[80]
  PIN dq[81]
    DIRECTION OUTPUT ;
    USE SIGNAL ;
    PORT
      LAYER M5 ;
        RECT  14.256 36.528 14.28 36.72 ;
    END
  END dq[81]
  PIN dq[82]
    DIRECTION OUTPUT ;
    USE SIGNAL ;
    PORT
      LAYER M3 ;
        RECT  14.4 36.576 14.418 36.72 ;
    END
  END dq[82]
  PIN dq[83]
    DIRECTION OUTPUT ;
    USE SIGNAL ;
    PORT
      LAYER M5 ;
        RECT  14.496 36.528 14.52 36.72 ;
    END
  END dq[83]
  PIN dq[84]
    DIRECTION OUTPUT ;
    USE SIGNAL ;
    PORT
      LAYER M3 ;
        RECT  14.616 36.576 14.634 36.72 ;
    END
  END dq[84]
  PIN dq[85]
    DIRECTION OUTPUT ;
    USE SIGNAL ;
    PORT
      LAYER M5 ;
        RECT  14.736 36.528 14.76 36.72 ;
    END
  END dq[85]
  PIN dq[86]
    DIRECTION OUTPUT ;
    USE SIGNAL ;
    PORT
      LAYER M3 ;
        RECT  14.868 36.576 14.886 36.72 ;
    END
  END dq[86]
  PIN dq[87]
    DIRECTION OUTPUT ;
    USE SIGNAL ;
    PORT
      LAYER M5 ;
        RECT  14.976 36.528 15 36.72 ;
    END
  END dq[87]
  PIN dq[88]
    DIRECTION OUTPUT ;
    USE SIGNAL ;
    PORT
      LAYER M3 ;
        RECT  15.12 36.576 15.138 36.72 ;
    END
  END dq[88]
  PIN dq[89]
    DIRECTION OUTPUT ;
    USE SIGNAL ;
    PORT
      LAYER M5 ;
        RECT  15.216 36.528 15.24 36.72 ;
    END
  END dq[89]
  PIN dq[8]
    DIRECTION OUTPUT ;
    USE SIGNAL ;
    PORT
      LAYER M3 ;
        RECT  5.364 36.576 5.382 36.72 ;
    END
  END dq[8]
  PIN dq[90]
    DIRECTION OUTPUT ;
    USE SIGNAL ;
    PORT
      LAYER M3 ;
        RECT  15.372 36.576 15.39 36.72 ;
    END
  END dq[90]
  PIN dq[91]
    DIRECTION OUTPUT ;
    USE SIGNAL ;
    PORT
      LAYER M5 ;
        RECT  15.504 36.528 15.528 36.72 ;
    END
  END dq[91]
  PIN dq[92]
    DIRECTION OUTPUT ;
    USE SIGNAL ;
    PORT
      LAYER M3 ;
        RECT  15.588 36.576 15.606 36.72 ;
    END
  END dq[92]
  PIN dq[93]
    DIRECTION OUTPUT ;
    USE SIGNAL ;
    PORT
      LAYER M5 ;
        RECT  15.744 36.528 15.768 36.72 ;
    END
  END dq[93]
  PIN dq[94]
    DIRECTION OUTPUT ;
    USE SIGNAL ;
    PORT
      LAYER M3 ;
        RECT  15.84 36.576 15.858 36.72 ;
    END
  END dq[94]
  PIN dq[95]
    DIRECTION OUTPUT ;
    USE SIGNAL ;
    PORT
      LAYER M5 ;
        RECT  15.984 36.528 16.008 36.72 ;
    END
  END dq[95]
  PIN dq[96]
    DIRECTION OUTPUT ;
    USE SIGNAL ;
    PORT
      LAYER M3 ;
        RECT  16.092 36.576 16.11 36.72 ;
    END
  END dq[96]
  PIN dq[97]
    DIRECTION OUTPUT ;
    USE SIGNAL ;
    PORT
      LAYER M5 ;
        RECT  16.224 36.528 16.248 36.72 ;
    END
  END dq[97]
  PIN dq[98]
    DIRECTION OUTPUT ;
    USE SIGNAL ;
    PORT
      LAYER M3 ;
        RECT  16.344 36.576 16.362 36.72 ;
    END
  END dq[98]
  PIN dq[99]
    DIRECTION OUTPUT ;
    USE SIGNAL ;
    PORT
      LAYER M5 ;
        RECT  16.464 36.528 16.488 36.72 ;
    END
  END dq[99]
  PIN dq[9]
    DIRECTION OUTPUT ;
    USE SIGNAL ;
    PORT
      LAYER M5 ;
        RECT  5.472 36.528 5.496 36.72 ;
    END
  END dq[9]
  PIN VDD
    DIRECTION INOUT ;
    USE POWER ;
    PORT
      LAYER M5 ;
        RECT  67.392 2.151 67.512 34.569 ;
        RECT  64.692 2.151 64.812 34.569 ;
        RECT  61.992 2.151 62.112 34.569 ;
        RECT  59.292 2.151 59.412 34.569 ;
        RECT  56.592 2.151 56.712 34.569 ;
        RECT  53.892 2.151 54.012 34.569 ;
        RECT  51.192 2.151 51.312 34.569 ;
        RECT  48.492 2.151 48.612 34.569 ;
        RECT  45.792 2.151 45.912 34.569 ;
        RECT  43.092 2.151 43.212 34.569 ;
        RECT  40.392 2.151 40.512 34.569 ;
        RECT  37.692 2.151 37.812 34.569 ;
        RECT  34.992 2.151 35.112 34.569 ;
        RECT  32.292 2.151 32.412 34.569 ;
        RECT  29.592 2.151 29.712 34.569 ;
        RECT  26.892 2.151 27.012 34.569 ;
        RECT  24.192 2.151 24.312 34.569 ;
        RECT  21.492 2.151 21.612 34.569 ;
        RECT  18.792 2.151 18.912 34.569 ;
        RECT  16.092 2.151 16.212 34.569 ;
        RECT  13.392 2.151 13.512 34.569 ;
        RECT  10.692 2.151 10.812 34.569 ;
        RECT  7.992 2.151 8.112 34.569 ;
        RECT  5.292 2.151 5.412 34.569 ;
        RECT  2.592 2.151 2.712 34.569 ;
    END
  END VDD
  PIN VSS
    DIRECTION INOUT ;
    USE GROUND ;
    PORT
      LAYER M5 ;
        RECT  67.2 2.137 67.32 34.583 ;
        RECT  64.5 2.137 64.62 34.583 ;
        RECT  61.8 2.137 61.92 34.583 ;
        RECT  59.1 2.137 59.22 34.583 ;
        RECT  56.4 2.137 56.52 34.583 ;
        RECT  53.7 2.137 53.82 34.583 ;
        RECT  51 2.137 51.12 34.583 ;
        RECT  48.3 2.137 48.42 34.583 ;
        RECT  45.6 2.137 45.72 34.583 ;
        RECT  42.9 2.137 43.02 34.583 ;
        RECT  40.2 2.137 40.32 34.583 ;
        RECT  37.5 2.137 37.62 34.583 ;
        RECT  34.8 2.137 34.92 34.583 ;
        RECT  32.1 2.137 32.22 34.583 ;
        RECT  29.4 2.137 29.52 34.583 ;
        RECT  26.7 2.137 26.82 34.583 ;
        RECT  24 2.137 24.12 34.583 ;
        RECT  21.3 2.137 21.42 34.583 ;
        RECT  18.6 2.137 18.72 34.583 ;
        RECT  15.9 2.137 16.02 34.583 ;
        RECT  13.2 2.137 13.32 34.583 ;
        RECT  10.5 2.137 10.62 34.583 ;
        RECT  7.8 2.137 7.92 34.583 ;
        RECT  5.1 2.137 5.22 34.583 ;
        RECT  2.4 2.137 2.52 34.583 ;
    END
  END VSS
  # OT_OBS_CLOSED layer=M5 d_um=1.536 added=115
  OBS
    LAYER RVTN ;
     RECT  2.16 2.16 69.12 2.295 ;
     RECT  2.16 2.565 69.12 2.835 ;
     RECT  2.16 3.105 69.12 3.375 ;
     RECT  2.16 3.645 69.12 3.915 ;
     RECT  2.16 4.185 69.12 4.455 ;
     RECT  2.16 4.725 69.12 4.995 ;
     RECT  2.16 5.265 69.12 5.535 ;
     RECT  2.16 5.805 69.12 6.075 ;
     RECT  2.16 6.345 69.12 6.615 ;
     RECT  2.16 6.885 69.12 7.155 ;
     RECT  2.16 7.425 69.12 7.695 ;
     RECT  2.16 7.965 69.12 8.235 ;
     RECT  2.16 8.505 69.12 8.775 ;
     RECT  2.16 9.045 69.12 9.315 ;
     RECT  2.16 9.585 69.12 9.855 ;
     RECT  2.16 10.125 69.12 10.395 ;
     RECT  2.16 10.665 69.12 10.935 ;
     RECT  2.16 11.205 69.12 11.475 ;
     RECT  2.16 11.745 69.12 12.015 ;
     RECT  2.16 12.285 69.12 12.555 ;
     RECT  2.16 12.825 69.12 13.095 ;
     RECT  2.16 13.365 69.12 13.635 ;
     RECT  2.16 13.905 69.12 14.175 ;
     RECT  2.16 14.445 69.12 14.715 ;
     RECT  2.16 14.985 69.12 15.255 ;
     RECT  2.16 15.525 69.12 15.795 ;
     RECT  2.16 16.065 69.12 16.335 ;
     RECT  2.16 16.605 69.12 16.875 ;
     RECT  2.16 17.145 69.12 17.415 ;
     RECT  2.16 17.685 69.12 17.955 ;
     RECT  2.16 18.225 69.12 18.495 ;
     RECT  2.16 18.765 69.12 19.035 ;
     RECT  2.16 19.305 69.12 19.575 ;
     RECT  2.16 19.845 69.12 20.115 ;
     RECT  2.16 20.385 69.12 20.655 ;
     RECT  2.16 20.925 69.12 21.195 ;
     RECT  2.16 21.465 69.12 21.735 ;
     RECT  2.16 22.005 69.12 22.275 ;
     RECT  2.16 22.545 69.12 22.815 ;
     RECT  2.16 23.085 69.12 23.355 ;
     RECT  2.16 23.625 69.12 23.895 ;
     RECT  2.16 24.165 69.12 24.435 ;
     RECT  2.16 24.705 69.12 24.975 ;
     RECT  2.16 25.245 69.12 25.515 ;
     RECT  2.16 25.785 69.12 26.055 ;
     RECT  2.16 26.325 69.12 26.595 ;
     RECT  2.16 26.865 69.12 27.135 ;
     RECT  2.16 27.405 69.12 27.675 ;
     RECT  2.16 27.945 69.12 28.215 ;
     RECT  2.16 28.485 69.12 28.755 ;
     RECT  2.16 29.025 69.12 29.295 ;
     RECT  2.16 29.565 69.12 29.835 ;
     RECT  2.16 30.105 69.12 30.375 ;
     RECT  2.16 30.645 69.12 30.915 ;
     RECT  2.16 31.185 69.12 31.455 ;
     RECT  2.16 31.725 69.12 31.995 ;
     RECT  2.16 32.265 69.12 32.535 ;
     RECT  2.16 32.805 69.12 33.075 ;
     RECT  2.16 33.345 69.12 33.615 ;
     RECT  2.16 33.885 69.12 34.155 ;
     RECT  2.16 34.425 69.12 34.56 ;
    LAYER RVTP ;
     RECT  2.16 2.295 69.12 2.565 ;
     RECT  2.16 2.835 69.12 3.105 ;
     RECT  2.16 3.375 69.12 3.645 ;
     RECT  2.16 3.915 69.12 4.185 ;
     RECT  2.16 4.455 69.12 4.725 ;
     RECT  2.16 4.995 69.12 5.265 ;
     RECT  2.16 5.535 69.12 5.805 ;
     RECT  2.16 6.075 69.12 6.345 ;
     RECT  2.16 6.615 69.12 6.885 ;
     RECT  2.16 7.155 69.12 7.425 ;
     RECT  2.16 7.695 69.12 7.965 ;
     RECT  2.16 8.235 69.12 8.505 ;
     RECT  2.16 8.775 69.12 9.045 ;
     RECT  2.16 9.315 69.12 9.585 ;
     RECT  2.16 9.855 69.12 10.125 ;
     RECT  2.16 10.395 69.12 10.665 ;
     RECT  2.16 10.935 69.12 11.205 ;
     RECT  2.16 11.475 69.12 11.745 ;
     RECT  2.16 12.015 69.12 12.285 ;
     RECT  2.16 12.555 69.12 12.825 ;
     RECT  2.16 13.095 69.12 13.365 ;
     RECT  2.16 13.635 69.12 13.905 ;
     RECT  2.16 14.175 69.12 14.445 ;
     RECT  2.16 14.715 69.12 14.985 ;
     RECT  2.16 15.255 69.12 15.525 ;
     RECT  2.16 15.795 69.12 16.065 ;
     RECT  2.16 16.335 69.12 16.605 ;
     RECT  2.16 16.875 69.12 17.145 ;
     RECT  2.16 17.415 69.12 17.685 ;
     RECT  2.16 17.955 69.12 18.225 ;
     RECT  2.16 18.495 69.12 18.765 ;
     RECT  2.16 19.035 69.12 19.305 ;
     RECT  2.16 19.575 69.12 19.845 ;
     RECT  2.16 20.115 69.12 20.385 ;
     RECT  2.16 20.655 69.12 20.925 ;
     RECT  2.16 21.195 69.12 21.465 ;
     RECT  2.16 21.735 69.12 22.005 ;
     RECT  2.16 22.275 69.12 22.545 ;
     RECT  2.16 22.815 69.12 23.085 ;
     RECT  2.16 23.355 69.12 23.625 ;
     RECT  2.16 23.895 69.12 24.165 ;
     RECT  2.16 24.435 69.12 24.705 ;
     RECT  2.16 24.975 69.12 25.245 ;
     RECT  2.16 25.515 69.12 25.785 ;
     RECT  2.16 26.055 69.12 26.325 ;
     RECT  2.16 26.595 69.12 26.865 ;
     RECT  2.16 27.135 69.12 27.405 ;
     RECT  2.16 27.675 69.12 27.945 ;
     RECT  2.16 28.215 69.12 28.485 ;
     RECT  2.16 28.755 69.12 29.025 ;
     RECT  2.16 29.295 69.12 29.565 ;
     RECT  2.16 29.835 69.12 30.105 ;
     RECT  2.16 30.375 69.12 30.645 ;
     RECT  2.16 30.915 69.12 31.185 ;
     RECT  2.16 31.455 69.12 31.725 ;
     RECT  2.16 31.995 69.12 32.265 ;
     RECT  2.16 32.535 69.12 32.805 ;
     RECT  2.16 33.075 69.12 33.345 ;
     RECT  2.16 33.615 69.12 33.885 ;
     RECT  2.16 34.155 69.12 34.425 ;
    LAYER M1 ;
     RECT  2.16 2.151 69.12 34.569 ;
    LAYER M2 ;
     RECT  2.16 2.151 4.135 34.569 ;
     RECT  4.135 1.728 4.855 34.569 ;
     RECT  4.855 1.728 4.999 34.794 ;
     RECT  4.999 1.728 5.135 34.839 ;
     RECT  5.359 0.144 5.531 0.162 ;
     RECT  6.547 0.144 7.331 0.162 ;
     RECT  5.135 2.151 7.771 34.569 ;
     RECT  8.779 0.144 9.779 0.162 ;
     RECT  7.771 1.728 11.399 34.569 ;
     RECT  11.695 35.901 12.047 35.919 ;
     RECT  13.135 0.144 13.667 0.162 ;
     RECT  13.639 35.901 13.891 35.919 ;
     RECT  13.891 35.901 14.243 35.964 ;
     RECT  14.611 0.144 14.711 0.162 ;
     RECT  14.243 35.946 14.747 35.964 ;
     RECT  15.583 0.144 16.087 0.162 ;
     RECT  16.087 0.144 16.367 0.324 ;
     RECT  16.267 35.982 16.367 36 ;
     RECT  18.679 36.558 18.779 36.648 ;
     RECT  11.399 2.151 18.787 34.569 ;
     RECT  18.779 36.558 18.815 36.576 ;
     RECT  18.787 1.728 18.995 34.569 ;
     RECT  18.995 2.151 19.507 34.569 ;
     RECT  19.003 35.901 19.895 35.919 ;
     RECT  19.507 2.151 20.435 34.794 ;
     RECT  21.451 0.144 21.659 0.162 ;
     RECT  20.435 2.151 24.403 34.569 ;
     RECT  24.403 1.728 24.575 34.569 ;
     RECT  24.403 35.901 24.791 35.919 ;
     RECT  24.151 0.576 25.115 0.594 ;
     RECT  24.575 2.151 26.347 34.569 ;
     RECT  26.347 2.151 26.663 34.794 ;
     RECT  27.571 0.144 27.823 0.162 ;
     RECT  27.751 36.558 27.851 36.648 ;
     RECT  27.851 36.63 27.887 36.648 ;
     RECT  27.823 0.144 27.923 0.234 ;
     RECT  26.663 2.151 28.039 34.569 ;
     RECT  28.039 2.151 28.283 34.794 ;
     RECT  27.923 0.144 28.355 0.162 ;
     RECT  28.283 2.151 29.371 34.569 ;
     RECT  29.515 0.144 29.615 0.162 ;
     RECT  29.371 2.151 29.767 34.794 ;
     RECT  30.487 0.144 30.587 0.162 ;
     RECT  29.767 1.728 30.731 34.794 ;
     RECT  30.731 1.728 30.839 34.569 ;
     RECT  30.839 1.8 31.055 34.569 ;
     RECT  31.055 2.151 31.459 34.569 ;
     RECT  31.459 2.151 32.243 34.794 ;
     RECT  32.215 0.144 32.251 0.162 ;
     RECT  32.251 0.144 32.495 0.234 ;
     RECT  32.683 36.558 32.719 36.576 ;
     RECT  32.719 36.558 32.819 36.648 ;
     RECT  32.495 0.144 33.539 0.162 ;
     RECT  33.439 35.901 34.079 35.919 ;
     RECT  32.243 2.151 34.879 34.569 ;
     RECT  34.879 0.144 34.979 0.162 ;
     RECT  34.879 2.151 35.267 34.65 ;
     RECT  35.815 0.144 35.915 0.162 ;
     RECT  35.887 35.901 36.203 35.919 ;
     RECT  35.267 2.151 36.355 34.569 ;
     RECT  36.355 1.728 37.471 34.569 ;
     RECT  37.471 1.728 37.607 34.65 ;
     RECT  38.083 35.901 38.299 35.919 ;
     RECT  37.831 0.144 38.327 0.162 ;
     RECT  38.299 35.901 38.435 36 ;
     RECT  37.607 1.728 38.615 34.569 ;
     RECT  38.435 35.901 38.795 35.919 ;
     RECT  38.615 2.151 39.775 34.569 ;
     RECT  39.775 1.728 40.171 34.569 ;
     RECT  40.171 1.728 40.307 34.65 ;
     RECT  40.495 0.144 41.027 0.162 ;
     RECT  40.307 1.728 41.315 34.569 ;
     RECT  41.315 1.8 41.639 34.569 ;
     RECT  41.639 2.151 43.195 34.569 ;
     RECT  42.943 35.901 43.195 35.919 ;
     RECT  43.699 0.144 43.799 0.162 ;
     RECT  43.195 35.901 43.907 35.964 ;
     RECT  43.195 1.728 44.123 34.569 ;
     RECT  44.123 1.8 44.555 34.569 ;
     RECT  43.907 35.901 44.663 35.919 ;
     RECT  44.555 2.151 45.139 34.569 ;
     RECT  45.895 36.558 45.931 36.576 ;
     RECT  45.391 0.144 45.995 0.162 ;
     RECT  45.931 36.558 46.031 36.648 ;
     RECT  46.615 36.018 47.119 36.036 ;
     RECT  47.119 36.018 47.147 36.108 ;
     RECT  45.139 2.151 47.551 34.794 ;
     RECT  47.147 36.09 47.831 36.108 ;
     RECT  47.731 1.152 47.867 1.17 ;
     RECT  47.551 2.151 47.867 34.839 ;
     RECT  48.199 0.144 48.875 0.162 ;
     RECT  47.867 2.151 48.911 34.794 ;
     RECT  48.911 2.151 50.827 34.569 ;
     RECT  50.467 0.144 50.971 0.162 ;
     RECT  50.971 0.144 51.035 0.234 ;
     RECT  50.827 2.151 51.035 34.65 ;
     RECT  51.035 0.216 51.287 0.234 ;
     RECT  49.531 35.901 51.511 35.919 ;
     RECT  51.511 35.901 52.115 35.964 ;
     RECT  52.115 35.901 53.519 35.919 ;
     RECT  51.035 2.151 53.707 34.569 ;
     RECT  53.707 0.144 53.879 0.162 ;
     RECT  53.707 2.151 53.959 34.65 ;
     RECT  53.959 1.728 54.059 34.65 ;
     RECT  54.059 1.728 54.275 34.569 ;
     RECT  55.147 35.901 55.499 35.919 ;
     RECT  54.275 2.151 55.651 34.569 ;
     RECT  55.651 1.728 56.147 34.569 ;
     RECT  56.371 0.576 56.623 0.594 ;
     RECT  56.623 0.144 56.759 0.594 ;
     RECT  56.759 0.576 56.875 0.594 ;
     RECT  56.147 2.106 56.939 34.569 ;
     RECT  56.875 0.576 57.047 0.666 ;
     RECT  56.875 35.901 57.343 35.919 ;
     RECT  57.047 0.648 57.767 0.666 ;
     RECT  57.343 35.901 58.487 35.964 ;
     RECT  58.531 0.144 58.595 0.162 ;
     RECT  58.487 35.946 58.667 35.964 ;
     RECT  56.939 2.151 59.323 34.569 ;
     RECT  59.323 0.144 59.459 0.162 ;
     RECT  59.323 2.151 59.711 34.794 ;
     RECT  59.711 2.151 59.791 34.569 ;
     RECT  59.575 35.901 59.791 35.919 ;
     RECT  59.791 1.728 59.927 34.569 ;
     RECT  59.791 35.901 60.295 35.964 ;
     RECT  60.295 35.901 60.503 36.036 ;
     RECT  60.503 36.018 60.547 36.036 ;
     RECT  60.511 0.144 60.575 0.162 ;
     RECT  60.547 36.018 60.583 36.576 ;
     RECT  60.583 36.018 60.647 36.648 ;
     RECT  60.647 36.558 60.683 36.648 ;
     RECT  59.927 2.151 60.763 34.569 ;
     RECT  60.763 2.151 61.267 34.794 ;
     RECT  61.267 2.151 61.411 34.839 ;
     RECT  61.411 2.151 61.547 34.92 ;
     RECT  61.547 2.151 61.699 34.569 ;
     RECT  61.699 1.656 62.015 34.569 ;
     RECT  62.015 1.728 62.375 34.569 ;
     RECT  62.375 2.151 62.455 34.569 ;
     RECT  61.987 35.901 62.483 35.919 ;
     RECT  62.455 2.151 62.995 34.758 ;
     RECT  62.995 2.151 63.463 34.794 ;
     RECT  63.463 0.144 63.527 0.162 ;
     RECT  63.211 35.901 63.563 35.919 ;
     RECT  63.463 2.151 63.779 34.839 ;
     RECT  63.779 2.151 64.067 34.794 ;
     RECT  64.067 2.151 64.687 34.569 ;
     RECT  64.687 1.728 64.867 34.569 ;
     RECT  64.687 35.901 64.939 35.919 ;
     RECT  64.867 1.152 64.967 34.569 ;
     RECT  64.967 1.728 65.183 34.569 ;
     RECT  64.939 35.901 65.191 35.964 ;
     RECT  64.435 0.144 65.435 0.162 ;
     RECT  65.191 35.901 65.723 36.036 ;
     RECT  65.723 35.901 66.083 36 ;
     RECT  65.183 2.151 66.163 34.569 ;
     RECT  66.163 0.144 66.271 0.162 ;
     RECT  66.163 2.151 66.371 34.794 ;
     RECT  66.271 0.144 66.407 0.198 ;
     RECT  66.083 35.982 66.479 36 ;
     RECT  66.407 0.144 66.551 0.162 ;
     RECT  66.371 2.151 69.12 34.569 ;
    LAYER M3 ;
     RECT  4.356 0.108 66.906 0.173 ;
     RECT  39.06 0.173 66.906 0.557 ;
     RECT  39.06 0.557 42.246 0.605 ;
     RECT  4.356 0.173 38.25 1.723 ;
     RECT  39.06 0.605 42.174 1.723 ;
     RECT  43.2 0.557 66.906 1.723 ;
     RECT  4.14 1.723 66.906 2.143 ;
     RECT  4.14 2.143 67.305 2.191 ;
     RECT  4.14 2.191 68.31 2.263 ;
     RECT  4.068 2.263 68.31 2.371 ;
     RECT  2.415 2.143 2.505 2.413 ;
     RECT  4.068 2.371 68.382 2.489 ;
     RECT  4.068 2.489 68.31 3.451 ;
     RECT  3.78 3.451 68.31 3.713 ;
     RECT  3.924 3.713 68.31 3.721 ;
     RECT  3.924 3.721 68.67 3.725 ;
     RECT  4.644 3.725 68.67 4.289 ;
     RECT  4.716 4.289 68.67 5.341 ;
     RECT  4.716 5.341 69.03 8.231 ;
     RECT  4.716 8.231 68.994 9.815 ;
     RECT  4.788 9.815 68.994 10.625 ;
     RECT  4.788 10.625 68.634 16.141 ;
     RECT  4.716 16.141 68.634 16.169 ;
     RECT  4.716 16.169 68.49 16.331 ;
     RECT  4.716 16.331 68.382 16.439 ;
     RECT  4.716 16.439 68.346 18.455 ;
     RECT  4.716 18.455 68.238 18.841 ;
     RECT  4.572 18.841 68.238 20.453 ;
     RECT  4.572 20.453 67.95 21.271 ;
     RECT  4.32 21.271 67.95 22.811 ;
     RECT  4.32 22.811 67.914 28.985 ;
     RECT  4.356 28.985 67.914 29.021 ;
     RECT  2.415 2.413 2.697 34.307 ;
     RECT  4.356 29.021 67.497 34.307 ;
     RECT  2.415 34.307 2.505 34.577 ;
     RECT  4.356 34.307 67.305 34.577 ;
     RECT  4.356 34.577 66.906 34.829 ;
     RECT  4.356 34.829 13.41 35.896 ;
     RECT  14.148 34.829 66.906 35.896 ;
     RECT  4.356 35.896 66.906 36.588 ;
     RECT  18.684 36.588 18.774 36.653 ;
     RECT  32.724 36.588 32.814 36.653 ;
     RECT  45.936 36.588 46.026 36.653 ;
     RECT  60.588 36.588 60.678 36.653 ;
    LAYER M4 ;
     RECT  0.229 4.944 2.408 4.968 ;
     RECT  2.408 2.148 2.512 34.572 ;
     RECT  2.512 2.418 2.704 34.302 ;
     RECT  4.481 34.752 4.565 34.776 ;
     RECT  3.913 3.696 4.741 3.72 ;
     RECT  2.704 4.944 4.741 4.968 ;
     RECT  4.741 3.696 4.844 4.968 ;
     RECT  4.381 1.728 4.885 1.752 ;
     RECT  4.885 1.728 5.108 2.28 ;
     RECT  4.844 3.696 5.108 5.736 ;
     RECT  4.981 29.616 5.108 29.64 ;
     RECT  4.741 33.024 5.108 33.048 ;
     RECT  5.108 1.728 5.404 34.728 ;
     RECT  5.404 34.224 5.717 34.728 ;
     RECT  5.669 0.576 5.753 0.6 ;
     RECT  5.404 4.272 5.891 6.072 ;
     RECT  5.404 33.024 5.897 33.096 ;
     RECT  5.717 34.224 6.268 34.248 ;
     RECT  5.404 1.728 6.581 1.752 ;
     RECT  5.891 4.368 6.757 6.072 ;
     RECT  6.661 2.88 6.901 2.904 ;
     RECT  6.661 35.904 7.157 35.928 ;
     RECT  6.901 2.88 7.189 2.952 ;
     RECT  5.897 33.024 7.189 33.048 ;
     RECT  7.189 2.88 7.297 3.144 ;
     RECT  6.757 4.368 7.297 6.264 ;
     RECT  7.297 2.88 7.333 6.264 ;
     RECT  5.404 28.848 7.429 28.872 ;
     RECT  7.189 1.104 7.573 1.128 ;
     RECT  7.573 1.056 7.669 1.128 ;
     RECT  7.621 34.704 7.669 34.728 ;
     RECT  7.669 1.056 7.808 1.224 ;
     RECT  7.333 2.256 7.808 6.264 ;
     RECT  7.429 28.848 7.808 29.064 ;
     RECT  7.189 33.024 7.808 33.096 ;
     RECT  7.669 34.368 7.808 34.728 ;
     RECT  7.808 1.056 7.955 34.728 ;
     RECT  7.955 1.056 8.057 34.68 ;
     RECT  8.057 1.728 8.104 34.68 ;
     RECT  8.104 34.224 8.237 34.68 ;
     RECT  8.237 34.224 8.281 34.584 ;
     RECT  8.149 0.192 8.291 0.216 ;
     RECT  8.104 2.832 8.489 3.432 ;
     RECT  8.104 28.848 8.777 29.064 ;
     RECT  8.104 33.072 9.109 33.096 ;
     RECT  9.109 33.024 9.137 33.096 ;
     RECT  8.104 1.728 9.917 1.752 ;
     RECT  8.489 2.88 9.917 3.432 ;
     RECT  8.281 34.224 10.309 34.248 ;
     RECT  9.917 1.728 10.357 3.432 ;
     RECT  8.104 4.512 10.357 6.84 ;
     RECT  8.777 29.04 10.357 29.064 ;
     RECT  10.357 1.728 10.433 6.84 ;
     RECT  10.285 18.96 10.465 18.984 ;
     RECT  10.433 2.016 10.508 6.84 ;
     RECT  10.393 16.32 10.508 16.344 ;
     RECT  10.465 18.816 10.508 18.984 ;
     RECT  10.357 28.944 10.508 29.064 ;
     RECT  9.137 33.024 10.508 33.048 ;
     RECT  10.309 34.224 10.508 34.728 ;
     RECT  10.508 2.016 10.643 34.728 ;
     RECT  10.643 2.016 10.685 34.68 ;
     RECT  10.685 2.256 10.804 34.68 ;
     RECT  10.804 28.944 10.937 28.968 ;
     RECT  10.837 0.192 10.979 0.216 ;
     RECT  10.804 34.224 10.979 34.68 ;
     RECT  10.804 33.024 11.117 33.096 ;
     RECT  10.804 2.256 11.219 6.888 ;
     RECT  10.979 34.224 11.405 34.344 ;
     RECT  11.219 2.256 11.701 6.84 ;
     RECT  11.701 2.208 11.909 6.84 ;
     RECT  11.909 2.208 12.028 2.232 ;
     RECT  11.797 28.848 12.037 28.872 ;
     RECT  12.049 10.272 12.227 10.296 ;
     RECT  12.037 28.416 12.805 28.872 ;
     RECT  11.909 3.84 13.165 6.84 ;
     RECT  12.037 1.728 13.208 1.848 ;
     RECT  13.165 3.408 13.208 6.84 ;
     RECT  12.805 28.416 13.208 29.064 ;
     RECT  11.117 33.024 13.208 33.048 ;
     RECT  11.405 34.224 13.208 34.248 ;
     RECT  13.208 1.728 13.285 34.572 ;
     RECT  13.057 0.528 13.331 0.552 ;
     RECT  13.285 1.728 13.504 34.728 ;
     RECT  13.504 34.704 13.525 34.728 ;
     RECT  13.525 34.704 13.612 34.824 ;
     RECT  13.504 1.728 13.619 7.032 ;
     RECT  13.504 32.976 13.619 33.624 ;
     RECT  13.612 34.704 13.619 34.728 ;
     RECT  13.619 32.976 13.645 33.528 ;
     RECT  13.645 32.976 14.213 33.048 ;
     RECT  13.504 9.696 14.257 9.72 ;
     RECT  13.504 31.296 14.321 31.32 ;
     RECT  13.504 28.992 14.485 29.064 ;
     RECT  13.619 2.88 14.569 7.032 ;
     RECT  14.213 32.976 14.789 33 ;
     RECT  14.785 0.144 14.897 0.168 ;
     RECT  14.485 28.848 15.205 29.064 ;
     RECT  14.569 2.88 15.461 7.368 ;
     RECT  13.619 1.728 15.908 1.752 ;
     RECT  15.461 2.832 15.908 7.368 ;
     RECT  15.205 28.464 15.908 29.064 ;
     RECT  15.493 34.224 15.908 34.248 ;
     RECT  15.908 1.728 15.973 34.572 ;
     RECT  15.973 1.728 16.204 34.728 ;
     RECT  16.213 0.192 16.355 0.216 ;
     RECT  16.204 1.728 16.355 7.368 ;
     RECT  16.204 34.704 16.355 34.728 ;
     RECT  16.213 35.904 16.373 35.928 ;
     RECT  16.204 33.072 16.481 33.096 ;
     RECT  16.355 1.728 16.78 6.84 ;
     RECT  16.78 1.728 17.075 2.28 ;
     RECT  16.78 3.408 17.309 6.84 ;
     RECT  16.204 31.248 17.413 31.272 ;
     RECT  16.204 28.416 17.417 29.064 ;
     RECT  17.173 33.024 17.417 33.048 ;
     RECT  17.309 3.888 17.485 6.84 ;
     RECT  17.449 7.968 17.485 7.992 ;
     RECT  17.485 3.888 17.533 7.992 ;
     RECT  17.075 1.728 17.633 1.8 ;
     RECT  17.413 31.248 18.133 31.32 ;
     RECT  17.533 3.888 18.277 7.656 ;
     RECT  17.417 29.04 18.421 29.064 ;
     RECT  18.421 28.992 18.469 29.064 ;
     RECT  18.277 3.696 18.493 7.656 ;
     RECT  17.633 1.728 18.497 1.752 ;
     RECT  18.493 2.784 18.608 7.656 ;
     RECT  18.469 28.8 18.608 29.064 ;
     RECT  18.133 31.2 18.608 31.32 ;
     RECT  17.653 33.6 18.608 33.624 ;
     RECT  18.469 34.8 18.608 34.824 ;
     RECT  18.608 1.776 18.707 34.824 ;
     RECT  18.061 0.144 18.901 0.168 ;
     RECT  18.707 1.776 18.904 34.776 ;
     RECT  18.904 31.2 18.965 31.224 ;
     RECT  18.901 0.144 19.037 0.216 ;
     RECT  19.037 0.192 19.043 0.216 ;
     RECT  18.904 28.8 19.073 29.064 ;
     RECT  18.901 35.904 19.181 35.928 ;
     RECT  18.904 1.776 19.621 7.8 ;
     RECT  18.904 10.272 19.859 10.296 ;
     RECT  18.904 34.704 19.865 34.776 ;
     RECT  19.621 1.728 19.9 7.8 ;
     RECT  19.865 34.752 19.937 34.776 ;
     RECT  19.073 28.848 21.157 29.064 ;
     RECT  21.157 34.656 21.193 34.68 ;
     RECT  19.9 1.728 21.308 6.84 ;
     RECT  21.157 28.416 21.308 29.064 ;
     RECT  20.341 31.2 21.308 31.224 ;
     RECT  21.109 33.072 21.308 33.384 ;
     RECT  21.193 34.656 21.308 34.728 ;
     RECT  21.308 1.728 21.395 34.728 ;
     RECT  21.395 1.728 21.604 34.68 ;
     RECT  21.604 34.224 21.635 34.68 ;
     RECT  21.604 28.416 21.701 29.016 ;
     RECT  21.701 28.416 22.061 28.968 ;
     RECT  21.635 34.224 22.205 34.248 ;
     RECT  22.061 28.848 22.789 28.968 ;
     RECT  21.604 1.728 24.008 6.84 ;
     RECT  23.929 18.816 24.008 18.84 ;
     RECT  22.789 28.848 24.008 29.064 ;
     RECT  21.604 33.072 24.008 33.096 ;
     RECT  23.509 34.224 24.008 34.248 ;
     RECT  24.008 1.728 24.277 34.572 ;
     RECT  24.277 1.728 24.304 34.68 ;
     RECT  24.037 0.192 24.419 0.216 ;
     RECT  24.304 34.224 24.419 34.68 ;
     RECT  24.304 10.704 24.473 10.824 ;
     RECT  24.304 1.728 24.515 6.888 ;
     RECT  24.304 7.968 24.949 7.992 ;
     RECT  24.515 3.84 25.043 6.888 ;
     RECT  24.419 34.224 25.043 34.248 ;
     RECT  24.515 1.728 25.049 2.856 ;
     RECT  24.304 33.024 25.445 33.048 ;
     RECT  22.549 35.904 25.589 35.928 ;
     RECT  25.049 1.728 25.625 1.8 ;
     RECT  24.304 28.992 25.957 29.064 ;
     RECT  25.049 2.832 26.197 2.856 ;
     RECT  25.043 3.84 26.197 6.84 ;
     RECT  25.717 33.6 26.437 33.624 ;
     RECT  26.533 0.192 26.549 0.216 ;
     RECT  26.549 0.192 26.633 0.552 ;
     RECT  25.625 1.728 26.708 1.752 ;
     RECT  26.197 2.832 26.708 6.84 ;
     RECT  26.233 18.576 26.708 18.6 ;
     RECT  25.957 28.416 26.708 29.064 ;
     RECT  26.437 33.024 26.708 33.624 ;
     RECT  26.581 34.8 26.708 34.824 ;
     RECT  26.633 0.192 26.771 0.216 ;
     RECT  26.708 1.728 26.771 34.824 ;
     RECT  26.771 1.728 27.004 34.776 ;
     RECT  27.061 0.144 27.155 0.168 ;
     RECT  27.004 1.728 27.347 6.84 ;
     RECT  27.004 28.992 27.425 29.064 ;
     RECT  27.347 1.728 27.533 1.752 ;
     RECT  27.425 28.992 28.037 29.016 ;
     RECT  26.965 35.904 28.397 35.928 ;
     RECT  27.347 2.784 28.421 6.84 ;
     RECT  28.165 33.024 28.433 33.048 ;
     RECT  28.421 2.256 29.105 6.84 ;
     RECT  27.004 34.752 29.221 34.776 ;
     RECT  29.105 1.728 29.408 6.84 ;
     RECT  28.405 29.04 29.408 29.064 ;
     RECT  29.125 33.072 29.408 33.624 ;
     RECT  29.221 34.752 29.408 34.824 ;
     RECT  29.408 1.728 29.653 34.824 ;
     RECT  29.653 1.728 29.704 34.872 ;
     RECT  29.704 1.728 29.765 2.04 ;
     RECT  29.704 34.752 29.843 34.872 ;
     RECT  29.704 3.408 30.053 6.84 ;
     RECT  30.133 35.904 30.485 35.928 ;
     RECT  30.053 3.408 30.853 5.592 ;
     RECT  30.853 2.88 31.057 5.592 ;
     RECT  30.053 6.624 31.057 6.84 ;
     RECT  29.704 28.848 31.061 29.064 ;
     RECT  29.765 1.728 31.285 1.752 ;
     RECT  31.057 2.88 31.285 6.84 ;
     RECT  31.285 1.728 31.385 6.84 ;
     RECT  29.843 34.752 31.573 34.776 ;
     RECT  31.573 34.704 31.909 34.776 ;
     RECT  31.957 0.192 32.099 0.216 ;
     RECT  31.385 2.016 32.108 6.84 ;
     RECT  31.061 28.848 32.108 29.016 ;
     RECT  31.813 31.2 32.108 31.224 ;
     RECT  31.916 32.496 32.108 32.52 ;
     RECT  31.909 34.704 32.108 34.968 ;
     RECT  32.108 2.016 32.387 34.968 ;
     RECT  32.387 2.016 32.404 34.776 ;
     RECT  32.404 2.016 32.501 7.464 ;
     RECT  32.404 31.2 32.645 31.224 ;
     RECT  32.924 0.144 33.011 0.168 ;
     RECT  32.404 34.224 33.077 34.776 ;
     RECT  32.501 2.832 33.157 7.464 ;
     RECT  32.404 28.848 33.541 28.92 ;
     RECT  32.581 1.728 33.589 1.752 ;
     RECT  33.157 2.832 33.589 6.84 ;
     RECT  33.077 34.224 33.617 34.248 ;
     RECT  33.541 8.544 33.625 8.568 ;
     RECT  33.589 1.728 33.653 6.84 ;
     RECT  33.653 1.728 33.833 6.744 ;
     RECT  33.541 28.464 34.501 28.92 ;
     RECT  34.652 34.608 34.693 34.632 ;
     RECT  34.693 34.608 34.787 34.728 ;
     RECT  33.833 1.728 34.808 2.856 ;
     RECT  33.833 3.984 34.808 6.744 ;
     RECT  34.501 28.464 34.808 29.064 ;
     RECT  33.781 33.024 34.808 33.048 ;
     RECT  34.787 34.608 34.808 34.68 ;
     RECT  34.808 1.728 35.104 34.68 ;
     RECT  34.124 0.144 35.219 0.168 ;
     RECT  35.104 34.656 35.219 34.68 ;
     RECT  35.104 1.728 35.381 6.648 ;
     RECT  35.104 28.848 35.561 29.064 ;
     RECT  35.381 3.936 35.795 6.648 ;
     RECT  34.261 35.904 36.281 35.928 ;
     RECT  35.795 3.936 36.388 6.312 ;
     RECT  36.388 3.888 36.419 6.312 ;
     RECT  35.381 1.728 36.421 2.904 ;
     RECT  36.419 3.888 36.421 6.12 ;
     RECT  36.229 34.224 36.461 34.248 ;
     RECT  35.104 33.024 36.469 33.048 ;
     RECT  36.469 33.024 36.497 33.096 ;
     RECT  36.421 1.728 36.533 6.12 ;
     RECT  36.533 1.728 36.713 1.8 ;
     RECT  35.561 29.04 36.949 29.064 ;
     RECT  36.713 1.776 37.001 1.8 ;
     RECT  37.349 34.608 37.388 34.632 ;
     RECT  37.333 0.192 37.475 0.216 ;
     RECT  37.388 34.608 37.475 34.728 ;
     RECT  36.533 2.88 37.508 6.12 ;
     RECT  36.949 28.848 37.508 29.064 ;
     RECT  35.104 31.296 37.508 31.32 ;
     RECT  36.497 33.072 37.508 33.096 ;
     RECT  37.475 34.608 37.508 34.68 ;
     RECT  37.508 2.148 37.804 34.68 ;
     RECT  37.669 0.288 37.955 0.312 ;
     RECT  37.804 32.496 37.955 33.048 ;
     RECT  37.804 34.224 37.955 34.68 ;
     RECT  37.804 2.148 38.197 6.312 ;
     RECT  37.957 35.904 38.333 35.928 ;
     RECT  37.955 33.024 38.765 33.048 ;
     RECT  38.197 1.728 38.981 6.312 ;
     RECT  38.981 1.824 39.203 6.312 ;
     RECT  38.54 0.144 39.347 0.168 ;
     RECT  37.955 34.224 39.637 34.248 ;
     RECT  39.085 33.072 39.877 33.096 ;
     RECT  39.877 33.072 39.973 33.144 ;
     RECT  39.877 0.192 40.019 0.216 ;
     RECT  40.021 0.288 40.069 0.312 ;
     RECT  39.637 34.224 40.117 34.344 ;
     RECT  40.069 0.288 40.163 0.408 ;
     RECT  39.203 2.16 40.208 6.312 ;
     RECT  37.804 28.944 40.208 29.064 ;
     RECT  39.973 33.024 40.208 33.144 ;
     RECT  40.117 34.224 40.208 34.68 ;
     RECT  40.208 2.148 40.312 34.68 ;
     RECT  40.312 2.418 40.385 34.68 ;
     RECT  40.163 0.384 40.403 0.408 ;
     RECT  40.385 2.418 40.504 34.302 ;
     RECT  40.504 18.48 40.709 18.504 ;
     RECT  40.357 35.904 40.709 35.928 ;
     RECT  40.504 28.8 41.141 29.064 ;
     RECT  40.504 2.784 41.509 6.888 ;
     RECT  41.605 7.968 41.747 7.992 ;
     RECT  41.605 33.072 41.845 33.096 ;
     RECT  41.141 29.04 41.897 29.064 ;
     RECT  41.509 2.688 41.989 6.888 ;
     RECT  41.989 2.304 42.101 6.888 ;
     RECT  41.948 0.144 42.145 0.168 ;
     RECT  42.145 0.144 42.257 0.6 ;
     RECT  42.101 2.304 42.325 7.464 ;
     RECT  40.504 34.224 42.805 34.248 ;
     RECT  42.325 1.728 42.908 7.464 ;
     RECT  41.845 33.024 42.908 33.096 ;
     RECT  42.805 34.224 42.908 34.68 ;
     RECT  42.257 0.144 42.977 0.552 ;
     RECT  42.908 1.728 43.204 34.68 ;
     RECT  42.977 0.144 43.331 0.312 ;
     RECT  43.204 33.024 43.331 34.68 ;
     RECT  43.331 0.144 43.523 0.168 ;
     RECT  43.204 1.728 43.697 6.792 ;
     RECT  43.331 33.024 43.769 33.144 ;
     RECT  43.769 33.12 43.805 33.144 ;
     RECT  43.697 1.728 44.057 3.864 ;
     RECT  43.331 34.224 44.345 34.248 ;
     RECT  43.045 35.904 45.013 35.928 ;
     RECT  44.057 1.728 45.253 1.752 ;
     RECT  44.533 28.848 45.253 28.872 ;
     RECT  45.253 1.728 45.608 1.8 ;
     RECT  44.057 2.88 45.608 3.864 ;
     RECT  43.697 5.136 45.608 6.792 ;
     RECT  45.253 28.848 45.608 29.064 ;
     RECT  45.493 34.752 45.608 34.776 ;
     RECT  45.608 1.728 45.904 34.776 ;
     RECT  45.733 0.288 45.973 0.312 ;
     RECT  45.973 0.192 46.019 0.312 ;
     RECT  45.904 1.728 46.019 4.344 ;
     RECT  46.019 0.192 46.115 0.216 ;
     RECT  46.019 1.728 46.117 2.28 ;
     RECT  45.904 6 46.325 6.312 ;
     RECT  46.604 0.144 46.691 0.168 ;
     RECT  45.904 34.752 46.757 34.776 ;
     RECT  46.019 3.84 46.793 4.344 ;
     RECT  46.325 6 46.969 6.264 ;
     RECT  46.117 1.728 47.213 1.8 ;
     RECT  45.013 35.904 47.297 35.976 ;
     RECT  47.213 1.728 47.365 1.896 ;
     RECT  46.793 3.984 47.365 4.344 ;
     RECT  46.969 5.952 47.365 6.264 ;
     RECT  47.365 1.728 47.429 2.856 ;
     RECT  47.221 29.04 47.461 29.064 ;
     RECT  47.297 35.904 47.477 35.928 ;
     RECT  47.365 3.984 47.689 6.264 ;
     RECT  47.429 1.728 47.833 2.904 ;
     RECT  47.689 3.984 47.833 6.888 ;
     RECT  47.66 34.224 47.941 34.248 ;
     RECT  47.941 34.224 48.133 34.776 ;
     RECT  47.833 1.728 48.181 6.888 ;
     RECT  48.181 1.728 48.308 6.936 ;
     RECT  47.461 28.944 48.308 29.064 ;
     RECT  48.133 34.224 48.308 34.824 ;
     RECT  48.308 1.728 48.467 34.824 ;
     RECT  48.467 1.728 48.604 34.302 ;
     RECT  48.604 28.992 48.989 29.016 ;
     RECT  48.604 34.224 49.429 34.302 ;
     RECT  49.429 34.224 49.601 34.344 ;
     RECT  48.604 1.728 49.673 6.936 ;
     RECT  49.673 2.784 49.717 6.936 ;
     RECT  49.717 2.784 49.813 6.984 ;
     RECT  49.813 2.784 49.897 7.464 ;
     RECT  49.897 2.784 49.961 6.984 ;
     RECT  49.669 29.04 50.149 29.064 ;
     RECT  50.821 18.96 50.929 18.984 ;
     RECT  49.673 1.728 51.008 1.8 ;
     RECT  49.961 2.832 51.008 6.984 ;
     RECT  50.929 18.768 51.008 18.984 ;
     RECT  50.149 28.992 51.008 29.064 ;
     RECT  49.601 34.224 51.008 34.248 ;
     RECT  48.661 35.904 51.109 35.928 ;
     RECT  51.008 1.728 51.304 34.572 ;
     RECT  51.304 34.224 51.349 34.572 ;
     RECT  51.109 35.904 51.689 36.024 ;
     RECT  51.349 34.224 51.833 34.68 ;
     RECT  51.833 34.272 51.869 34.68 ;
     RECT  51.304 7.44 51.875 7.464 ;
     RECT  51.304 1.728 51.905 6.408 ;
     RECT  51.304 10.272 52.057 10.296 ;
     RECT  51.869 34.272 52.445 34.296 ;
     RECT  51.905 1.728 52.873 6.312 ;
     RECT  52.873 1.728 52.981 6.36 ;
     RECT  52.22 0.144 53.267 0.168 ;
     RECT  52.981 1.728 53.297 6.744 ;
     RECT  53.297 1.728 53.708 6.888 ;
     RECT  52.945 7.968 53.708 7.992 ;
     RECT  52.357 29.616 53.708 29.64 ;
     RECT  52.597 33.072 53.708 33.096 ;
     RECT  53.317 34.224 53.708 34.248 ;
     RECT  51.689 35.904 53.797 35.928 ;
     RECT  53.708 1.728 53.812 34.572 ;
     RECT  53.812 1.728 54.004 34.302 ;
     RECT  53.797 35.904 54.037 35.976 ;
     RECT  54.004 1.728 54.101 6.84 ;
     RECT  54.101 1.824 54.137 6.84 ;
     RECT  54.137 2.208 54.173 6.84 ;
     RECT  54.037 35.904 54.533 36.024 ;
     RECT  54.173 2.256 54.749 6.84 ;
     RECT  54.533 35.904 55.001 35.976 ;
     RECT  54.749 2.736 55.141 6.84 ;
     RECT  54.004 8.016 55.145 8.04 ;
     RECT  54.004 34.224 55.285 34.248 ;
     RECT  55.285 34.224 55.289 34.296 ;
     RECT  55.141 2.736 55.313 6.888 ;
     RECT  55.525 28.848 55.765 28.872 ;
     RECT  55.868 0.144 55.955 0.168 ;
     RECT  55.285 1.728 56.081 1.752 ;
     RECT  55.313 2.736 56.408 7.464 ;
     RECT  55.765 28.848 56.408 29.064 ;
     RECT  55.289 34.272 56.408 34.296 ;
     RECT  56.408 2.148 56.704 34.572 ;
     RECT  56.485 0.192 56.819 0.312 ;
     RECT  56.819 0.192 56.867 0.216 ;
     RECT  56.725 34.656 57.017 34.68 ;
     RECT  56.704 2.148 57.253 7.464 ;
     RECT  57.253 1.728 57.521 7.464 ;
     RECT  57.521 1.824 57.557 7.464 ;
     RECT  55.001 35.904 57.773 35.928 ;
     RECT  56.704 28.416 57.917 28.44 ;
     RECT  58.316 0.144 58.403 0.168 ;
     RECT  57.557 2.208 58.549 7.464 ;
     RECT  57.973 28.464 58.981 29.064 ;
     RECT  57.733 34.752 58.981 34.776 ;
     RECT  58.549 2.16 59.108 7.464 ;
     RECT  58.957 26.784 59.108 26.808 ;
     RECT  58.981 28.464 59.108 29.544 ;
     RECT  56.704 33.024 59.108 33.048 ;
     RECT  58.981 34.752 59.108 34.872 ;
     RECT  59.108 2.148 59.173 34.872 ;
     RECT  59.173 2.016 59.219 34.872 ;
     RECT  59.219 2.016 59.404 34.824 ;
     RECT  59.404 2.016 59.555 6.936 ;
     RECT  59.404 34.752 59.555 34.824 ;
     RECT  59.404 28.464 59.573 29.544 ;
     RECT  59.413 0.192 59.603 0.216 ;
     RECT  59.404 9.072 59.645 9.72 ;
     RECT  59.555 2.016 59.893 6.888 ;
     RECT  59.573 28.848 59.969 29.544 ;
     RECT  59.893 1.728 60.005 6.888 ;
     RECT  59.893 35.904 60.181 35.928 ;
     RECT  60.005 1.728 60.257 6.84 ;
     RECT  59.969 28.848 60.257 29.064 ;
     RECT  60.257 1.728 60.409 2.76 ;
     RECT  59.645 9.696 60.437 9.72 ;
     RECT  59.404 19.104 60.545 19.128 ;
     RECT  60.541 10.752 60.653 10.776 ;
     RECT  60.181 35.904 61.141 35.976 ;
     RECT  60.257 28.848 61.381 28.872 ;
     RECT  61.141 35.904 61.409 36.024 ;
     RECT  60.409 1.728 61.525 2.712 ;
     RECT  60.257 3.84 61.525 6.84 ;
     RECT  61.525 1.728 61.573 6.84 ;
     RECT  59.555 34.752 61.669 34.776 ;
     RECT  61.573 1.728 61.808 6.936 ;
     RECT  61.381 28.464 61.808 28.872 ;
     RECT  61.621 33.024 61.808 33.048 ;
     RECT  61.669 34.752 61.808 34.872 ;
     RECT  61.808 1.728 61.907 34.872 ;
     RECT  61.907 1.728 62.104 34.572 ;
     RECT  61.409 35.904 62.581 35.976 ;
     RECT  62.104 3.408 62.669 6.888 ;
     RECT  61.669 0.288 62.675 0.312 ;
     RECT  62.104 7.968 62.741 7.992 ;
     RECT  62.669 3.552 62.813 6.312 ;
     RECT  62.581 35.904 62.849 36.024 ;
     RECT  62.849 35.904 63.065 35.976 ;
     RECT  62.813 3.84 63.317 6.312 ;
     RECT  63.317 3.84 63.395 6.024 ;
     RECT  63.997 0.576 64.115 0.6 ;
     RECT  63.395 3.888 64.429 6.024 ;
     RECT  62.104 1.728 64.508 2.328 ;
     RECT  64.429 3.84 64.508 6.024 ;
     RECT  64.357 18.432 64.508 18.456 ;
     RECT  64.309 28.464 64.508 28.488 ;
     RECT  63.109 29.616 64.508 29.64 ;
     RECT  63.829 33.024 64.508 33.048 ;
     RECT  62.869 34.752 64.508 34.776 ;
     RECT  64.508 1.728 64.549 34.776 ;
     RECT  64.549 1.728 64.804 34.824 ;
     RECT  64.804 32.496 64.931 33.048 ;
     RECT  64.804 34.752 64.931 34.824 ;
     RECT  64.804 15.936 64.973 15.96 ;
     RECT  64.804 18.96 64.973 18.984 ;
     RECT  64.804 4.512 65.117 6.456 ;
     RECT  64.931 34.752 65.513 34.776 ;
     RECT  64.804 3.408 65.593 3.432 ;
     RECT  64.931 33.024 66.053 33.048 ;
     RECT  65.117 4.512 66.157 4.824 ;
     RECT  65.117 6 66.233 6.456 ;
     RECT  66.157 3.984 66.265 4.824 ;
     RECT  66.233 6 66.265 6.024 ;
     RECT  63.065 35.904 66.413 35.928 ;
     RECT  66.277 29.04 66.517 29.064 ;
     RECT  64.804 1.728 66.803 1.8 ;
     RECT  66.265 3.984 67.208 6.024 ;
     RECT  66.517 28.992 67.208 29.064 ;
     RECT  66.757 34.176 67.208 34.2 ;
     RECT  67.208 2.148 67.312 34.572 ;
     RECT  67.312 2.418 67.504 34.302 ;
     RECT  67.504 4.512 67.619 4.536 ;
     RECT  67.504 5.76 67.619 5.784 ;
    LAYER M5 ;
     RECT  27.12 0.133 27.144 0.144 ;
     RECT  32.976 0.133 33 0.144 ;
     RECT  34.176 0.133 34.2 0.144 ;
     RECT  35.184 0.133 35.208 0.144 ;
     RECT  38.592 0.133 39.336 0.144 ;
     RECT  42 0.133 42.504 0.144 ;
     RECT  43.488 0.133 43.512 0.144 ;
     RECT  46.656 0.133 46.68 0.144 ;
     RECT  52.272 0.133 53.256 0.144 ;
     RECT  55.92 0.133 55.944 0.144 ;
     RECT  58.368 0.133 58.392 0.144 ;
     RECT  4.512 0.144 66.792 1.763 ;
     RECT  6.672 1.763 17.448 1.811 ;
     RECT  18.6 1.763 66.792 1.811 ;
     RECT  6.672 1.811 17.064 1.859 ;
     RECT  18.6 1.811 25.032 1.907 ;
     RECT  2.4 2.137 2.52 2.151 ;
     RECT  67.2 2.137 67.32 2.151 ;
     RECT  4.992 1.763 5.412 2.291 ;
     RECT  26.208 1.811 65.544 2.339 ;
     RECT  26.208 2.339 63.384 2.821 ;
     RECT  6.672 1.859 11.976 2.915 ;
     RECT  26.16 2.821 63.384 2.915 ;
     RECT  6.912 2.915 11.976 2.963 ;
     RECT  13.2 1.859 17.064 2.963 ;
     RECT  7.2 2.963 11.976 3.011 ;
     RECT  7.2 3.011 8.904 3.155 ;
     RECT  7.344 3.155 8.904 3.443 ;
     RECT  15.216 2.963 17.064 3.443 ;
     RECT  26.16 2.915 43.992 3.443 ;
     RECT  64.5 2.339 65.544 3.443 ;
     RECT  18.6 1.907 24.936 3.685 ;
     RECT  9.936 3.011 11.976 3.829 ;
     RECT  13.2 2.963 13.992 3.829 ;
     RECT  45.072 2.915 63.384 3.875 ;
     RECT  15.504 3.443 17.064 3.925 ;
     RECT  18.288 3.685 24.936 3.925 ;
     RECT  7.344 3.443 8.112 4.019 ;
     RECT  26.16 3.443 30.168 4.019 ;
     RECT  45.072 3.875 63.24 4.019 ;
     RECT  5.1 2.291 5.412 4.261 ;
     RECT  15.504 3.925 24.936 4.261 ;
     RECT  31.296 3.443 43.992 4.405 ;
     RECT  67.2 2.151 67.512 4.501 ;
     RECT  31.248 4.405 43.992 4.883 ;
     RECT  9.936 3.829 13.992 5.171 ;
     RECT  31.248 4.883 38.76 5.171 ;
     RECT  39.792 4.883 43.992 5.171 ;
     RECT  47.376 4.019 63.24 5.171 ;
     RECT  47.856 5.171 63.24 5.219 ;
     RECT  7.68 4.019 8.112 5.267 ;
     RECT  31.248 5.171 36.456 5.267 ;
     RECT  10.128 5.171 13.992 5.317 ;
     RECT  4.896 4.261 5.88 5.365 ;
     RECT  10.128 5.317 14.424 5.459 ;
     RECT  4.896 5.365 6.792 5.747 ;
     RECT  31.296 5.267 36.456 5.747 ;
     RECT  61.536 5.219 63.24 5.747 ;
     RECT  15.504 4.261 25.032 5.795 ;
     RECT  61.536 5.747 63.144 5.795 ;
     RECT  67.2 4.501 67.608 5.795 ;
     RECT  20.928 5.795 25.032 5.843 ;
     RECT  34.128 5.747 36.408 5.843 ;
     RECT  13.2 5.459 14.424 5.893 ;
     RECT  15.504 5.795 19.56 5.893 ;
     RECT  10.128 5.459 12.216 6.083 ;
     RECT  39.792 5.171 43.212 6.229 ;
     RECT  6.768 5.747 6.792 6.275 ;
     RECT  20.928 5.843 22.824 6.323 ;
     RECT  26.208 4.019 29.712 6.323 ;
     RECT  31.632 5.747 33.144 6.323 ;
     RECT  34.8 5.843 36.408 6.323 ;
     RECT  37.5 5.171 38.76 6.323 ;
     RECT  39.792 6.229 43.32 6.323 ;
     RECT  45.072 4.019 46.104 6.323 ;
     RECT  61.536 5.795 63 6.323 ;
     RECT  26.7 6.323 28.152 6.371 ;
     RECT  47.856 5.219 60.408 6.371 ;
     RECT  40.2 6.323 43.32 6.419 ;
     RECT  21.3 6.323 22.056 6.563 ;
     RECT  13.2 5.893 19.56 6.611 ;
     RECT  52.992 6.371 60.408 6.611 ;
     RECT  34.8 6.323 35.784 6.659 ;
     RECT  45.072 6.323 45.912 6.803 ;
     RECT  32.1 6.323 33.144 6.805 ;
     RECT  10.5 6.083 12.216 6.851 ;
     RECT  13.2 6.611 14.424 6.851 ;
     RECT  15.648 6.611 18.912 6.851 ;
     RECT  26.7 6.371 27.288 6.851 ;
     RECT  10.5 6.851 11.208 6.899 ;
     RECT  24 5.843 25.032 6.899 ;
     RECT  40.2 6.419 43.212 6.899 ;
     RECT  47.856 6.371 48.612 6.899 ;
     RECT  55.248 6.611 60.408 6.899 ;
     RECT  48.192 6.899 48.612 6.947 ;
     RECT  49.728 6.371 52.008 6.947 ;
     RECT  55.344 6.899 60.408 6.947 ;
     RECT  61.584 6.323 62.424 6.947 ;
     RECT  49.728 6.947 49.848 6.995 ;
     RECT  13.2 6.851 14.28 7.043 ;
     RECT  15.9 6.851 16.344 7.379 ;
     RECT  32.1 6.805 33.576 7.475 ;
     RECT  41.712 6.899 43.212 7.475 ;
     RECT  49.824 6.995 49.848 7.475 ;
     RECT  55.344 6.947 59.412 7.475 ;
     RECT  17.472 6.851 18.912 7.571 ;
     RECT  18.48 7.571 18.912 7.667 ;
     RECT  18.6 7.667 18.912 7.765 ;
     RECT  17.472 7.571 17.496 8.003 ;
     RECT  24 6.899 24.936 8.003 ;
     RECT  41.712 7.475 41.736 8.003 ;
     RECT  52.992 6.611 54.216 8.003 ;
     RECT  61.8 6.947 62.424 8.003 ;
     RECT  53.7 8.003 54.216 8.051 ;
     RECT  33.552 7.475 33.576 8.579 ;
     RECT  13.2 7.043 14.232 9.731 ;
     RECT  60.384 6.947 60.408 9.731 ;
     RECT  12.192 6.851 12.216 10.307 ;
     RECT  18.6 7.765 19.848 10.307 ;
     RECT  51 6.947 52.008 10.307 ;
     RECT  0.24 4.933 0.264 18.419 ;
     RECT  15.9 7.379 16.212 28.405 ;
     RECT  21.3 6.563 21.612 28.405 ;
     RECT  26.7 6.851 27.012 28.405 ;
     RECT  56.4 7.475 56.712 28.405 ;
     RECT  15.9 28.405 16.728 28.453 ;
     RECT  59.1 7.475 59.412 28.453 ;
     RECT  61.8 8.003 62.112 28.453 ;
     RECT  64.5 3.443 64.812 28.453 ;
     RECT  18.6 10.307 18.912 28.789 ;
     RECT  40.2 6.899 40.512 28.789 ;
     RECT  5.1 5.747 5.412 28.837 ;
     RECT  7.8 5.267 8.112 28.837 ;
     RECT  12.048 28.405 12.072 28.837 ;
     RECT  15.216 28.453 16.728 28.837 ;
     RECT  18.48 28.789 18.912 28.837 ;
     RECT  21.168 28.405 21.612 28.837 ;
     RECT  29.4 6.323 29.712 28.837 ;
     RECT  32.1 7.475 32.412 28.837 ;
     RECT  33.552 28.453 33.576 28.837 ;
     RECT  34.8 6.659 35.112 28.837 ;
     RECT  37.5 6.323 37.812 28.837 ;
     RECT  56.4 28.405 57 28.837 ;
     RECT  61.392 28.453 62.112 28.837 ;
     RECT  7.8 28.837 8.232 28.933 ;
     RECT  10.5 6.899 10.812 28.933 ;
     RECT  24 8.003 24.312 28.933 ;
     RECT  48.3 6.947 48.612 28.933 ;
     RECT  13.2 9.731 13.512 28.981 ;
     RECT  18.48 28.837 22.344 28.981 ;
     RECT  23.76 28.933 24.312 28.981 ;
     RECT  25.968 28.405 27.012 28.981 ;
     RECT  29.4 28.837 29.928 28.981 ;
     RECT  31.104 28.837 31.128 28.981 ;
     RECT  39.168 28.933 39.192 28.981 ;
     RECT  51 10.307 51.312 28.981 ;
     RECT  67.2 5.795 67.512 28.981 ;
     RECT  7.632 28.933 8.232 29.029 ;
     RECT  10.368 28.933 10.812 29.029 ;
     RECT  11.808 28.837 12.072 29.029 ;
     RECT  13.056 28.981 13.512 29.029 ;
     RECT  14.496 28.837 16.728 29.029 ;
     RECT  18.432 28.981 24.552 29.029 ;
     RECT  25.968 28.981 27.48 29.029 ;
     RECT  29.4 28.981 31.128 29.029 ;
     RECT  32.1 28.837 35.208 29.029 ;
     RECT  36.96 28.837 37.812 29.029 ;
     RECT  38.928 28.981 39.192 29.029 ;
     RECT  40.2 28.789 40.92 29.029 ;
     RECT  44.544 28.837 44.568 29.029 ;
     RECT  45.6 6.803 45.912 29.029 ;
     RECT  47.472 28.933 48.612 29.029 ;
     RECT  50.16 28.981 51.312 29.029 ;
     RECT  58.704 28.453 59.412 29.029 ;
     RECT  60.432 28.837 62.112 29.029 ;
     RECT  66.528 28.981 67.512 29.029 ;
     RECT  5.1 28.837 5.976 29.605 ;
     RECT  11.808 29.029 31.128 31.189 ;
     RECT  32.1 29.029 35.544 31.189 ;
     RECT  11.808 31.189 35.544 31.285 ;
     RECT  36.72 29.029 39.192 31.285 ;
     RECT  64.32 28.453 64.812 32.485 ;
     RECT  4.992 29.605 5.976 33.013 ;
     RECT  7.44 29.029 10.812 33.013 ;
     RECT  11.808 31.285 39.192 33.013 ;
     RECT  40.2 29.029 41.4 33.013 ;
     RECT  42.9 7.475 43.212 33.013 ;
     RECT  55.536 28.837 57 33.013 ;
     RECT  57.984 29.029 62.112 33.013 ;
     RECT  63.12 29.605 63.144 33.013 ;
     RECT  64.32 32.485 64.92 33.013 ;
     RECT  66.288 29.029 67.512 33.013 ;
     RECT  52.368 29.605 52.392 33.061 ;
     RECT  53.7 8.051 54.012 33.061 ;
     RECT  4.752 33.013 43.368 33.109 ;
     RECT  44.544 29.029 45.912 33.109 ;
     RECT  47.232 29.029 48.612 34.213 ;
     RECT  49.68 29.029 51.312 34.213 ;
     RECT  52.368 33.061 54.012 34.213 ;
     RECT  55.536 33.013 62.112 34.213 ;
     RECT  2.4 2.151 2.712 34.569 ;
     RECT  47.232 34.213 62.112 34.569 ;
     RECT  63.12 33.013 67.512 34.569 ;
     RECT  2.4 34.569 2.52 34.583 ;
     RECT  47.232 34.569 53.82 34.583 ;
     RECT  54.816 34.569 62.112 34.583 ;
     RECT  63.12 34.569 67.32 34.583 ;
     RECT  4.752 33.109 45.912 34.741 ;
     RECT  47.232 34.583 53.352 34.741 ;
     RECT  63.12 34.583 66.792 34.741 ;
     RECT  4.512 34.741 53.352 35.893 ;
     RECT  54.816 34.583 61.896 35.893 ;
     RECT  62.88 34.741 66.792 35.893 ;
     RECT  4.512 35.893 53.592 35.941 ;
     RECT  54.576 35.893 66.792 35.941 ;
     RECT  4.512 35.941 66.792 36.56 ;
     RECT  33 0.133 33.024 0.144 ;
     RECT  33.144 0.133 33.264 0.144 ;
     RECT  33.384 0.133 33.504 0.144 ;
     RECT  33.624 0.133 33.744 0.144 ;
     RECT  33.864 0.133 33.984 0.144 ;
     RECT  34.104 0.133 34.176 0.144 ;
     RECT  34.2 0.133 34.224 0.144 ;
     RECT  34.344 0.133 34.464 0.144 ;
     RECT  34.584 0.133 34.704 0.144 ;
     RECT  34.824 0.133 34.992 0.144 ;
     RECT  35.112 0.133 35.184 0.144 ;
     RECT  42.504 0.133 42.528 0.144 ;
     RECT  42.648 0.133 42.768 0.144 ;
     RECT  42.888 0.133 43.008 0.144 ;
     RECT  43.128 0.133 43.296 0.144 ;
     RECT  43.416 0.133 43.488 0.144 ;
     RECT  5.412 1.763 6.672 2.915 ;
     RECT  17.448 1.763 18.6 1.811 ;
     RECT  25.032 1.811 26.208 1.907 ;
     RECT  11.976 1.859 13.2 3.829 ;
     RECT  24.936 1.907 26.208 2.821 ;
     RECT  63.384 2.339 64.5 3.875 ;
     RECT  24.936 2.821 26.16 4.019 ;
     RECT  5.412 2.915 6.912 2.963 ;
     RECT  43.992 2.915 45.072 5.171 ;
     RECT  5.412 2.963 7.2 3.155 ;
     RECT  13.992 2.963 15.216 3.443 ;
     RECT  8.904 3.011 9.936 3.443 ;
     RECT  5.412 3.155 7.344 4.019 ;
     RECT  13.992 3.443 15.504 5.317 ;
     RECT  30.168 3.443 31.296 4.019 ;
     RECT  17.064 3.685 18.288 3.925 ;
     RECT  63.24 3.875 64.5 5.747 ;
     RECT  5.412 4.019 7.68 4.261 ;
     RECT  24.936 4.019 26.208 4.261 ;
     RECT  31.248 4.019 31.296 4.405 ;
     RECT  46.104 4.019 47.376 5.171 ;
     RECT  5.88 4.261 7.68 5.267 ;
     RECT  25.032 4.261 26.208 6.323 ;
     RECT  38.76 4.883 39.792 6.323 ;
     RECT  36.456 5.171 37.5 5.747 ;
     RECT  43.212 5.171 43.32 6.229 ;
     RECT  60.408 5.219 61.536 6.323 ;
     RECT  5.88 5.267 7.8 5.365 ;
     RECT  14.424 5.317 15.504 5.893 ;
     RECT  6.792 5.365 7.8 6.275 ;
     RECT  12.216 5.459 13.2 10.307 ;
     RECT  5.412 5.747 6.768 6.275 ;
     RECT  33.144 5.747 34.128 5.843 ;
     RECT  36.408 5.747 37.5 6.323 ;
     RECT  63.144 5.747 64.5 5.795 ;
     RECT  19.56 5.795 20.928 6.323 ;
     RECT  63 5.795 64.5 6.323 ;
     RECT  22.824 5.843 24 6.323 ;
     RECT  33.144 5.843 34.8 6.805 ;
     RECT  19.56 6.323 21.3 6.611 ;
     RECT  28.152 6.323 29.4 6.371 ;
     RECT  60.408 6.323 61.584 6.947 ;
     RECT  48.612 6.371 49.728 6.995 ;
     RECT  52.008 6.371 52.992 8.003 ;
     RECT  14.424 6.611 15.648 6.851 ;
     RECT  18.912 6.611 21.3 7.765 ;
     RECT  54.216 6.611 55.248 6.899 ;
     RECT  33.576 6.805 34.8 8.579 ;
     RECT  11.208 6.851 12.192 6.899 ;
     RECT  16.344 6.851 17.472 7.379 ;
     RECT  10.812 6.899 12.192 10.307 ;
     RECT  40.512 6.899 41.712 8.003 ;
     RECT  54.216 6.899 55.344 7.475 ;
     RECT  49.848 6.947 51 7.475 ;
     RECT  59.412 6.947 60.384 9.731 ;
     RECT  60.408 6.947 61.8 9.731 ;
     RECT  48.612 6.995 49.824 7.475 ;
     RECT  16.212 7.379 17.472 8.003 ;
     RECT  32.412 7.475 33.552 8.579 ;
     RECT  41.736 7.475 42.9 8.003 ;
     RECT  17.496 7.571 18.48 7.667 ;
     RECT  17.496 7.667 18.6 8.003 ;
     RECT  19.848 7.765 21.3 10.307 ;
     RECT  10.812 28.405 12.048 28.837 ;
     RECT  12.072 28.405 13.2 28.981 ;
     RECT  32.412 28.453 33.552 28.837 ;
     RECT  33.576 28.453 34.8 28.837 ;
     RECT  10.812 28.837 11.808 33.013 ;
     RECT  13.512 28.837 14.496 29.029 ;
     RECT  29.928 28.837 31.104 28.981 ;
     RECT  31.128 28.837 32.1 31.189 ;
     RECT  43.212 28.837 44.544 33.013 ;
     RECT  44.568 28.837 45.6 29.029 ;
     RECT  54.012 28.837 55.536 34.213 ;
     RECT  59.412 28.837 60.432 29.029 ;
     RECT  22.344 28.933 23.76 28.981 ;
     RECT  37.812 28.933 39.168 28.981 ;
     RECT  39.192 28.933 40.2 33.013 ;
     RECT  12.072 28.981 13.056 29.029 ;
     RECT  24.552 28.981 25.968 29.029 ;
     RECT  37.812 28.981 38.928 29.029 ;
     RECT  5.976 29.029 7.44 33.013 ;
     RECT  35.544 29.029 36.72 31.285 ;
     RECT  41.4 29.029 42.9 33.013 ;
     RECT  45.912 29.029 47.232 34.741 ;
     RECT  48.612 29.029 49.68 34.213 ;
     RECT  57 29.029 57.984 33.013 ;
     RECT  64.812 29.029 66.288 32.485 ;
     RECT  51.312 29.605 52.368 34.213 ;
     RECT  52.392 29.605 53.7 33.061 ;
     RECT  62.112 29.605 63.12 34.583 ;
     RECT  63.144 29.605 64.32 33.013 ;
     RECT  64.92 32.485 66.288 33.013 ;
     RECT  43.368 33.013 44.544 33.109 ;
     RECT  53.82 34.569 54.816 34.583 ;
     RECT  53.352 34.583 54.816 35.893 ;
     RECT  61.896 34.583 63.12 34.741 ;
     RECT  61.896 34.741 62.88 35.893 ;
     RECT  53.592 35.893 54.576 35.941 ;
  END
END dsfd_hstnv_513
END LIBRARY
